VERSION 5.7 ;
  NOWIREEXTENSIONATPIN ON ;
  DIVIDERCHAR "/" ;
  BUSBITCHARS "[]" ;
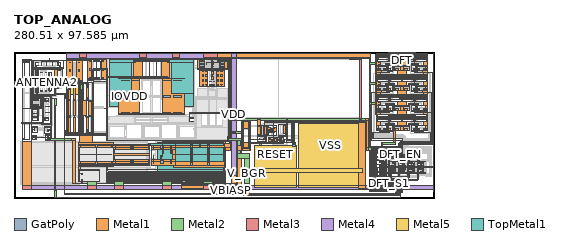
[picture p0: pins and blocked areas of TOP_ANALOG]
MACRO TOP_ANALOG
  CLASS BLOCK ;
  FOREIGN TOP_ANALOG ;
  ORIGIN 0.000 0.000 ;
  SIZE 280.510 BY 97.585 ;
  PIN RESET
    ANTENNAGATEAREA 0.767000 ;
    ANTENNADIFFAREA 5.126000 ;
    PORT
      LAYER GatPoly ;
        RECT 167.065 39.430 167.365 39.685 ;
        RECT 163.665 39.300 163.845 39.430 ;
        RECT 166.795 39.300 167.365 39.430 ;
        RECT 167.065 39.045 167.365 39.300 ;
        RECT 185.400 38.120 186.040 38.200 ;
        RECT 181.985 37.990 182.165 38.120 ;
        RECT 185.115 37.990 186.040 38.120 ;
        RECT 185.400 37.900 186.040 37.990 ;
      LAYER Metal1 ;
        RECT 263.590 53.415 265.520 53.455 ;
        RECT 260.520 53.255 265.520 53.415 ;
        RECT 263.590 53.245 265.520 53.255 ;
        RECT 267.415 51.530 267.705 53.705 ;
        RECT 269.410 53.415 271.340 53.455 ;
        RECT 269.410 53.255 274.420 53.415 ;
        RECT 269.410 53.245 271.340 53.255 ;
        RECT 267.465 51.325 267.675 51.530 ;
        RECT 229.950 51.200 234.655 51.275 ;
        RECT 229.810 50.580 234.655 51.200 ;
        RECT 172.930 46.595 173.090 46.680 ;
        RECT 172.905 44.255 173.115 46.595 ;
        RECT 172.930 44.080 173.090 44.255 ;
        RECT 167.110 39.015 167.320 39.715 ;
        RECT 172.930 38.830 173.090 38.925 ;
        RECT 172.905 37.720 173.115 38.830 ;
        RECT 185.370 37.945 186.070 38.155 ;
        RECT 172.930 37.625 173.090 37.720 ;
        RECT 229.950 5.485 234.655 50.580 ;
        RECT 278.235 43.915 278.435 43.920 ;
        RECT 278.225 43.625 278.435 43.915 ;
        RECT 257.880 37.235 258.090 37.525 ;
        RECT 278.235 37.515 278.435 43.625 ;
        RECT 240.120 32.460 240.330 32.750 ;
        RECT 257.880 32.740 258.080 37.235 ;
        RECT 278.225 37.225 278.435 37.515 ;
        RECT 240.120 6.385 240.320 32.460 ;
        RECT 257.870 32.450 258.080 32.740 ;
        RECT 240.115 6.095 240.325 6.385 ;
        RECT 256.230 6.105 256.440 6.395 ;
        RECT 256.240 3.920 256.440 6.105 ;
      LAYER Metal2 ;
        RECT 267.485 53.450 267.685 53.705 ;
        RECT 263.590 53.250 271.340 53.450 ;
        RECT 267.485 53.005 267.685 53.250 ;
        RECT 229.810 50.585 234.610 51.195 ;
        RECT 267.470 49.350 267.670 52.025 ;
        RECT 267.470 49.125 269.335 49.350 ;
        RECT 172.910 44.255 173.110 46.595 ;
        RECT 269.115 43.920 269.335 49.125 ;
        RECT 269.115 43.620 278.440 43.920 ;
        RECT 167.065 39.015 167.365 39.715 ;
        RECT 172.910 37.720 173.110 38.830 ;
        RECT 185.370 37.900 186.070 38.200 ;
        RECT 257.880 37.225 278.435 37.525 ;
        RECT 240.120 32.450 258.080 32.750 ;
        RECT 230.235 6.395 234.215 6.575 ;
        RECT 229.950 6.095 256.440 6.395 ;
        RECT 230.235 5.965 234.215 6.095 ;
      LAYER Metal3 ;
        RECT 167.110 39.220 167.320 51.275 ;
        RECT 173.210 46.595 173.410 51.275 ;
        RECT 172.910 44.255 173.410 46.595 ;
        RECT 167.115 39.015 167.315 39.220 ;
        RECT 173.210 38.830 173.410 44.255 ;
        RECT 172.910 37.720 173.410 38.830 ;
        RECT 185.655 38.150 185.965 51.275 ;
        RECT 185.370 37.950 186.070 38.150 ;
        RECT 185.655 37.900 185.965 37.950 ;
        RECT 186.790 36.510 187.100 51.265 ;
        RECT 229.810 50.585 234.610 51.195 ;
        RECT 186.595 35.900 187.295 36.510 ;
      LAYER Metal4 ;
        RECT 167.110 50.450 234.655 51.275 ;
        RECT 186.595 35.900 187.295 36.510 ;
      LAYER Metal5 ;
        RECT 186.595 35.895 187.295 36.515 ;
      LAYER TopMetal1 ;
        RECT 186.125 34.325 187.765 37.025 ;
        RECT 161.305 7.865 187.765 34.325 ;
    END
  END RESET
  PIN CLK
    ANTENNADIFFAREA 4.432400 ;
    PORT
      LAYER Metal1 ;
        RECT 27.070 61.650 28.100 66.450 ;
        RECT 13.665 40.595 13.825 40.860 ;
        RECT 22.355 40.595 22.515 40.910 ;
        RECT 13.665 40.385 14.355 40.595 ;
        RECT 21.665 40.385 22.515 40.595 ;
        RECT 13.665 40.120 13.825 40.385 ;
        RECT 22.355 39.790 22.515 40.385 ;
        RECT 27.130 5.065 28.045 61.650 ;
        RECT 246.760 53.415 248.690 53.455 ;
        RECT 243.680 53.255 248.690 53.415 ;
        RECT 246.760 53.245 248.690 53.255 ;
        RECT 250.395 51.530 250.685 53.705 ;
        RECT 252.580 53.415 254.510 53.455 ;
        RECT 252.580 53.255 257.580 53.415 ;
        RECT 252.580 53.245 254.510 53.255 ;
        RECT 250.425 51.325 250.635 51.530 ;
        RECT 239.660 43.915 239.860 43.920 ;
        RECT 239.660 43.625 239.870 43.915 ;
        RECT 239.660 39.915 239.860 43.625 ;
        RECT 239.660 39.625 239.870 39.915 ;
        RECT 259.510 39.635 259.720 39.925 ;
        RECT 241.760 30.060 241.970 30.350 ;
        RECT 259.520 30.340 259.720 39.635 ;
        RECT 241.760 8.785 241.960 30.060 ;
        RECT 259.510 30.050 259.720 30.340 ;
        RECT 241.755 8.495 241.965 8.785 ;
        RECT 257.870 8.505 258.080 8.795 ;
        RECT 27.080 0.265 28.110 5.065 ;
        RECT 257.880 0.515 258.080 8.505 ;
        RECT 256.120 0.305 258.080 0.515 ;
        RECT 27.130 0.255 28.045 0.265 ;
        RECT 257.880 0.255 258.080 0.305 ;
      LAYER Metal2 ;
        RECT 27.075 66.445 28.095 66.450 ;
        RECT 24.755 66.245 28.095 66.445 ;
        RECT 24.755 40.590 24.955 66.245 ;
        RECT 27.075 61.650 28.095 66.245 ;
        RECT 250.415 53.450 250.615 53.705 ;
        RECT 246.760 53.250 254.510 53.450 ;
        RECT 250.415 53.005 250.615 53.250 ;
        RECT 250.430 49.350 250.630 52.025 ;
        RECT 248.765 49.125 250.630 49.350 ;
        RECT 248.765 43.920 248.985 49.125 ;
        RECT 239.660 43.620 248.985 43.920 ;
        RECT 14.065 40.390 24.955 40.590 ;
        RECT 239.660 39.625 259.720 39.925 ;
        RECT 241.760 30.050 259.720 30.350 ;
        RECT 241.755 8.495 258.080 8.795 ;
        RECT 27.085 0.555 28.105 5.065 ;
        RECT 27.085 0.265 258.080 0.555 ;
        RECT 27.130 0.255 258.080 0.265 ;
    END
  END CLK
  PIN VBIASP
    ANTENNAGATEAREA 400.000000 ;
    ANTENNADIFFAREA 56.399998 ;
    PORT
      LAYER GatPoly ;
        RECT 53.010 91.465 55.010 91.645 ;
        RECT 55.390 91.465 57.390 91.645 ;
        RECT 86.050 91.465 88.050 91.645 ;
        RECT 88.430 91.465 90.430 91.645 ;
        RECT 90.810 91.465 92.810 91.645 ;
        RECT 93.190 91.465 95.190 91.645 ;
        RECT 95.570 91.465 97.570 91.645 ;
        RECT 53.010 86.285 55.010 86.465 ;
        RECT 55.390 86.355 57.390 86.465 ;
        RECT 55.390 86.285 57.395 86.355 ;
        RECT 53.010 86.055 57.395 86.285 ;
        RECT 53.010 85.475 57.390 86.055 ;
        RECT 53.010 85.295 55.010 85.475 ;
        RECT 55.390 85.295 57.390 85.475 ;
        RECT 29.230 84.965 31.230 85.145 ;
        RECT 86.050 81.285 88.050 81.465 ;
        RECT 88.430 81.285 90.430 81.465 ;
        RECT 90.810 81.285 92.810 81.465 ;
        RECT 93.190 81.285 95.190 81.465 ;
        RECT 95.570 81.285 97.570 81.465 ;
        RECT 86.050 80.670 97.570 81.285 ;
        RECT 53.010 80.115 55.010 80.295 ;
        RECT 55.390 80.115 57.390 80.295 ;
        RECT 29.230 74.565 31.230 74.965 ;
        RECT 107.670 31.560 107.850 33.560 ;
        RECT 117.850 31.560 119.090 33.560 ;
        RECT 129.090 31.560 130.330 33.560 ;
        RECT 140.330 31.560 140.510 33.560 ;
        RECT 118.030 31.180 118.910 31.560 ;
        RECT 129.270 31.180 130.150 31.560 ;
        RECT 107.670 29.180 107.850 31.180 ;
        RECT 117.850 29.180 119.090 31.180 ;
        RECT 129.090 29.180 130.330 31.180 ;
        RECT 140.330 29.180 140.510 31.180 ;
        RECT 118.030 28.800 118.910 29.180 ;
        RECT 129.270 28.800 130.150 29.180 ;
        RECT 107.670 26.800 107.850 28.800 ;
        RECT 117.850 26.800 119.090 28.800 ;
        RECT 129.090 26.800 130.330 28.800 ;
        RECT 140.330 26.800 140.510 28.800 ;
        RECT 118.030 26.420 118.910 26.800 ;
        RECT 129.270 26.420 130.150 26.800 ;
        RECT 107.670 24.420 107.850 26.420 ;
        RECT 117.850 24.420 119.090 26.420 ;
        RECT 129.090 24.420 130.330 26.420 ;
        RECT 140.330 24.420 140.510 26.420 ;
      LAYER Metal1 ;
        RECT 57.500 86.285 57.660 91.465 ;
        RECT 53.760 86.075 54.860 86.285 ;
        RECT 55.735 86.075 57.660 86.285 ;
        RECT 53.760 85.635 53.980 86.075 ;
        RECT 52.740 85.475 54.795 85.635 ;
        RECT 52.740 81.675 52.900 85.475 ;
        RECT 52.710 80.565 52.920 81.675 ;
        RECT 86.355 80.920 90.335 80.925 ;
        RECT 93.420 80.920 97.400 80.925 ;
        RECT 86.355 80.720 97.400 80.920 ;
        RECT 86.355 80.715 90.335 80.720 ;
        RECT 93.420 80.715 97.400 80.720 ;
        RECT 52.740 80.295 52.900 80.565 ;
        RECT 49.150 78.665 49.440 78.670 ;
        RECT 50.765 78.665 51.055 78.670 ;
        RECT 49.150 78.465 51.055 78.665 ;
        RECT 49.150 78.460 49.440 78.465 ;
        RECT 50.765 78.460 51.055 78.465 ;
        RECT 37.825 76.050 43.015 76.210 ;
        RECT 29.445 74.610 30.965 74.820 ;
        RECT 27.460 69.985 27.670 73.580 ;
        RECT 27.460 68.510 27.680 69.985 ;
        RECT 24.970 68.465 27.680 68.510 ;
        RECT 24.970 68.260 27.670 68.465 ;
        RECT 14.205 50.285 18.405 50.320 ;
        RECT 13.610 50.075 18.405 50.285 ;
        RECT 14.205 50.005 18.405 50.075 ;
        RECT 18.040 49.365 18.405 50.005 ;
        RECT 24.970 49.365 25.235 68.260 ;
        RECT 18.040 49.050 25.235 49.365 ;
        RECT 33.640 66.725 34.260 69.475 ;
        RECT 33.640 44.800 34.045 66.725 ;
        RECT 33.635 42.050 34.255 44.800 ;
        RECT 37.825 43.890 37.985 76.050 ;
        RECT 40.055 65.870 40.785 76.050 ;
        RECT 40.055 43.890 40.785 54.070 ;
        RECT 42.855 43.890 43.015 76.050 ;
        RECT 48.535 75.580 48.695 75.870 ;
        RECT 49.915 75.580 50.075 75.870 ;
        RECT 48.535 66.255 50.075 75.580 ;
        RECT 263.590 66.725 265.520 66.765 ;
        RECT 260.520 66.565 265.520 66.725 ;
        RECT 263.590 66.555 265.520 66.565 ;
        RECT 48.535 65.870 48.695 66.255 ;
        RECT 48.950 66.250 49.650 66.255 ;
        RECT 49.915 65.870 50.075 66.255 ;
        RECT 49.155 65.160 52.030 65.320 ;
        RECT 49.155 65.110 49.445 65.160 ;
        RECT 51.740 65.090 52.030 65.160 ;
        RECT 267.415 64.840 267.705 67.015 ;
        RECT 269.410 66.725 271.340 66.765 ;
        RECT 269.410 66.565 274.420 66.725 ;
        RECT 269.410 66.555 271.340 66.565 ;
        RECT 267.465 64.635 267.675 64.840 ;
        RECT 278.645 57.225 278.845 57.230 ;
        RECT 278.635 56.935 278.845 57.225 ;
        RECT 48.535 53.695 48.695 54.070 ;
        RECT 49.915 53.695 50.075 54.070 ;
        RECT 48.535 44.485 50.075 53.695 ;
        RECT 48.535 44.070 48.695 44.485 ;
        RECT 49.915 44.070 50.075 44.485 ;
        RECT 37.825 43.730 43.015 43.890 ;
        RECT 33.640 2.655 34.045 42.050 ;
        RECT 61.965 38.445 124.275 38.660 ;
        RECT 257.470 36.635 257.680 36.925 ;
        RECT 278.645 36.915 278.845 56.935 ;
        RECT 118.545 32.525 118.755 33.285 ;
        RECT 118.400 31.765 118.755 32.525 ;
        RECT 118.400 26.125 118.560 31.765 ;
        RECT 129.390 29.425 129.600 33.475 ;
        RECT 239.710 33.060 239.920 33.350 ;
        RECT 257.470 33.340 257.670 36.635 ;
        RECT 278.635 36.625 278.845 36.915 ;
        RECT 129.390 27.130 129.600 28.650 ;
        RECT 118.400 25.700 118.765 26.125 ;
        RECT 118.555 24.605 118.765 25.700 ;
        RECT 239.710 5.785 239.910 33.060 ;
        RECT 257.460 33.050 257.670 33.340 ;
        RECT 239.705 5.495 239.915 5.785 ;
        RECT 255.820 5.505 256.030 5.795 ;
        RECT 255.830 2.915 256.030 5.505 ;
        RECT 254.070 2.705 256.030 2.915 ;
        RECT 255.830 2.655 256.030 2.705 ;
      LAYER Metal2 ;
        RECT 54.570 86.080 62.345 86.280 ;
        RECT 52.715 78.665 52.915 81.675 ;
        RECT 49.150 78.465 49.440 78.665 ;
        RECT 50.765 78.465 52.915 78.665 ;
        RECT 61.965 80.920 62.345 86.080 ;
        RECT 61.965 80.720 90.335 80.920 ;
        RECT 93.420 80.720 97.400 80.920 ;
        RECT 40.300 76.860 40.520 77.220 ;
        RECT 49.190 76.860 49.410 78.465 ;
        RECT 40.295 76.625 49.410 76.860 ;
        RECT 40.300 75.845 40.520 76.625 ;
        RECT 29.445 74.615 30.965 74.815 ;
        RECT 40.105 74.735 40.715 75.845 ;
        RECT 49.190 75.575 49.410 76.625 ;
        RECT 29.695 73.600 29.945 74.615 ;
        RECT 48.995 74.055 49.605 75.575 ;
        RECT 27.445 73.330 29.945 73.600 ;
        RECT 27.465 71.240 27.665 73.330 ;
        RECT 27.475 69.475 27.675 69.985 ;
        RECT 27.460 68.975 34.255 69.475 ;
        RECT 27.475 68.465 27.675 68.975 ;
        RECT 33.645 66.725 34.255 68.975 ;
        RECT 48.950 66.255 49.650 66.865 ;
        RECT 49.155 65.115 49.445 66.255 ;
        RECT 51.740 65.095 52.030 65.295 ;
        RECT 5.110 50.080 15.130 50.280 ;
        RECT 48.975 44.960 49.675 45.570 ;
        RECT 33.640 42.370 34.250 44.800 ;
        RECT 49.150 43.475 49.375 44.960 ;
        RECT 51.780 43.475 52.010 65.095 ;
        RECT 49.150 43.270 52.010 43.475 ;
        RECT 61.965 42.370 62.345 80.720 ;
        RECT 267.485 66.760 267.685 67.015 ;
        RECT 263.590 66.560 271.340 66.760 ;
        RECT 267.485 66.315 267.685 66.560 ;
        RECT 267.470 62.660 267.670 65.335 ;
        RECT 267.470 62.435 269.335 62.660 ;
        RECT 269.115 57.230 269.335 62.435 ;
        RECT 269.115 56.930 278.850 57.230 ;
        RECT 33.640 42.060 62.345 42.370 ;
        RECT 33.640 42.050 34.250 42.060 ;
        RECT 61.965 38.655 62.345 42.060 ;
        RECT 124.025 38.655 124.275 38.660 ;
        RECT 61.965 38.455 62.665 38.655 ;
        RECT 123.575 38.455 124.275 38.655 ;
        RECT 124.025 34.015 124.275 38.455 ;
        RECT 257.470 36.625 278.845 36.925 ;
        RECT 118.550 33.785 129.595 34.015 ;
        RECT 118.550 31.765 118.750 33.785 ;
        RECT 129.395 31.955 129.595 33.785 ;
        RECT 239.710 33.050 257.670 33.350 ;
        RECT 129.395 27.130 129.595 30.945 ;
        RECT 118.560 24.605 118.760 26.125 ;
        RECT 33.755 2.955 33.955 7.105 ;
        RECT 239.705 5.495 256.030 5.795 ;
        RECT 33.640 2.655 256.030 2.955 ;
    END
  END VBIASP
  PIN DFT_S2
    ANTENNAGATEAREA 1.011400 ;
    PORT
      LAYER GatPoly ;
        RECT 244.515 26.800 244.645 26.980 ;
        RECT 244.515 25.455 244.645 25.680 ;
        RECT 244.175 25.125 244.645 25.455 ;
        RECT 244.515 24.935 244.645 25.125 ;
        RECT 244.515 24.015 244.645 24.195 ;
        RECT 253.830 19.680 253.960 19.860 ;
        RECT 260.105 19.680 260.235 19.860 ;
        RECT 266.380 19.680 266.510 19.860 ;
        RECT 272.655 19.680 272.785 19.860 ;
        RECT 253.830 18.690 253.960 19.040 ;
        RECT 260.105 18.690 260.235 19.040 ;
        RECT 266.380 18.690 266.510 19.040 ;
        RECT 272.655 18.690 272.785 19.040 ;
        RECT 253.830 18.390 254.130 18.690 ;
        RECT 260.105 18.390 260.405 18.690 ;
        RECT 266.380 18.390 266.680 18.690 ;
        RECT 272.655 18.390 272.955 18.690 ;
        RECT 253.830 17.930 253.960 18.390 ;
        RECT 260.105 17.930 260.235 18.390 ;
        RECT 266.380 17.930 266.510 18.390 ;
        RECT 272.655 17.930 272.785 18.390 ;
        RECT 253.830 16.910 253.960 17.090 ;
        RECT 260.105 16.910 260.235 17.090 ;
        RECT 266.380 16.910 266.510 17.090 ;
        RECT 272.655 16.910 272.785 17.090 ;
      LAYER Metal1 ;
        RECT 242.155 25.430 242.355 25.455 ;
        RECT 242.155 25.140 242.365 25.430 ;
        RECT 242.155 9.385 242.355 25.140 ;
        RECT 244.175 25.125 244.490 25.455 ;
        RECT 245.160 24.605 245.450 24.610 ;
        RECT 247.135 24.605 247.345 24.650 ;
        RECT 245.160 24.405 247.345 24.605 ;
        RECT 245.160 24.400 245.450 24.405 ;
        RECT 247.135 24.360 247.345 24.405 ;
        RECT 253.865 18.285 254.110 18.815 ;
        RECT 260.140 18.285 260.385 18.815 ;
        RECT 266.415 18.285 266.660 18.815 ;
        RECT 272.690 18.285 272.935 18.815 ;
        RECT 247.135 12.440 247.345 12.570 ;
        RECT 250.805 12.440 251.015 12.500 ;
        RECT 257.080 12.440 257.290 12.500 ;
        RECT 263.355 12.440 263.565 12.505 ;
        RECT 269.630 12.440 269.840 12.505 ;
        RECT 247.135 12.280 269.840 12.440 ;
        RECT 250.805 12.210 251.015 12.280 ;
        RECT 257.080 12.210 257.290 12.280 ;
        RECT 263.355 12.215 263.565 12.280 ;
        RECT 269.630 12.215 269.840 12.280 ;
        RECT 242.150 9.095 242.360 9.385 ;
        RECT 258.280 9.105 258.490 9.395 ;
        RECT 258.290 3.920 258.490 9.105 ;
      LAYER Metal2 ;
        RECT 242.155 25.115 244.490 25.455 ;
        RECT 244.195 24.605 244.490 25.115 ;
        RECT 244.195 24.405 245.450 24.605 ;
        RECT 247.140 12.280 247.340 24.650 ;
        RECT 250.810 18.940 254.090 19.140 ;
        RECT 250.810 12.210 251.010 18.940 ;
        RECT 253.890 18.385 254.090 18.940 ;
        RECT 257.085 18.940 260.365 19.140 ;
        RECT 257.085 12.210 257.285 18.940 ;
        RECT 260.165 18.385 260.365 18.940 ;
        RECT 263.360 18.940 266.640 19.140 ;
        RECT 263.360 12.215 263.560 18.940 ;
        RECT 266.440 18.385 266.640 18.940 ;
        RECT 269.635 18.940 272.915 19.140 ;
        RECT 269.635 12.215 269.835 18.940 ;
        RECT 272.715 18.385 272.915 18.940 ;
        RECT 242.150 9.095 258.490 9.395 ;
    END
  END DFT_S2
  PIN DFT_S1
    ANTENNAGATEAREA 1.011400 ;
    PORT
      LAYER GatPoly ;
        RECT 265.360 23.810 265.490 23.990 ;
        RECT 271.635 23.810 271.765 23.990 ;
        RECT 265.360 22.510 265.490 22.970 ;
        RECT 271.635 22.510 271.765 22.970 ;
        RECT 265.320 22.210 265.620 22.510 ;
        RECT 271.595 22.210 271.895 22.510 ;
        RECT 244.515 21.715 244.645 21.895 ;
        RECT 265.360 21.860 265.490 22.210 ;
        RECT 271.635 21.860 271.765 22.210 ;
        RECT 265.360 21.040 265.490 21.220 ;
        RECT 271.635 21.040 271.765 21.220 ;
        RECT 244.515 20.370 244.645 20.595 ;
        RECT 244.175 20.040 244.645 20.370 ;
        RECT 244.515 19.850 244.645 20.040 ;
        RECT 252.810 19.680 252.940 19.860 ;
        RECT 259.085 19.680 259.215 19.860 ;
        RECT 244.515 18.930 244.645 19.110 ;
        RECT 252.810 18.690 252.940 19.040 ;
        RECT 259.085 18.690 259.215 19.040 ;
        RECT 252.770 18.390 253.070 18.690 ;
        RECT 259.045 18.390 259.345 18.690 ;
        RECT 252.810 17.930 252.940 18.390 ;
        RECT 259.085 17.930 259.215 18.390 ;
        RECT 252.810 16.910 252.940 17.090 ;
        RECT 259.085 16.910 259.215 17.090 ;
      LAYER Metal1 ;
        RECT 263.765 27.520 263.975 27.580 ;
        RECT 270.040 27.520 270.250 27.580 ;
        RECT 247.955 27.360 270.250 27.520 ;
        RECT 247.955 27.230 248.165 27.360 ;
        RECT 263.765 27.290 263.975 27.360 ;
        RECT 270.040 27.290 270.250 27.360 ;
        RECT 265.340 22.085 265.695 22.615 ;
        RECT 271.615 22.085 271.970 22.615 ;
        RECT 242.565 20.350 242.765 20.370 ;
        RECT 242.565 20.060 242.775 20.350 ;
        RECT 242.565 9.985 242.765 20.060 ;
        RECT 244.175 20.040 244.490 20.370 ;
        RECT 245.165 19.520 245.455 19.525 ;
        RECT 247.955 19.520 248.165 19.565 ;
        RECT 245.165 19.320 248.165 19.520 ;
        RECT 245.165 19.315 245.455 19.320 ;
        RECT 247.955 19.275 248.165 19.320 ;
        RECT 252.790 18.285 253.145 18.815 ;
        RECT 259.065 18.285 259.420 18.815 ;
        RECT 247.955 13.320 248.165 13.450 ;
        RECT 251.215 13.320 251.425 13.385 ;
        RECT 257.490 13.320 257.700 13.370 ;
        RECT 247.955 13.160 257.700 13.320 ;
        RECT 251.215 13.095 251.425 13.160 ;
        RECT 257.490 13.080 257.700 13.160 ;
        RECT 242.560 9.695 242.770 9.985 ;
        RECT 258.690 9.705 258.900 9.995 ;
        RECT 258.700 3.920 258.900 9.705 ;
      LAYER Metal2 ;
        RECT 242.565 20.040 244.490 20.370 ;
        RECT 244.195 19.520 244.490 20.040 ;
        RECT 244.195 19.320 245.455 19.520 ;
        RECT 247.960 13.160 248.160 27.520 ;
        RECT 263.770 23.010 263.970 27.580 ;
        RECT 270.045 23.010 270.245 27.580 ;
        RECT 263.770 22.810 265.570 23.010 ;
        RECT 270.045 22.810 271.845 23.010 ;
        RECT 265.370 22.215 265.570 22.810 ;
        RECT 271.645 22.215 271.845 22.810 ;
        RECT 252.820 18.090 253.020 18.685 ;
        RECT 259.095 18.090 259.295 18.685 ;
        RECT 251.220 17.890 253.020 18.090 ;
        RECT 257.495 17.890 259.295 18.090 ;
        RECT 251.220 13.095 251.420 17.890 ;
        RECT 257.495 13.080 257.695 17.890 ;
        RECT 242.560 9.695 258.900 9.995 ;
    END
  END DFT_S1
  PIN DFT_S0
    ANTENNAGATEAREA 1.011400 ;
    PORT
      LAYER GatPoly ;
        RECT 259.595 23.810 259.725 23.990 ;
        RECT 272.145 23.810 272.275 23.990 ;
        RECT 259.595 22.510 259.725 22.970 ;
        RECT 272.145 22.510 272.275 22.970 ;
        RECT 259.595 22.210 259.925 22.510 ;
        RECT 272.145 22.210 272.475 22.510 ;
        RECT 259.595 21.860 259.725 22.210 ;
        RECT 272.145 21.860 272.275 22.210 ;
        RECT 259.595 21.040 259.725 21.220 ;
        RECT 272.145 21.040 272.275 21.220 ;
        RECT 253.320 19.680 253.450 19.860 ;
        RECT 265.870 19.680 266.000 19.860 ;
        RECT 253.320 18.690 253.450 19.040 ;
        RECT 265.870 18.690 266.000 19.040 ;
        RECT 253.320 18.390 253.650 18.690 ;
        RECT 265.870 18.390 266.200 18.690 ;
        RECT 253.320 17.930 253.450 18.390 ;
        RECT 265.870 17.930 266.000 18.390 ;
        RECT 253.320 16.910 253.450 17.090 ;
        RECT 265.870 16.910 266.000 17.090 ;
        RECT 244.515 16.585 244.645 16.765 ;
        RECT 244.515 15.240 244.645 15.465 ;
        RECT 244.175 14.910 244.645 15.240 ;
        RECT 244.515 14.720 244.645 14.910 ;
        RECT 244.515 13.800 244.645 13.980 ;
      LAYER Metal1 ;
        RECT 257.900 26.640 258.110 26.705 ;
        RECT 270.450 26.640 270.660 26.705 ;
        RECT 248.775 26.480 270.660 26.640 ;
        RECT 248.775 26.350 248.985 26.480 ;
        RECT 257.900 26.415 258.110 26.480 ;
        RECT 270.450 26.415 270.660 26.480 ;
        RECT 259.625 22.085 259.900 22.615 ;
        RECT 272.175 22.085 272.450 22.615 ;
        RECT 253.350 18.285 253.625 18.815 ;
        RECT 265.900 18.285 266.175 18.815 ;
        RECT 242.975 15.225 243.175 15.240 ;
        RECT 242.975 14.935 243.185 15.225 ;
        RECT 242.975 10.585 243.175 14.935 ;
        RECT 244.175 14.910 244.490 15.240 ;
        RECT 245.160 14.375 245.450 14.380 ;
        RECT 248.775 14.375 248.985 14.740 ;
        RECT 245.160 14.200 248.985 14.375 ;
        RECT 251.625 14.200 251.835 14.265 ;
        RECT 264.175 14.200 264.385 14.265 ;
        RECT 245.160 14.175 264.385 14.200 ;
        RECT 245.160 14.170 245.450 14.175 ;
        RECT 248.775 14.040 264.385 14.175 ;
        RECT 251.625 13.975 251.835 14.040 ;
        RECT 264.175 13.975 264.385 14.040 ;
        RECT 242.970 10.295 243.180 10.585 ;
        RECT 259.100 10.305 259.310 10.595 ;
        RECT 259.110 3.920 259.310 10.305 ;
      LAYER Metal2 ;
        RECT 242.975 14.905 244.490 15.240 ;
        RECT 244.195 14.375 244.490 14.905 ;
        RECT 244.195 14.175 245.450 14.375 ;
        RECT 248.780 14.040 248.980 26.640 ;
        RECT 257.905 23.435 258.105 26.705 ;
        RECT 270.455 23.435 270.655 26.705 ;
        RECT 257.905 23.235 259.855 23.435 ;
        RECT 270.455 23.235 272.405 23.435 ;
        RECT 259.650 22.465 259.855 23.235 ;
        RECT 272.200 22.465 272.405 23.235 ;
        RECT 259.650 22.215 259.850 22.465 ;
        RECT 272.200 22.215 272.400 22.465 ;
        RECT 253.375 18.435 253.575 18.685 ;
        RECT 265.925 18.435 266.125 18.685 ;
        RECT 253.375 17.665 253.580 18.435 ;
        RECT 265.925 17.665 266.130 18.435 ;
        RECT 251.630 17.465 253.580 17.665 ;
        RECT 264.180 17.465 266.130 17.665 ;
        RECT 251.630 13.975 251.830 17.465 ;
        RECT 264.180 13.975 264.380 17.465 ;
        RECT 242.970 10.295 259.310 10.595 ;
    END
  END DFT_S0
  PIN DFT_EN
    ANTENNAGATEAREA 1.539200 ;
    PORT
      LAYER GatPoly ;
        RECT 254.400 23.810 254.530 23.990 ;
        RECT 260.675 23.810 260.805 23.990 ;
        RECT 266.950 23.810 267.080 23.990 ;
        RECT 273.225 23.810 273.355 23.990 ;
        RECT 254.400 22.510 254.530 22.970 ;
        RECT 260.675 22.510 260.805 22.970 ;
        RECT 266.950 22.510 267.080 22.970 ;
        RECT 273.225 22.510 273.355 22.970 ;
        RECT 254.400 22.210 254.710 22.510 ;
        RECT 260.675 22.210 260.985 22.510 ;
        RECT 266.950 22.210 267.260 22.510 ;
        RECT 273.225 22.210 273.535 22.510 ;
        RECT 254.400 21.860 254.530 22.210 ;
        RECT 260.675 21.860 260.805 22.210 ;
        RECT 266.950 21.860 267.080 22.210 ;
        RECT 273.225 21.860 273.355 22.210 ;
        RECT 254.400 21.040 254.530 21.220 ;
        RECT 260.675 21.040 260.805 21.220 ;
        RECT 266.950 21.040 267.080 21.220 ;
        RECT 273.225 21.040 273.355 21.220 ;
        RECT 254.400 19.680 254.530 19.860 ;
        RECT 260.675 19.680 260.805 19.860 ;
        RECT 266.950 19.680 267.080 19.860 ;
        RECT 273.225 19.680 273.355 19.860 ;
        RECT 254.400 18.690 254.530 19.040 ;
        RECT 260.675 18.690 260.805 19.040 ;
        RECT 266.950 18.690 267.080 19.040 ;
        RECT 273.225 18.690 273.355 19.040 ;
        RECT 254.400 18.390 254.710 18.690 ;
        RECT 260.675 18.390 260.985 18.690 ;
        RECT 266.950 18.390 267.260 18.690 ;
        RECT 273.225 18.390 273.535 18.690 ;
        RECT 254.400 17.930 254.530 18.390 ;
        RECT 260.675 17.930 260.805 18.390 ;
        RECT 266.950 17.930 267.080 18.390 ;
        RECT 273.225 17.930 273.355 18.390 ;
        RECT 254.400 16.910 254.530 17.090 ;
        RECT 260.675 16.910 260.805 17.090 ;
        RECT 266.950 16.910 267.080 17.090 ;
        RECT 273.225 16.910 273.355 17.090 ;
      LAYER Metal1 ;
        RECT 246.690 28.840 246.980 28.865 ;
        RECT 250.355 28.840 250.645 28.865 ;
        RECT 256.630 28.840 256.920 28.865 ;
        RECT 262.905 28.840 263.195 28.865 ;
        RECT 269.180 28.840 269.470 28.865 ;
        RECT 246.690 28.680 269.470 28.840 ;
        RECT 246.690 28.655 246.980 28.680 ;
        RECT 250.355 28.655 250.645 28.680 ;
        RECT 256.630 28.655 256.920 28.680 ;
        RECT 262.905 28.655 263.195 28.680 ;
        RECT 269.180 28.655 269.470 28.680 ;
        RECT 254.380 22.080 254.730 22.630 ;
        RECT 260.655 22.080 261.005 22.630 ;
        RECT 266.930 22.080 267.280 22.630 ;
        RECT 273.205 22.080 273.555 22.630 ;
        RECT 254.380 18.270 254.730 18.820 ;
        RECT 260.655 18.270 261.005 18.820 ;
        RECT 266.930 18.270 267.280 18.820 ;
        RECT 273.205 18.270 273.555 18.820 ;
        RECT 246.690 12.000 246.980 12.025 ;
        RECT 250.355 12.000 250.645 12.025 ;
        RECT 256.630 12.000 256.920 12.025 ;
        RECT 262.905 12.000 263.195 12.025 ;
        RECT 269.180 12.000 269.470 12.025 ;
        RECT 246.690 11.840 269.470 12.000 ;
        RECT 246.690 11.815 246.980 11.840 ;
        RECT 250.355 11.815 250.645 11.840 ;
        RECT 256.630 11.815 256.920 11.840 ;
        RECT 259.520 3.920 259.720 11.840 ;
        RECT 262.905 11.815 263.195 11.840 ;
        RECT 269.180 11.815 269.470 11.840 ;
      LAYER Metal2 ;
        RECT 246.690 28.660 246.980 28.860 ;
        RECT 250.355 28.660 250.645 28.860 ;
        RECT 256.630 28.660 256.920 28.860 ;
        RECT 262.905 28.660 263.195 28.860 ;
        RECT 269.180 28.660 269.470 28.860 ;
        RECT 246.730 12.020 246.930 28.660 ;
        RECT 250.400 21.550 250.600 28.660 ;
        RECT 254.450 21.550 254.650 22.515 ;
        RECT 250.400 21.350 254.650 21.550 ;
        RECT 256.675 21.550 256.875 28.660 ;
        RECT 260.725 21.550 260.925 22.515 ;
        RECT 256.675 21.350 260.925 21.550 ;
        RECT 262.950 21.550 263.150 28.660 ;
        RECT 267.000 21.550 267.200 22.515 ;
        RECT 262.950 21.350 267.200 21.550 ;
        RECT 269.225 21.550 269.425 28.660 ;
        RECT 273.275 21.550 273.475 22.515 ;
        RECT 269.225 21.350 273.475 21.550 ;
        RECT 250.400 19.350 254.650 19.550 ;
        RECT 250.400 12.020 250.600 19.350 ;
        RECT 254.450 18.385 254.650 19.350 ;
        RECT 256.675 19.350 260.925 19.550 ;
        RECT 256.675 12.020 256.875 19.350 ;
        RECT 260.725 18.385 260.925 19.350 ;
        RECT 262.950 19.350 267.200 19.550 ;
        RECT 262.950 12.020 263.150 19.350 ;
        RECT 267.000 18.385 267.200 19.350 ;
        RECT 269.225 19.350 273.475 19.550 ;
        RECT 269.225 12.020 269.425 19.350 ;
        RECT 273.275 18.385 273.475 19.350 ;
        RECT 246.690 11.820 246.980 12.020 ;
        RECT 250.355 11.820 250.645 12.020 ;
        RECT 256.630 11.820 256.920 12.020 ;
        RECT 262.905 11.820 263.195 12.020 ;
        RECT 269.180 11.820 269.470 12.020 ;
    END
  END DFT_EN
  PIN ANTENNA2
    ANTENNAGATEAREA 9.000000 ;
    PORT
      LAYER GatPoly ;
        RECT 20.720 83.570 21.720 83.750 ;
        RECT 20.720 78.890 21.720 79.070 ;
        RECT 21.045 77.390 21.365 78.890 ;
        RECT 18.020 77.090 21.365 77.390 ;
        RECT 18.190 76.185 18.490 77.090 ;
        RECT 17.800 76.005 18.800 76.185 ;
        RECT 17.800 71.325 18.800 71.505 ;
      LAYER Metal1 ;
        RECT 17.990 77.135 18.690 77.345 ;
      LAYER Metal2 ;
        RECT 0.000 77.140 18.690 77.340 ;
    END
  END ANTENNA2
  PIN ANTENNA1
    ANTENNAGATEAREA 9.000000 ;
    PORT
      LAYER GatPoly ;
        RECT 17.800 83.570 18.800 83.750 ;
        RECT 17.800 78.890 18.800 79.070 ;
        RECT 18.240 78.010 18.445 78.890 ;
        RECT 18.025 77.710 18.665 78.010 ;
        RECT 20.890 76.605 21.530 76.905 ;
        RECT 21.145 76.185 21.290 76.605 ;
        RECT 20.720 76.005 21.720 76.185 ;
        RECT 20.720 71.325 21.720 71.505 ;
      LAYER Metal1 ;
        RECT 17.995 77.755 18.695 77.965 ;
        RECT 20.860 76.650 21.560 76.860 ;
      LAYER Metal2 ;
        RECT 0.020 77.760 19.960 77.960 ;
        RECT 19.725 76.855 19.960 77.760 ;
        RECT 19.725 76.655 21.560 76.855 ;
    END
  END ANTENNA1
  PIN DFT
    ANTENNADIFFAREA 54.399998 ;
    PORT
      LAYER Metal1 ;
        RECT 241.710 95.680 241.920 95.970 ;
        RECT 276.175 95.680 276.385 95.970 ;
        RECT 241.710 82.655 241.910 95.680 ;
        RECT 246.760 94.185 248.690 94.210 ;
        RECT 243.155 94.025 248.690 94.185 ;
        RECT 243.155 92.525 243.500 94.025 ;
        RECT 246.760 94.000 248.690 94.025 ;
        RECT 252.580 94.185 254.510 94.210 ;
        RECT 263.590 94.185 265.520 94.210 ;
        RECT 252.580 94.025 258.105 94.185 ;
        RECT 252.580 94.000 254.510 94.025 ;
        RECT 246.760 92.525 248.690 92.605 ;
        RECT 243.155 92.395 248.690 92.525 ;
        RECT 252.580 92.525 254.510 92.605 ;
        RECT 257.760 92.525 258.105 94.025 ;
        RECT 243.155 92.365 248.680 92.395 ;
        RECT 252.580 92.365 258.105 92.525 ;
        RECT 259.995 94.025 265.520 94.185 ;
        RECT 259.995 92.525 260.340 94.025 ;
        RECT 263.590 94.000 265.520 94.025 ;
        RECT 269.410 94.185 271.340 94.210 ;
        RECT 269.410 94.025 274.945 94.185 ;
        RECT 269.410 94.000 271.340 94.025 ;
        RECT 263.590 92.525 265.520 92.605 ;
        RECT 259.995 92.365 265.520 92.525 ;
        RECT 269.410 92.525 271.340 92.605 ;
        RECT 274.600 92.525 274.945 94.025 ;
        RECT 269.410 92.395 274.945 92.525 ;
        RECT 269.420 92.365 274.945 92.395 ;
        RECT 276.185 82.655 276.385 95.680 ;
        RECT 241.710 82.365 241.920 82.655 ;
        RECT 276.175 82.365 276.385 82.655 ;
        RECT 241.710 69.340 241.910 82.365 ;
        RECT 246.760 80.870 248.690 80.895 ;
        RECT 243.155 80.710 248.690 80.870 ;
        RECT 243.155 79.210 243.500 80.710 ;
        RECT 246.760 80.685 248.690 80.710 ;
        RECT 252.580 80.870 254.510 80.895 ;
        RECT 263.590 80.870 265.520 80.895 ;
        RECT 252.580 80.710 258.105 80.870 ;
        RECT 252.580 80.685 254.510 80.710 ;
        RECT 246.760 79.210 248.690 79.290 ;
        RECT 243.155 79.080 248.690 79.210 ;
        RECT 252.580 79.210 254.510 79.290 ;
        RECT 257.760 79.210 258.105 80.710 ;
        RECT 243.155 79.050 248.680 79.080 ;
        RECT 252.580 79.050 258.105 79.210 ;
        RECT 259.995 80.710 265.520 80.870 ;
        RECT 259.995 79.210 260.340 80.710 ;
        RECT 263.590 80.685 265.520 80.710 ;
        RECT 269.410 80.870 271.340 80.895 ;
        RECT 269.410 80.710 274.945 80.870 ;
        RECT 269.410 80.685 271.340 80.710 ;
        RECT 263.590 79.210 265.520 79.290 ;
        RECT 259.995 79.050 265.520 79.210 ;
        RECT 269.410 79.210 271.340 79.290 ;
        RECT 274.600 79.210 274.945 80.710 ;
        RECT 269.410 79.080 274.945 79.210 ;
        RECT 269.420 79.050 274.945 79.080 ;
        RECT 276.185 69.340 276.385 82.365 ;
        RECT 241.710 69.050 241.920 69.340 ;
        RECT 276.175 69.050 276.385 69.340 ;
        RECT 241.710 56.025 241.910 69.050 ;
        RECT 246.760 67.555 248.690 67.580 ;
        RECT 243.155 67.395 248.690 67.555 ;
        RECT 243.155 65.895 243.500 67.395 ;
        RECT 246.760 67.370 248.690 67.395 ;
        RECT 252.580 67.555 254.510 67.580 ;
        RECT 263.590 67.555 265.520 67.580 ;
        RECT 252.580 67.395 258.105 67.555 ;
        RECT 252.580 67.370 254.510 67.395 ;
        RECT 246.760 65.895 248.690 65.975 ;
        RECT 243.155 65.765 248.690 65.895 ;
        RECT 252.580 65.895 254.510 65.975 ;
        RECT 257.760 65.895 258.105 67.395 ;
        RECT 243.155 65.735 248.680 65.765 ;
        RECT 252.580 65.735 258.105 65.895 ;
        RECT 259.995 67.395 265.520 67.555 ;
        RECT 259.995 65.895 260.340 67.395 ;
        RECT 263.590 67.370 265.520 67.395 ;
        RECT 269.410 67.555 271.340 67.580 ;
        RECT 269.410 67.395 274.945 67.555 ;
        RECT 269.410 67.370 271.340 67.395 ;
        RECT 263.590 65.895 265.520 65.975 ;
        RECT 259.995 65.735 265.520 65.895 ;
        RECT 269.410 65.895 271.340 65.975 ;
        RECT 274.600 65.895 274.945 67.395 ;
        RECT 269.410 65.765 274.945 65.895 ;
        RECT 269.420 65.735 274.945 65.765 ;
        RECT 276.185 56.025 276.385 69.050 ;
        RECT 241.710 55.735 241.920 56.025 ;
        RECT 276.175 55.735 276.385 56.025 ;
        RECT 241.710 55.730 241.910 55.735 ;
        RECT 276.185 55.730 276.385 55.735 ;
        RECT 246.760 54.245 248.690 54.270 ;
        RECT 243.155 54.085 248.690 54.245 ;
        RECT 243.155 52.585 243.500 54.085 ;
        RECT 246.760 54.060 248.690 54.085 ;
        RECT 252.580 54.245 254.510 54.270 ;
        RECT 263.590 54.245 265.520 54.270 ;
        RECT 252.580 54.085 258.105 54.245 ;
        RECT 252.580 54.060 254.510 54.085 ;
        RECT 246.760 52.585 248.690 52.665 ;
        RECT 243.155 52.455 248.690 52.585 ;
        RECT 252.580 52.585 254.510 52.665 ;
        RECT 257.760 52.585 258.105 54.085 ;
        RECT 243.155 52.425 248.680 52.455 ;
        RECT 252.580 52.425 258.105 52.585 ;
        RECT 259.995 54.085 265.520 54.245 ;
        RECT 259.995 52.585 260.340 54.085 ;
        RECT 263.590 54.060 265.520 54.085 ;
        RECT 269.410 54.245 271.340 54.270 ;
        RECT 269.410 54.085 274.945 54.245 ;
        RECT 269.410 54.060 271.340 54.085 ;
        RECT 263.590 52.585 265.520 52.665 ;
        RECT 259.995 52.425 265.520 52.585 ;
        RECT 269.410 52.585 271.340 52.665 ;
        RECT 274.600 52.585 274.945 54.085 ;
        RECT 269.410 52.455 274.945 52.585 ;
        RECT 269.420 52.425 274.945 52.455 ;
      LAYER Metal2 ;
        RECT 250.310 95.975 268.400 97.400 ;
        RECT 241.710 95.675 276.390 95.975 ;
        RECT 250.310 95.655 268.400 95.675 ;
        RECT 250.310 94.205 250.825 95.655 ;
        RECT 267.275 94.205 267.790 95.655 ;
        RECT 246.760 94.005 254.510 94.205 ;
        RECT 263.590 94.005 271.340 94.205 ;
        RECT 246.760 92.400 254.510 92.600 ;
        RECT 263.590 92.400 271.340 92.600 ;
        RECT 241.710 82.360 250.825 82.660 ;
        RECT 250.310 80.890 250.825 82.360 ;
        RECT 267.275 82.360 276.390 82.660 ;
        RECT 267.275 80.890 267.790 82.360 ;
        RECT 246.760 80.690 254.510 80.890 ;
        RECT 263.590 80.690 271.340 80.890 ;
        RECT 246.760 79.085 254.510 79.285 ;
        RECT 263.590 79.085 271.340 79.285 ;
        RECT 241.710 69.045 250.825 69.345 ;
        RECT 250.310 67.575 250.825 69.045 ;
        RECT 267.275 69.045 276.390 69.345 ;
        RECT 267.275 67.575 267.790 69.045 ;
        RECT 246.760 67.375 254.510 67.575 ;
        RECT 263.590 67.375 271.340 67.575 ;
        RECT 246.760 65.770 254.510 65.970 ;
        RECT 263.590 65.770 271.340 65.970 ;
        RECT 241.710 55.730 250.825 56.030 ;
        RECT 250.310 54.265 250.825 55.730 ;
        RECT 267.275 55.730 276.390 56.030 ;
        RECT 267.275 54.265 267.790 55.730 ;
        RECT 246.760 54.065 254.510 54.265 ;
        RECT 263.590 54.065 271.340 54.265 ;
        RECT 246.760 52.460 254.510 52.660 ;
        RECT 263.590 52.460 271.340 52.660 ;
    END
  END DFT
  PIN V_BGR
    ANTENNAGATEAREA 38.967999 ;
    ANTENNADIFFAREA 4.820000 ;
    PORT
      LAYER GatPoly ;
        RECT 117.365 53.395 120.115 53.575 ;
        RECT 117.365 50.985 120.115 51.395 ;
        RECT 152.885 39.680 153.065 41.160 ;
        RECT 152.605 38.700 153.065 39.680 ;
        RECT 152.885 37.460 153.065 38.700 ;
        RECT 156.705 37.460 156.885 41.160 ;
        RECT 99.425 29.575 99.855 31.575 ;
        RECT 104.855 29.575 105.035 31.575 ;
        RECT 92.990 26.405 93.170 28.405 ;
        RECT 98.170 26.405 98.590 28.405 ;
      LAYER Metal1 ;
        RECT 136.185 90.870 136.395 91.570 ;
        RECT 142.890 90.460 143.510 91.570 ;
        RECT 128.310 89.115 128.520 89.815 ;
        RECT 142.935 57.380 143.470 90.460 ;
        RECT 246.760 80.040 248.690 80.080 ;
        RECT 243.680 79.880 248.690 80.040 ;
        RECT 246.760 79.870 248.690 79.880 ;
        RECT 250.395 78.155 250.685 80.330 ;
        RECT 252.580 80.040 254.510 80.080 ;
        RECT 252.580 79.880 257.580 80.040 ;
        RECT 252.580 79.870 254.510 79.880 ;
        RECT 250.425 77.950 250.635 78.155 ;
        RECT 238.840 70.540 239.040 70.545 ;
        RECT 238.840 70.250 239.050 70.540 ;
        RECT 117.075 56.725 118.195 56.935 ;
        RECT 117.075 55.070 117.380 56.725 ;
        RECT 142.885 56.270 143.505 57.380 ;
        RECT 117.090 55.065 117.380 55.070 ;
        RECT 117.095 53.260 117.255 53.395 ;
        RECT 117.070 52.560 117.280 53.260 ;
        RECT 117.095 51.215 117.255 52.560 ;
        RECT 117.095 51.055 119.890 51.215 ;
        RECT 142.935 40.880 143.470 56.270 ;
        RECT 142.905 38.210 143.525 40.880 ;
        RECT 152.650 38.635 152.860 39.745 ;
        RECT 238.840 38.715 239.040 70.250 ;
        RECT 238.840 38.425 239.050 38.715 ;
        RECT 258.690 38.435 258.900 38.725 ;
        RECT 99.110 38.130 143.525 38.210 ;
        RECT 99.110 37.965 143.470 38.130 ;
        RECT 99.105 30.825 99.655 31.375 ;
        RECT 99.105 30.675 99.315 30.825 ;
        RECT 99.495 29.755 99.655 30.825 ;
        RECT 240.940 31.260 241.150 31.550 ;
        RECT 258.700 31.540 258.900 38.435 ;
        RECT 99.105 28.205 99.315 28.290 ;
        RECT 98.360 27.655 99.315 28.205 ;
        RECT 98.360 26.585 98.520 27.655 ;
        RECT 99.105 27.590 99.315 27.655 ;
        RECT 154.020 1.730 157.585 9.435 ;
        RECT 240.940 7.585 241.140 31.260 ;
        RECT 258.690 31.250 258.900 31.540 ;
        RECT 240.935 7.295 241.145 7.585 ;
        RECT 257.050 7.305 257.260 7.595 ;
        RECT 153.565 1.520 157.955 1.730 ;
        RECT 257.060 1.705 257.260 7.305 ;
        RECT 154.020 1.455 157.585 1.520 ;
        RECT 255.310 1.495 257.260 1.705 ;
        RECT 257.060 1.455 257.260 1.495 ;
      LAYER Metal2 ;
        RECT 136.190 91.370 143.505 91.570 ;
        RECT 136.190 90.955 136.390 91.370 ;
        RECT 136.185 90.785 136.390 90.955 ;
        RECT 128.315 90.585 136.390 90.785 ;
        RECT 128.315 89.115 128.515 90.585 ;
        RECT 142.895 90.460 143.505 91.370 ;
        RECT 250.415 80.075 250.615 80.330 ;
        RECT 246.760 79.875 254.510 80.075 ;
        RECT 250.415 79.630 250.615 79.875 ;
        RECT 250.430 75.975 250.630 78.650 ;
        RECT 248.765 75.750 250.630 75.975 ;
        RECT 248.765 70.545 248.985 75.750 ;
        RECT 238.840 70.245 248.985 70.545 ;
        RECT 117.085 56.730 118.195 56.930 ;
        RECT 142.890 56.270 143.500 57.380 ;
        RECT 117.090 55.170 117.380 55.270 ;
        RECT 117.075 55.070 117.380 55.170 ;
        RECT 117.075 52.560 117.275 55.070 ;
        RECT 142.910 39.745 143.520 40.880 ;
        RECT 142.910 38.630 152.880 39.745 ;
        RECT 99.110 38.205 99.310 38.210 ;
        RECT 99.110 38.005 99.810 38.205 ;
        RECT 142.910 38.130 143.520 38.630 ;
        RECT 99.110 27.590 99.310 38.005 ;
        RECT 149.070 29.445 151.580 38.630 ;
        RECT 238.840 38.425 258.900 38.725 ;
        RECT 240.940 31.250 258.900 31.550 ;
        RECT 149.070 26.600 157.585 29.445 ;
        RECT 154.020 5.485 157.585 26.600 ;
        RECT 240.935 7.295 257.260 7.595 ;
        RECT 154.020 1.725 257.260 1.755 ;
        RECT 153.565 1.525 257.260 1.725 ;
        RECT 154.020 1.455 257.260 1.525 ;
      LAYER Metal3 ;
        RECT 142.890 56.935 143.500 57.380 ;
        RECT 117.075 56.705 143.500 56.935 ;
        RECT 142.890 56.270 143.500 56.705 ;
    END
  END V_BGR
  PIN VSS
    USE GROUND ;
    PORT
      LAYER GatPoly ;
        RECT 6.320 90.420 7.195 90.720 ;
        RECT 7.015 80.720 7.195 90.420 ;
        RECT 10.195 80.720 10.375 90.720 ;
        RECT 36.695 75.870 37.145 76.050 ;
        RECT 43.695 75.870 44.145 76.050 ;
        RECT 48.805 75.870 49.805 76.635 ;
        RECT 13.030 66.450 13.210 66.900 ;
        RECT 14.410 66.830 14.590 66.900 ;
        RECT 15.270 66.830 15.450 66.900 ;
        RECT 14.410 66.530 15.450 66.830 ;
        RECT 14.410 66.450 14.590 66.530 ;
        RECT 15.270 66.450 15.450 66.530 ;
        RECT 16.650 66.450 16.830 66.900 ;
        RECT 36.695 64.970 37.145 65.870 ;
        RECT 43.695 64.970 44.145 65.870 ;
        RECT 48.805 65.690 49.805 65.870 ;
        RECT 47.425 64.970 48.425 65.150 ;
        RECT 50.185 64.970 51.185 65.150 ;
        RECT 13.030 60.740 13.210 61.190 ;
        RECT 14.410 61.115 14.590 61.190 ;
        RECT 15.270 61.115 15.450 61.190 ;
        RECT 14.410 60.815 15.450 61.115 ;
        RECT 14.410 60.740 14.590 60.815 ;
        RECT 15.270 60.740 15.450 60.815 ;
        RECT 16.650 60.740 16.830 61.190 ;
        RECT 60.530 59.530 61.030 59.960 ;
        RECT 36.695 54.070 37.145 54.970 ;
        RECT 43.695 54.070 44.145 54.970 ;
        RECT 47.425 54.790 48.425 54.970 ;
        RECT 50.185 54.790 51.185 54.970 ;
        RECT 47.435 54.560 48.415 54.790 ;
        RECT 50.195 54.560 51.175 54.790 ;
        RECT 48.805 54.070 49.805 54.250 ;
        RECT 7.015 39.500 7.195 49.200 ;
        RECT 6.320 39.200 7.195 39.500 ;
        RECT 10.195 39.200 10.375 49.200 ;
        RECT 152.885 46.640 153.065 50.340 ;
        RECT 156.705 50.220 156.885 50.340 ;
        RECT 156.705 49.240 157.185 50.220 ;
        RECT 156.705 46.640 156.885 49.240 ;
        RECT 36.695 43.890 37.145 44.070 ;
        RECT 43.695 43.890 44.145 44.070 ;
        RECT 48.805 43.275 49.805 44.070 ;
        RECT 170.865 39.195 171.165 39.495 ;
        RECT 173.925 39.195 174.225 39.495 ;
        RECT 170.950 38.925 171.080 39.195 ;
        RECT 174.010 38.925 174.140 39.195 ;
        RECT 170.950 37.445 171.080 37.625 ;
        RECT 174.010 37.445 174.140 37.625 ;
        RECT 44.300 34.030 44.480 36.030 ;
        RECT 54.480 34.030 55.450 36.030 ;
        RECT 65.450 34.030 65.630 36.030 ;
        RECT 67.635 32.790 67.815 34.790 ;
        RECT 77.815 32.790 79.500 34.790 ;
        RECT 89.500 32.790 89.680 34.790 ;
        RECT 152.885 32.870 153.065 36.570 ;
        RECT 156.705 33.985 156.885 36.570 ;
        RECT 156.705 33.005 157.185 33.985 ;
        RECT 156.705 32.870 156.885 33.005 ;
        RECT 44.300 22.130 44.480 24.130 ;
        RECT 54.480 22.130 55.450 24.130 ;
        RECT 65.450 22.130 65.630 24.130 ;
        RECT 67.635 23.180 67.815 25.180 ;
        RECT 77.815 23.180 79.500 25.180 ;
        RECT 89.500 23.180 89.680 25.180 ;
        RECT 45.385 16.010 45.815 16.510 ;
      LAYER Metal1 ;
        RECT 250.960 95.325 267.140 95.625 ;
        RECT 5.675 92.030 11.715 92.330 ;
        RECT 5.675 90.650 5.975 92.030 ;
        RECT 6.390 90.830 10.195 90.990 ;
        RECT 6.390 90.650 6.550 90.830 ;
        RECT 5.675 90.490 6.550 90.650 ;
        RECT 5.675 80.610 5.975 90.490 ;
        RECT 6.390 90.440 6.550 90.490 ;
        RECT 5.675 80.450 11.170 80.610 ;
        RECT 5.675 59.850 5.975 80.450 ;
        RECT 10.965 59.850 11.170 80.450 ;
        RECT 5.675 59.690 11.170 59.850 ;
        RECT 11.415 68.190 11.715 92.030 ;
        RECT 250.960 91.225 251.260 95.325 ;
        RECT 258.900 91.225 259.200 95.325 ;
        RECT 266.840 91.225 267.140 95.325 ;
        RECT 250.960 90.925 267.140 91.225 ;
        RECT 247.855 89.290 254.325 89.505 ;
        RECT 247.855 88.390 248.465 89.290 ;
        RECT 246.065 88.090 248.765 88.390 ;
        RECT 248.465 86.360 248.765 88.090 ;
        RECT 247.110 85.930 248.765 86.360 ;
        RECT 248.465 85.150 248.765 85.930 ;
        RECT 246.065 84.850 248.765 85.150 ;
        RECT 253.755 88.255 254.325 89.290 ;
        RECT 255.840 88.255 262.260 90.925 ;
        RECT 263.775 89.290 270.245 89.505 ;
        RECT 263.775 88.255 264.345 89.290 ;
        RECT 269.635 88.390 270.245 89.290 ;
        RECT 253.755 87.955 264.345 88.255 ;
        RECT 253.755 85.285 254.055 87.955 ;
        RECT 255.075 85.285 257.075 86.285 ;
        RECT 258.095 85.285 260.005 87.955 ;
        RECT 261.025 85.285 263.025 86.285 ;
        RECT 264.045 85.285 264.345 87.955 ;
        RECT 253.755 84.985 264.345 85.285 ;
        RECT 269.335 88.090 272.035 88.390 ;
        RECT 269.335 86.360 269.635 88.090 ;
        RECT 269.335 85.930 270.990 86.360 ;
        RECT 269.335 85.150 269.635 85.930 ;
        RECT 255.840 82.310 262.260 84.985 ;
        RECT 269.335 84.850 272.035 85.150 ;
        RECT 250.960 82.010 267.140 82.310 ;
        RECT 53.030 77.650 61.930 77.950 ;
        RECT 35.285 76.890 45.555 77.190 ;
        RECT 11.415 67.890 18.285 68.190 ;
        RECT 11.415 59.790 11.715 67.890 ;
        RECT 12.085 65.500 12.385 67.890 ;
        RECT 14.860 67.170 15.020 67.890 ;
        RECT 13.210 67.010 16.650 67.170 ;
        RECT 14.860 66.340 15.020 67.010 ;
        RECT 13.210 66.180 16.650 66.340 ;
        RECT 12.085 65.340 16.650 65.500 ;
        RECT 12.085 62.300 12.385 65.340 ;
        RECT 12.085 62.140 16.650 62.300 ;
        RECT 12.085 59.790 12.385 62.140 ;
        RECT 13.210 61.300 16.650 61.460 ;
        RECT 14.760 60.630 14.920 61.300 ;
        RECT 13.210 60.470 16.650 60.630 ;
        RECT 14.760 59.790 14.920 60.470 ;
        RECT 17.985 59.790 18.285 67.890 ;
        RECT 5.675 39.430 5.975 59.690 ;
        RECT 11.415 59.490 18.285 59.790 ;
        RECT 11.415 59.120 11.715 59.490 ;
        RECT 11.415 58.820 16.325 59.120 ;
        RECT 11.415 54.240 11.715 58.820 ;
        RECT 12.085 56.600 12.385 58.820 ;
        RECT 12.085 56.440 14.805 56.600 ;
        RECT 12.085 54.240 12.385 56.440 ;
        RECT 11.415 54.080 14.805 54.240 ;
        RECT 11.415 47.610 11.715 54.080 ;
        RECT 12.085 51.860 12.385 54.080 ;
        RECT 16.025 51.860 16.325 58.820 ;
        RECT 12.085 51.560 16.325 51.860 ;
        RECT 11.415 47.310 15.755 47.610 ;
        RECT 11.415 45.705 11.715 47.310 ;
        RECT 12.085 45.705 12.385 47.310 ;
        RECT 13.425 45.705 13.585 46.090 ;
        RECT 11.415 45.435 13.585 45.705 ;
        RECT 11.415 43.820 11.715 45.435 ;
        RECT 12.085 43.820 12.385 45.435 ;
        RECT 13.425 45.040 13.585 45.435 ;
        RECT 15.455 43.820 15.755 47.310 ;
        RECT 11.415 43.520 15.755 43.820 ;
        RECT 11.415 42.040 11.715 43.520 ;
        RECT 35.285 43.050 35.585 76.890 ;
        RECT 36.425 44.070 37.415 75.870 ;
        RECT 40.055 54.970 40.785 64.970 ;
        RECT 43.425 44.070 44.415 75.870 ;
        RECT 45.255 43.050 45.555 76.890 ;
        RECT 46.015 76.890 52.595 77.190 ;
        RECT 46.015 64.970 46.315 76.890 ;
        RECT 48.835 76.405 49.775 76.890 ;
        RECT 46.015 54.970 48.210 64.970 ;
        RECT 49.915 64.700 50.075 64.970 ;
        RECT 51.295 64.700 51.455 64.970 ;
        RECT 52.295 64.700 52.595 76.890 ;
        RECT 49.915 54.970 52.595 64.700 ;
        RECT 46.015 43.050 46.315 54.970 ;
        RECT 47.455 54.790 48.210 54.970 ;
        RECT 47.455 54.630 48.395 54.790 ;
        RECT 50.185 54.630 51.175 54.970 ;
        RECT 48.835 43.050 49.775 43.505 ;
        RECT 52.295 43.050 52.595 54.970 ;
        RECT 53.030 43.050 53.330 77.650 ;
        RECT 61.630 59.940 61.930 77.650 ;
        RECT 250.960 77.910 251.260 82.010 ;
        RECT 258.900 77.910 259.200 82.010 ;
        RECT 266.840 77.910 267.140 82.010 ;
        RECT 250.960 77.610 267.140 77.910 ;
        RECT 247.855 75.975 254.325 76.190 ;
        RECT 247.855 75.075 248.465 75.975 ;
        RECT 246.065 74.775 248.765 75.075 ;
        RECT 248.465 73.045 248.765 74.775 ;
        RECT 247.110 72.615 248.765 73.045 ;
        RECT 248.465 71.835 248.765 72.615 ;
        RECT 246.065 71.535 248.765 71.835 ;
        RECT 253.755 74.940 254.325 75.975 ;
        RECT 255.840 74.940 262.260 77.610 ;
        RECT 263.775 75.975 270.245 76.190 ;
        RECT 263.775 74.940 264.345 75.975 ;
        RECT 269.635 75.075 270.245 75.975 ;
        RECT 253.755 74.640 264.345 74.940 ;
        RECT 253.755 71.970 254.055 74.640 ;
        RECT 255.075 71.970 257.075 72.970 ;
        RECT 258.095 71.970 260.005 74.640 ;
        RECT 261.025 71.970 263.025 72.970 ;
        RECT 264.045 71.970 264.345 74.640 ;
        RECT 253.755 71.670 264.345 71.970 ;
        RECT 269.335 74.775 272.035 75.075 ;
        RECT 269.335 73.045 269.635 74.775 ;
        RECT 269.335 72.615 270.990 73.045 ;
        RECT 269.335 71.835 269.635 72.615 ;
        RECT 255.840 68.995 262.260 71.670 ;
        RECT 269.335 71.535 272.035 71.835 ;
        RECT 250.960 68.695 267.140 68.995 ;
        RECT 250.960 64.595 251.260 68.695 ;
        RECT 258.900 64.595 259.200 68.695 ;
        RECT 266.840 64.595 267.140 68.695 ;
        RECT 250.960 64.295 267.140 64.595 ;
        RECT 247.855 62.660 254.325 62.875 ;
        RECT 247.855 61.760 248.465 62.660 ;
        RECT 246.065 61.460 248.765 61.760 ;
        RECT 60.550 59.680 61.930 59.940 ;
        RECT 248.465 59.730 248.765 61.460 ;
        RECT 61.630 43.050 61.930 59.680 ;
        RECT 247.110 59.300 248.765 59.730 ;
        RECT 248.465 58.520 248.765 59.300 ;
        RECT 246.065 58.220 248.765 58.520 ;
        RECT 253.755 61.625 254.325 62.660 ;
        RECT 255.840 61.625 262.260 64.295 ;
        RECT 263.775 62.660 270.245 62.875 ;
        RECT 263.775 61.625 264.345 62.660 ;
        RECT 269.635 61.760 270.245 62.660 ;
        RECT 253.755 61.325 264.345 61.625 ;
        RECT 253.755 58.655 254.055 61.325 ;
        RECT 255.075 58.655 257.075 59.655 ;
        RECT 258.095 58.655 260.005 61.325 ;
        RECT 261.025 58.655 263.025 59.655 ;
        RECT 264.045 58.655 264.345 61.325 ;
        RECT 253.755 58.355 264.345 58.655 ;
        RECT 269.335 61.460 272.035 61.760 ;
        RECT 269.335 59.730 269.635 61.460 ;
        RECT 269.335 59.300 270.990 59.730 ;
        RECT 269.335 58.520 269.635 59.300 ;
        RECT 255.840 55.685 262.260 58.355 ;
        RECT 269.335 58.220 272.035 58.520 ;
        RECT 250.960 55.385 267.140 55.685 ;
        RECT 35.285 42.750 61.930 43.050 ;
        RECT 151.885 51.305 157.885 51.605 ;
        RECT 11.415 41.740 14.895 42.040 ;
        RECT 11.415 40.630 11.715 41.740 ;
        RECT 12.085 40.630 12.385 41.740 ;
        RECT 13.155 40.630 13.315 40.860 ;
        RECT 11.415 40.350 13.315 40.630 ;
        RECT 6.390 39.430 6.550 39.480 ;
        RECT 5.675 39.270 6.550 39.430 ;
        RECT 5.675 37.930 5.975 39.270 ;
        RECT 6.390 39.090 6.550 39.270 ;
        RECT 11.415 39.240 11.715 40.350 ;
        RECT 12.085 39.240 12.385 40.350 ;
        RECT 13.155 40.120 13.315 40.350 ;
        RECT 14.595 39.240 14.895 41.740 ;
        RECT 6.390 38.930 10.195 39.090 ;
        RECT 11.415 38.940 14.895 39.240 ;
        RECT 11.415 37.930 11.715 38.940 ;
        RECT 5.645 8.320 11.745 37.930 ;
        RECT 43.470 37.340 52.515 42.750 ;
        RECT 43.315 35.990 66.615 37.340 ;
        RECT 90.585 35.990 91.205 36.480 ;
        RECT 43.315 35.690 91.205 35.990 ;
        RECT 43.315 35.140 66.955 35.690 ;
        RECT 90.355 35.140 91.205 35.690 ;
        RECT 43.315 34.960 91.205 35.140 ;
        RECT 43.315 33.760 90.655 34.960 ;
        RECT 151.885 34.905 152.185 51.305 ;
        RECT 152.885 46.370 157.140 51.305 ;
        RECT 43.315 24.400 43.615 33.760 ;
        RECT 55.110 29.160 55.270 33.760 ;
        RECT 66.315 32.420 90.655 33.760 ;
        RECT 66.315 29.460 66.955 32.420 ;
        RECT 90.355 29.460 90.655 32.420 ;
        RECT 44.480 29.000 65.450 29.160 ;
        RECT 55.110 24.400 55.270 29.000 ;
        RECT 66.315 28.510 90.655 29.460 ;
        RECT 66.315 25.465 66.955 28.510 ;
        RECT 90.355 25.465 90.655 28.510 ;
        RECT 66.315 24.400 90.655 25.465 ;
        RECT 43.315 22.745 90.655 24.400 ;
        RECT 43.315 22.290 66.955 22.745 ;
        RECT 90.355 22.290 90.655 22.745 ;
        RECT 43.315 21.990 90.655 22.290 ;
        RECT 149.065 31.905 152.185 34.905 ;
        RECT 152.885 34.050 157.135 36.840 ;
        RECT 157.585 36.805 157.885 51.305 ;
        RECT 250.960 51.285 251.260 55.385 ;
        RECT 258.900 51.285 259.200 55.385 ;
        RECT 266.840 51.285 267.140 55.385 ;
        RECT 250.960 50.985 267.140 51.285 ;
        RECT 247.855 49.350 254.325 49.565 ;
        RECT 176.475 49.035 181.475 49.335 ;
        RECT 176.475 41.635 176.775 49.035 ;
        RECT 181.175 48.185 181.475 49.035 ;
        RECT 247.855 48.450 248.465 49.350 ;
        RECT 180.110 42.885 181.475 48.185 ;
        RECT 246.065 48.150 248.765 48.450 ;
        RECT 248.465 46.420 248.765 48.150 ;
        RECT 247.110 45.990 248.765 46.420 ;
        RECT 248.465 45.210 248.765 45.990 ;
        RECT 246.065 44.910 248.765 45.210 ;
        RECT 253.755 48.315 254.325 49.350 ;
        RECT 255.840 48.315 262.260 50.985 ;
        RECT 263.775 49.350 270.245 49.565 ;
        RECT 263.775 48.315 264.345 49.350 ;
        RECT 269.635 48.450 270.245 49.350 ;
        RECT 253.755 48.015 264.345 48.315 ;
        RECT 253.755 45.345 254.055 48.015 ;
        RECT 255.075 45.345 257.075 46.345 ;
        RECT 258.095 45.345 260.005 48.015 ;
        RECT 261.025 45.345 263.025 46.345 ;
        RECT 264.045 45.345 264.345 48.015 ;
        RECT 253.755 45.045 264.345 45.345 ;
        RECT 269.335 48.150 272.035 48.450 ;
        RECT 269.335 46.420 269.635 48.150 ;
        RECT 269.335 45.990 270.990 46.420 ;
        RECT 269.335 45.210 269.635 45.990 ;
        RECT 181.175 41.635 181.475 42.885 ;
        RECT 176.475 41.335 181.475 41.635 ;
        RECT 179.895 40.505 180.200 41.335 ;
        RECT 170.075 40.205 180.200 40.505 ;
        RECT 170.075 39.425 170.375 40.205 ;
        RECT 174.775 39.425 175.075 40.205 ;
        RECT 163.965 39.190 166.715 39.215 ;
        RECT 163.845 39.030 166.795 39.190 ;
        RECT 163.965 39.005 166.715 39.030 ;
        RECT 170.075 38.925 171.350 39.425 ;
        RECT 170.075 37.625 172.070 38.925 ;
        RECT 170.075 37.445 171.350 37.625 ;
        RECT 173.740 37.445 175.075 39.425 ;
        RECT 170.075 36.805 170.375 37.445 ;
        RECT 174.775 36.805 175.075 37.445 ;
        RECT 157.585 36.505 175.075 36.805 ;
        RECT 175.680 38.890 175.980 40.205 ;
        RECT 175.680 38.180 176.455 38.890 ;
        RECT 175.680 36.805 175.980 38.180 ;
        RECT 177.380 36.805 177.680 40.205 ;
        RECT 175.680 36.505 177.680 36.805 ;
        RECT 178.200 38.560 178.500 40.205 ;
        RECT 178.200 38.040 179.040 38.560 ;
        RECT 179.900 38.095 180.200 40.205 ;
        RECT 180.665 38.790 186.665 39.090 ;
        RECT 180.665 38.095 180.965 38.790 ;
        RECT 178.200 36.805 178.500 38.040 ;
        RECT 179.900 37.935 180.965 38.095 ;
        RECT 179.900 36.805 180.200 37.935 ;
        RECT 180.665 37.390 180.965 37.935 ;
        RECT 186.365 37.390 186.665 38.790 ;
        RECT 180.665 37.090 186.665 37.390 ;
        RECT 178.200 36.505 180.200 36.805 ;
        RECT 152.885 32.940 157.140 34.050 ;
        RECT 152.885 31.905 157.135 32.940 ;
        RECT 157.585 31.905 157.885 36.505 ;
        RECT 163.930 34.765 165.450 36.505 ;
        RECT 149.065 31.605 157.885 31.905 ;
        RECT 43.315 20.820 66.615 21.990 ;
        RECT 43.315 18.840 44.450 20.820 ;
        RECT 61.710 18.865 141.590 19.165 ;
        RECT 43.315 18.540 57.315 18.840 ;
        RECT 43.315 16.490 43.615 18.540 ;
        RECT 43.315 16.030 45.665 16.490 ;
        RECT 43.315 11.340 43.615 16.030 ;
        RECT 57.015 11.340 57.315 18.540 ;
        RECT 43.315 11.040 57.315 11.340 ;
        RECT 61.710 18.445 62.335 18.865 ;
        RECT 61.710 10.915 62.010 18.445 ;
        RECT 141.290 10.915 141.590 18.865 ;
        RECT 61.710 10.615 141.590 10.915 ;
        RECT 5.370 5.650 11.900 8.320 ;
        RECT 149.065 8.315 152.185 31.605 ;
        RECT 245.365 28.665 245.985 36.760 ;
        RECT 253.755 35.750 254.740 45.045 ;
        RECT 269.335 44.910 272.035 45.210 ;
        RECT 244.195 23.825 244.455 24.815 ;
        RECT 245.710 23.825 245.920 23.830 ;
        RECT 243.865 23.385 245.920 23.825 ;
        RECT 245.710 23.130 245.920 23.385 ;
        RECT 245.710 20.850 245.920 21.250 ;
        RECT 254.615 20.850 254.880 21.840 ;
        RECT 260.890 20.850 261.155 21.840 ;
        RECT 267.165 20.850 267.430 21.840 ;
        RECT 273.440 20.850 273.705 21.840 ;
        RECT 245.710 20.550 274.730 20.850 ;
        RECT 279.925 20.790 280.385 96.515 ;
        RECT 252.065 20.050 274.730 20.550 ;
        RECT 279.765 20.090 280.385 20.790 ;
        RECT 244.195 18.740 244.455 19.730 ;
        RECT 254.615 19.060 254.880 20.050 ;
        RECT 260.890 19.060 261.155 20.050 ;
        RECT 267.165 19.060 267.430 20.050 ;
        RECT 273.440 19.060 273.705 20.050 ;
        RECT 245.710 18.740 245.920 18.855 ;
        RECT 243.865 18.300 245.920 18.740 ;
        RECT 245.710 18.155 245.920 18.300 ;
        RECT 244.195 13.610 244.455 14.600 ;
        RECT 245.710 13.610 245.920 13.860 ;
        RECT 243.865 13.170 245.920 13.610 ;
        RECT 245.710 13.160 245.920 13.170 ;
        RECT 279.925 8.970 280.385 20.090 ;
        RECT 5.645 5.485 11.745 5.650 ;
        RECT 149.025 5.645 152.195 8.315 ;
        RECT 149.065 5.485 152.185 5.645 ;
        RECT 279.880 4.990 280.500 8.970 ;
        RECT 279.925 4.575 280.385 4.990 ;
      LAYER Metal2 ;
        RECT 35.285 72.630 37.210 75.790 ;
        RECT 43.655 72.630 45.580 75.790 ;
        RECT 40.125 43.005 40.735 56.215 ;
        RECT 156.935 49.175 157.135 50.285 ;
        RECT 40.075 42.805 40.775 43.005 ;
        RECT 40.125 42.750 40.735 42.805 ;
        RECT 157.585 39.005 166.715 39.215 ;
        RECT 90.590 34.960 91.200 36.480 ;
        RECT 245.370 36.060 254.740 36.760 ;
        RECT 163.930 34.770 165.450 34.970 ;
        RECT 78.345 33.065 78.955 34.585 ;
        RECT 156.935 32.940 157.135 34.050 ;
        RECT 245.370 28.665 245.980 29.365 ;
        RECT 78.345 23.390 78.955 24.910 ;
        RECT 61.720 18.445 62.330 21.555 ;
        RECT 245.715 13.160 245.915 28.665 ;
        RECT 274.075 20.090 280.385 20.790 ;
        RECT 48.865 8.405 54.895 11.280 ;
        RECT 66.975 8.405 73.005 10.845 ;
        RECT 99.315 8.405 105.345 10.845 ;
        RECT 126.475 8.405 132.505 10.845 ;
        RECT 5.370 5.655 11.900 8.315 ;
        RECT 48.820 5.745 54.895 8.405 ;
        RECT 66.930 5.745 73.005 8.405 ;
        RECT 99.270 5.745 105.345 8.405 ;
        RECT 126.430 5.745 132.505 8.405 ;
        RECT 48.865 5.485 54.895 5.745 ;
        RECT 66.975 5.485 73.005 5.745 ;
        RECT 99.315 5.485 105.345 5.745 ;
        RECT 126.475 5.485 132.505 5.745 ;
        RECT 137.065 8.310 152.185 8.485 ;
        RECT 137.065 5.650 152.195 8.310 ;
        RECT 137.065 5.485 152.185 5.650 ;
        RECT 279.885 4.990 280.495 8.970 ;
      LAYER Metal3 ;
        RECT 36.600 72.630 37.210 75.790 ;
        RECT 43.655 72.630 44.265 75.790 ;
        RECT 90.590 34.960 91.200 36.480 ;
        RECT 163.930 34.770 165.450 34.970 ;
        RECT 5.370 5.655 11.900 8.315 ;
        RECT 48.820 5.745 54.870 8.405 ;
        RECT 66.930 5.745 72.980 8.405 ;
        RECT 99.270 5.745 105.320 8.405 ;
        RECT 126.430 5.745 132.480 8.405 ;
        RECT 137.155 5.650 140.325 8.310 ;
        RECT 279.885 4.990 280.495 8.970 ;
      LAYER Metal4 ;
        RECT 36.600 72.630 37.210 75.790 ;
        RECT 43.655 72.630 44.265 75.790 ;
        RECT 90.590 34.960 91.200 36.480 ;
        RECT 163.930 34.770 165.450 34.970 ;
        RECT 279.885 8.485 280.495 8.970 ;
        RECT 5.645 8.315 280.495 8.485 ;
        RECT 5.370 5.655 280.495 8.315 ;
        RECT 5.645 5.485 280.495 5.655 ;
        RECT 279.885 4.990 280.495 5.485 ;
      LAYER Metal5 ;
        RECT 34.860 69.380 46.060 77.210 ;
        RECT 90.585 34.960 91.205 36.480 ;
        RECT 160.445 19.875 188.625 35.185 ;
        RECT 189.925 19.875 232.645 49.725 ;
        RECT 160.445 17.080 232.645 19.875 ;
        RECT 160.445 7.005 188.625 17.080 ;
        RECT 189.925 7.005 232.645 17.080 ;
      LAYER TopMetal1 ;
        RECT 90.075 36.535 91.715 36.540 ;
        RECT 95.635 36.535 139.735 37.020 ;
        RECT 90.075 34.900 139.735 36.535 ;
        RECT 90.285 34.895 139.735 34.900 ;
        RECT 95.635 10.560 139.735 34.895 ;
    END
  END VSS
  PIN IOVDD
    ANTENNAGATEAREA 747.000000 ;
    ANTENNADIFFAREA 681.832764 ;
    PORT
      LAYER GatPoly ;
        RECT 50.545 91.465 51.545 91.645 ;
        RECT 58.855 91.465 59.855 91.645 ;
        RECT 81.290 91.465 83.290 91.645 ;
        RECT 83.670 91.465 85.670 91.645 ;
        RECT 97.950 91.465 99.950 91.645 ;
        RECT 100.330 91.465 102.330 91.645 ;
        RECT 124.100 91.475 127.100 91.655 ;
        RECT 137.600 91.475 140.600 91.655 ;
        RECT 36.920 90.590 37.920 90.770 ;
        RECT 42.920 90.590 43.920 90.770 ;
        RECT 14.555 90.390 16.055 90.570 ;
        RECT 29.595 90.390 31.095 90.570 ;
        RECT 124.100 89.735 127.100 90.975 ;
        RECT 137.600 89.735 140.600 90.975 ;
        RECT 14.555 88.210 16.055 88.390 ;
        RECT 29.595 88.210 31.095 88.390 ;
        RECT 14.890 87.770 15.190 88.210 ;
        RECT 30.460 87.770 30.760 88.210 ;
        RECT 124.100 87.995 127.100 89.235 ;
        RECT 137.600 87.995 140.600 89.235 ;
        RECT 124.100 87.315 127.100 87.495 ;
        RECT 137.600 87.315 140.600 87.495 ;
        RECT 15.230 84.610 15.530 84.910 ;
        RECT 15.300 83.750 15.455 84.610 ;
        RECT 36.920 84.490 37.920 85.590 ;
        RECT 42.920 84.490 43.920 85.590 ;
        RECT 50.545 85.295 51.545 86.465 ;
        RECT 58.855 85.295 59.855 86.465 ;
        RECT 125.600 84.200 126.600 84.380 ;
        RECT 128.100 84.200 129.100 84.380 ;
        RECT 135.600 84.200 136.600 84.380 ;
        RECT 138.100 84.200 139.100 84.380 ;
        RECT 14.880 83.570 15.880 83.750 ;
        RECT 23.640 83.570 24.640 83.750 ;
        RECT 81.290 81.285 83.290 81.465 ;
        RECT 83.670 81.285 85.670 81.465 ;
        RECT 81.290 80.660 85.670 81.285 ;
        RECT 97.950 81.285 99.950 81.465 ;
        RECT 100.330 81.285 102.330 81.465 ;
        RECT 97.950 80.660 102.330 81.285 ;
        RECT 125.600 80.960 126.600 82.200 ;
        RECT 128.100 80.960 129.100 82.200 ;
        RECT 135.600 80.960 136.600 82.200 ;
        RECT 138.100 80.960 139.100 82.200 ;
        RECT 50.545 80.115 51.545 80.295 ;
        RECT 58.855 80.115 59.855 80.295 ;
        RECT 36.920 79.310 37.920 79.490 ;
        RECT 42.920 79.310 43.920 79.490 ;
        RECT 14.880 78.890 15.880 79.070 ;
        RECT 23.640 78.890 24.640 79.070 ;
        RECT 23.980 76.185 24.280 78.890 ;
        RECT 125.600 78.780 126.600 78.960 ;
        RECT 128.100 78.780 129.100 78.960 ;
        RECT 135.600 78.780 136.600 78.960 ;
        RECT 138.100 78.780 139.100 78.960 ;
        RECT 71.885 78.580 76.885 78.760 ;
        RECT 78.855 78.580 83.855 78.760 ;
        RECT 99.765 78.580 104.765 78.760 ;
        RECT 106.735 78.580 111.735 78.760 ;
        RECT 125.600 77.720 126.600 77.900 ;
        RECT 128.100 77.720 129.100 77.900 ;
        RECT 130.600 77.720 131.600 77.900 ;
        RECT 133.100 77.720 134.100 77.900 ;
        RECT 135.600 77.720 136.600 77.900 ;
        RECT 138.100 77.720 139.100 77.900 ;
        RECT 14.880 76.005 15.880 76.185 ;
        RECT 23.640 76.005 24.640 76.185 ;
        RECT 125.600 75.540 126.600 75.720 ;
        RECT 128.100 75.540 129.100 75.720 ;
        RECT 130.600 75.540 131.600 75.720 ;
        RECT 133.100 75.540 134.100 75.720 ;
        RECT 135.600 75.540 136.600 75.720 ;
        RECT 138.100 75.540 139.100 75.720 ;
        RECT 125.760 74.940 126.400 75.540 ;
        RECT 128.260 74.940 128.900 75.540 ;
        RECT 130.600 75.180 134.100 75.540 ;
        RECT 131.540 74.900 133.200 75.180 ;
        RECT 135.830 74.940 136.470 75.540 ;
        RECT 138.260 74.940 138.900 75.540 ;
        RECT 14.880 71.325 15.880 71.505 ;
        RECT 23.640 71.325 24.640 71.505 ;
        RECT 15.230 70.165 15.530 71.325 ;
        RECT 71.885 67.340 76.885 68.580 ;
        RECT 78.855 67.340 83.855 68.580 ;
        RECT 99.765 67.340 104.765 68.580 ;
        RECT 106.735 67.340 111.735 68.580 ;
        RECT 20.605 66.075 20.785 66.410 ;
        RECT 20.165 65.775 20.785 66.075 ;
        RECT 20.605 64.910 20.785 65.775 ;
        RECT 22.785 64.910 22.965 66.410 ;
        RECT 71.885 57.160 76.885 57.340 ;
        RECT 78.855 57.160 83.855 57.340 ;
        RECT 99.765 57.160 104.765 57.340 ;
        RECT 106.735 57.160 111.735 57.340 ;
        RECT 20.605 52.385 20.785 53.250 ;
        RECT 20.165 52.085 20.785 52.385 ;
        RECT 20.605 51.750 20.785 52.085 ;
        RECT 22.785 51.750 22.965 53.250 ;
        RECT 92.990 32.795 93.170 34.795 ;
        RECT 98.170 32.795 99.855 34.795 ;
        RECT 104.855 32.795 105.035 34.795 ;
        RECT 107.670 33.940 107.850 35.940 ;
        RECT 117.850 33.940 119.090 35.940 ;
        RECT 129.090 33.940 130.330 35.940 ;
        RECT 140.330 33.940 140.510 35.940 ;
        RECT 92.990 23.185 93.170 25.185 ;
        RECT 98.170 23.185 99.855 25.185 ;
        RECT 104.855 23.185 105.035 25.185 ;
        RECT 107.670 22.040 107.850 24.040 ;
        RECT 117.850 22.040 119.090 24.040 ;
        RECT 129.090 22.040 130.330 24.040 ;
        RECT 140.330 22.040 140.510 24.040 ;
      LAYER Metal1 ;
        RECT 237.535 96.465 237.995 96.515 ;
        RECT 44.025 93.715 48.635 96.385 ;
        RECT 84.095 93.715 88.705 96.385 ;
        RECT 105.760 93.715 110.370 96.385 ;
        RECT 127.370 96.255 237.995 96.465 ;
        RECT 23.725 92.010 24.025 93.275 ;
        RECT 44.235 92.885 48.440 93.715 ;
        RECT 84.305 92.885 88.510 93.715 ;
        RECT 105.970 92.885 110.175 93.715 ;
        RECT 126.810 93.585 237.995 96.255 ;
        RECT 127.370 93.465 237.995 93.585 ;
        RECT 127.370 92.885 136.235 93.465 ;
        RECT 35.160 92.585 61.615 92.885 ;
        RECT 35.160 92.010 51.815 92.585 ;
        RECT 12.595 91.710 51.815 92.010 ;
        RECT 12.595 87.070 12.895 91.710 ;
        RECT 23.725 91.425 24.025 91.710 ;
        RECT 18.045 91.255 29.485 91.425 ;
        RECT 14.285 88.000 14.445 90.390 ;
        RECT 18.045 88.390 18.205 91.255 ;
        RECT 21.805 88.390 21.965 91.255 ;
        RECT 25.565 88.390 25.725 91.255 ;
        RECT 29.325 88.390 29.485 91.255 ;
        RECT 31.205 88.000 31.365 90.390 ;
        RECT 14.285 87.840 15.170 88.000 ;
        RECT 30.480 87.840 31.365 88.000 ;
        RECT 14.285 87.070 14.445 87.840 ;
        RECT 31.205 87.070 31.365 87.840 ;
        RECT 32.755 87.070 33.055 91.710 ;
        RECT 12.595 86.770 33.055 87.070 ;
        RECT 12.595 86.070 12.895 86.770 ;
        RECT 19.725 86.070 20.025 86.770 ;
        RECT 26.795 86.075 27.095 86.770 ;
        RECT 26.795 86.070 32.680 86.075 ;
        RECT 12.595 85.775 32.680 86.070 ;
        RECT 12.595 85.770 29.120 85.775 ;
        RECT 12.595 69.370 12.895 85.770 ;
        RECT 15.250 84.840 15.510 85.770 ;
        RECT 14.610 84.680 16.150 84.840 ;
        RECT 14.610 79.070 14.770 84.680 ;
        RECT 15.990 79.070 16.150 84.680 ;
        RECT 23.370 77.650 23.530 83.570 ;
        RECT 24.750 77.650 24.910 83.570 ;
        RECT 26.795 77.650 29.120 85.770 ;
        RECT 23.370 77.490 29.120 77.650 ;
        RECT 14.610 70.395 14.770 76.005 ;
        RECT 15.990 70.395 16.150 76.005 ;
        RECT 23.370 71.505 23.530 77.490 ;
        RECT 24.750 71.505 24.910 77.490 ;
        RECT 26.795 74.155 29.120 77.490 ;
        RECT 32.380 74.155 32.680 85.775 ;
        RECT 35.160 78.370 38.810 91.710 ;
        RECT 42.030 78.370 45.680 91.710 ;
        RECT 48.785 79.525 51.815 91.710 ;
        RECT 48.785 79.175 49.085 79.525 ;
        RECT 55.120 79.175 55.280 92.585 ;
        RECT 58.585 79.175 61.615 92.585 ;
        RECT 79.530 92.585 144.755 92.885 ;
        RECT 79.530 91.645 95.460 92.585 ;
        RECT 79.530 80.345 85.940 91.645 ;
        RECT 90.540 81.465 90.700 91.645 ;
        RECT 95.300 81.465 95.460 91.645 ;
        RECT 98.235 80.345 104.090 92.585 ;
        RECT 122.340 86.365 127.370 92.585 ;
        RECT 131.870 91.475 132.830 92.585 ;
        RECT 137.330 92.235 144.755 92.585 ;
        RECT 131.710 90.975 132.990 91.475 ;
        RECT 131.870 89.735 132.830 90.975 ;
        RECT 131.710 89.235 132.990 89.735 ;
        RECT 131.870 87.995 132.830 89.235 ;
        RECT 131.710 87.495 132.990 87.995 ;
        RECT 131.870 86.365 132.830 87.495 ;
        RECT 137.330 86.365 142.360 92.235 ;
        RECT 122.340 86.065 142.360 86.365 ;
        RECT 123.990 85.625 124.370 86.065 ;
        RECT 126.115 85.625 126.420 86.065 ;
        RECT 128.395 85.625 128.780 86.065 ;
        RECT 79.530 80.000 104.090 80.345 ;
        RECT 123.830 85.620 129.370 85.625 ;
        RECT 133.865 85.620 134.375 86.065 ;
        RECT 137.175 85.625 137.830 86.065 ;
        RECT 140.210 85.625 140.870 86.065 ;
        RECT 135.330 85.620 140.870 85.625 ;
        RECT 123.830 85.320 140.870 85.620 ;
        RECT 48.785 78.875 61.615 79.175 ;
        RECT 69.775 79.700 113.845 80.000 ;
        RECT 35.160 78.070 45.680 78.370 ;
        RECT 26.795 73.855 32.680 74.155 ;
        RECT 14.610 70.235 16.150 70.395 ;
        RECT 15.250 69.370 15.510 70.235 ;
        RECT 26.795 69.370 27.095 73.855 ;
        RECT 12.595 69.070 27.095 69.370 ;
        RECT 19.165 68.370 19.465 69.070 ;
        RECT 24.105 68.370 24.405 69.070 ;
        RECT 19.165 68.070 24.405 68.370 ;
        RECT 19.165 66.680 19.465 68.070 ;
        RECT 19.165 66.520 22.785 66.680 ;
        RECT 19.165 51.640 19.465 66.520 ;
        RECT 20.235 64.800 20.395 66.520 ;
        RECT 20.235 64.640 22.785 64.800 ;
        RECT 24.105 61.040 24.405 68.070 ;
        RECT 20.785 60.880 24.405 61.040 ;
        RECT 24.105 57.280 24.405 60.880 ;
        RECT 20.785 57.120 24.405 57.280 ;
        RECT 20.235 53.360 22.785 53.520 ;
        RECT 20.235 51.640 20.395 53.360 ;
        RECT 19.165 51.480 22.785 51.640 ;
        RECT 19.165 50.090 19.465 51.480 ;
        RECT 24.105 50.090 24.405 57.120 ;
        RECT 69.775 56.220 84.125 79.700 ;
        RECT 99.495 56.220 113.845 79.700 ;
        RECT 123.830 74.600 129.370 85.320 ;
        RECT 131.870 84.200 132.830 85.320 ;
        RECT 131.710 82.200 132.990 84.200 ;
        RECT 131.870 80.960 132.830 82.200 ;
        RECT 131.710 78.960 132.990 80.960 ;
        RECT 131.560 74.600 133.180 75.470 ;
        RECT 135.330 74.600 140.870 85.320 ;
        RECT 123.830 74.300 140.870 74.600 ;
        RECT 69.775 55.920 113.845 56.220 ;
        RECT 19.165 49.790 24.405 50.090 ;
        RECT 106.590 36.490 141.590 37.700 ;
        RECT 91.740 36.190 141.590 36.490 ;
        RECT 143.790 36.190 144.755 92.235 ;
        RECT 91.740 33.670 144.755 36.190 ;
        RECT 91.740 32.525 107.670 33.670 ;
        RECT 91.740 25.455 92.040 32.525 ;
        RECT 105.940 29.070 107.670 32.525 ;
        RECT 116.115 29.070 117.635 29.095 ;
        RECT 119.300 29.070 120.820 29.095 ;
        RECT 129.990 29.070 130.150 33.670 ;
        RECT 141.290 32.035 144.755 33.670 ;
        RECT 105.940 28.910 117.850 29.070 ;
        RECT 119.090 28.910 140.330 29.070 ;
        RECT 105.940 25.455 107.670 28.910 ;
        RECT 116.115 28.885 117.635 28.910 ;
        RECT 119.300 28.885 120.820 28.910 ;
        RECT 91.740 24.310 107.670 25.455 ;
        RECT 129.990 24.310 130.150 28.910 ;
        RECT 141.290 24.310 141.590 32.035 ;
        RECT 91.740 21.490 141.590 24.310 ;
        RECT 106.590 20.280 141.590 21.490 ;
        RECT 140.255 17.875 140.875 18.430 ;
        RECT 62.930 17.730 140.875 17.875 ;
        RECT 62.930 17.715 140.710 17.730 ;
        RECT 140.550 16.215 140.710 17.715 ;
        RECT 62.930 16.055 140.710 16.215 ;
        RECT 140.550 14.555 140.710 16.055 ;
        RECT 62.930 14.395 140.710 14.555 ;
        RECT 140.550 12.895 140.710 14.395 ;
        RECT 62.930 12.735 140.710 12.895 ;
        RECT 237.535 4.915 237.995 93.465 ;
        RECT 242.260 96.025 275.840 96.730 ;
        RECT 242.260 95.675 245.090 96.025 ;
        RECT 273.060 95.675 275.840 96.025 ;
        RECT 242.260 95.375 250.100 95.675 ;
        RECT 242.260 91.175 242.560 95.375 ;
        RECT 249.800 91.175 250.100 95.375 ;
        RECT 268.000 95.375 275.840 95.675 ;
        RECT 263.590 93.355 265.520 93.395 ;
        RECT 260.520 93.195 265.520 93.355 ;
        RECT 263.590 93.185 265.520 93.195 ;
        RECT 267.415 91.470 267.705 93.645 ;
        RECT 267.465 91.265 267.675 91.470 ;
        RECT 242.260 90.875 250.100 91.175 ;
        RECT 268.000 91.175 268.300 95.375 ;
        RECT 269.410 93.355 271.340 93.395 ;
        RECT 269.410 93.195 274.420 93.355 ;
        RECT 269.410 93.185 271.340 93.195 ;
        RECT 275.540 91.175 275.840 95.375 ;
        RECT 268.000 90.875 275.840 91.175 ;
        RECT 242.260 88.390 244.550 90.875 ;
        RECT 242.260 88.090 245.240 88.390 ;
        RECT 249.705 88.280 252.845 88.580 ;
        RECT 242.260 86.290 243.110 88.090 ;
        RECT 242.260 85.775 244.555 86.290 ;
        RECT 242.260 85.150 243.110 85.775 ;
        RECT 242.260 84.075 245.240 85.150 ;
        RECT 249.705 84.960 250.005 88.280 ;
        RECT 250.445 84.960 251.425 86.310 ;
        RECT 252.545 84.960 252.845 88.280 ;
        RECT 249.705 84.660 252.845 84.960 ;
        RECT 265.255 88.280 268.395 88.580 ;
        RECT 273.550 88.390 275.840 90.875 ;
        RECT 265.255 84.960 265.555 88.280 ;
        RECT 266.675 84.960 267.655 86.310 ;
        RECT 268.095 84.960 268.395 88.280 ;
        RECT 272.860 88.090 275.840 88.390 ;
        RECT 274.990 86.290 275.840 88.090 ;
        RECT 273.545 85.775 275.840 86.290 ;
        RECT 274.990 85.150 275.840 85.775 ;
        RECT 265.255 84.660 268.395 84.960 ;
        RECT 249.705 84.075 250.745 84.660 ;
        RECT 242.260 83.860 250.745 84.075 ;
        RECT 267.355 84.075 268.395 84.660 ;
        RECT 272.860 84.075 275.840 85.150 ;
        RECT 267.355 83.860 275.840 84.075 ;
        RECT 242.260 82.360 244.550 83.860 ;
        RECT 273.550 82.360 275.840 83.860 ;
        RECT 279.465 83.855 279.665 83.860 ;
        RECT 279.455 83.565 279.665 83.855 ;
        RECT 242.260 82.060 250.100 82.360 ;
        RECT 242.260 77.860 242.560 82.060 ;
        RECT 249.800 77.860 250.100 82.060 ;
        RECT 242.260 77.560 250.100 77.860 ;
        RECT 268.000 82.060 275.840 82.360 ;
        RECT 268.000 77.860 268.300 82.060 ;
        RECT 275.540 77.860 275.840 82.060 ;
        RECT 268.000 77.560 275.840 77.860 ;
        RECT 242.260 75.075 244.550 77.560 ;
        RECT 242.260 74.775 245.240 75.075 ;
        RECT 249.705 74.965 252.845 75.265 ;
        RECT 242.260 72.975 243.110 74.775 ;
        RECT 242.260 72.460 244.555 72.975 ;
        RECT 242.260 71.835 243.110 72.460 ;
        RECT 242.260 70.760 245.240 71.835 ;
        RECT 249.705 71.645 250.005 74.965 ;
        RECT 250.445 71.645 251.425 72.995 ;
        RECT 252.545 71.645 252.845 74.965 ;
        RECT 249.705 71.345 252.845 71.645 ;
        RECT 265.255 74.965 268.395 75.265 ;
        RECT 273.550 75.075 275.840 77.560 ;
        RECT 265.255 71.645 265.555 74.965 ;
        RECT 266.675 71.645 267.655 72.995 ;
        RECT 268.095 71.645 268.395 74.965 ;
        RECT 272.860 74.775 275.840 75.075 ;
        RECT 274.990 72.975 275.840 74.775 ;
        RECT 273.545 72.460 275.840 72.975 ;
        RECT 274.990 71.835 275.840 72.460 ;
        RECT 265.255 71.345 268.395 71.645 ;
        RECT 249.705 70.760 250.745 71.345 ;
        RECT 242.260 70.545 250.745 70.760 ;
        RECT 267.355 70.760 268.395 71.345 ;
        RECT 272.860 70.760 275.840 71.835 ;
        RECT 267.355 70.545 275.840 70.760 ;
        RECT 242.260 69.045 244.550 70.545 ;
        RECT 273.550 69.045 275.840 70.545 ;
        RECT 242.260 68.745 250.100 69.045 ;
        RECT 242.260 64.545 242.560 68.745 ;
        RECT 249.800 64.545 250.100 68.745 ;
        RECT 242.260 64.245 250.100 64.545 ;
        RECT 268.000 68.745 275.840 69.045 ;
        RECT 268.000 64.545 268.300 68.745 ;
        RECT 275.540 64.545 275.840 68.745 ;
        RECT 268.000 64.245 275.840 64.545 ;
        RECT 242.260 61.760 244.550 64.245 ;
        RECT 242.260 61.460 245.240 61.760 ;
        RECT 249.705 61.650 252.845 61.950 ;
        RECT 242.260 59.660 243.110 61.460 ;
        RECT 242.260 59.145 244.555 59.660 ;
        RECT 242.260 58.520 243.110 59.145 ;
        RECT 242.260 57.445 245.240 58.520 ;
        RECT 249.705 58.330 250.005 61.650 ;
        RECT 250.445 58.330 251.425 59.680 ;
        RECT 252.545 58.330 252.845 61.650 ;
        RECT 249.705 58.030 252.845 58.330 ;
        RECT 265.255 61.650 268.395 61.950 ;
        RECT 273.550 61.760 275.840 64.245 ;
        RECT 265.255 58.330 265.555 61.650 ;
        RECT 266.675 58.330 267.655 59.680 ;
        RECT 268.095 58.330 268.395 61.650 ;
        RECT 272.860 61.460 275.840 61.760 ;
        RECT 274.990 59.660 275.840 61.460 ;
        RECT 273.545 59.145 275.840 59.660 ;
        RECT 274.990 58.520 275.840 59.145 ;
        RECT 265.255 58.030 268.395 58.330 ;
        RECT 249.705 57.445 250.745 58.030 ;
        RECT 242.260 57.230 250.745 57.445 ;
        RECT 267.355 57.445 268.395 58.030 ;
        RECT 272.860 57.445 275.840 58.520 ;
        RECT 267.355 57.230 275.840 57.445 ;
        RECT 242.260 55.735 244.550 57.230 ;
        RECT 273.550 55.735 275.840 57.230 ;
        RECT 242.260 55.435 250.100 55.735 ;
        RECT 242.260 51.235 242.560 55.435 ;
        RECT 249.800 51.235 250.100 55.435 ;
        RECT 242.260 50.935 250.100 51.235 ;
        RECT 268.000 55.435 275.840 55.735 ;
        RECT 268.000 51.235 268.300 55.435 ;
        RECT 275.540 51.235 275.840 55.435 ;
        RECT 268.000 50.935 275.840 51.235 ;
        RECT 242.260 48.450 244.550 50.935 ;
        RECT 242.260 48.150 245.240 48.450 ;
        RECT 249.705 48.340 252.845 48.640 ;
        RECT 242.260 46.350 243.110 48.150 ;
        RECT 242.260 45.835 244.555 46.350 ;
        RECT 242.260 45.210 243.110 45.835 ;
        RECT 242.260 44.910 245.240 45.210 ;
        RECT 244.275 44.135 245.240 44.910 ;
        RECT 249.705 45.020 250.005 48.340 ;
        RECT 250.445 45.020 251.425 46.370 ;
        RECT 252.545 45.020 252.845 48.340 ;
        RECT 249.705 44.720 252.845 45.020 ;
        RECT 265.255 48.340 268.395 48.640 ;
        RECT 273.550 48.450 275.840 50.935 ;
        RECT 265.255 45.020 265.555 48.340 ;
        RECT 266.675 45.020 267.655 46.370 ;
        RECT 268.095 45.020 268.395 48.340 ;
        RECT 272.860 48.150 275.840 48.450 ;
        RECT 274.990 46.350 275.840 48.150 ;
        RECT 273.545 45.835 275.840 46.350 ;
        RECT 274.990 45.210 275.840 45.835 ;
        RECT 265.255 44.720 268.395 45.020 ;
        RECT 249.705 44.135 250.745 44.720 ;
        RECT 244.275 43.920 250.745 44.135 ;
        RECT 267.355 44.135 268.395 44.720 ;
        RECT 272.860 44.910 275.840 45.210 ;
        RECT 272.860 44.135 273.825 44.910 ;
        RECT 267.355 43.920 273.825 44.135 ;
        RECT 256.650 35.435 256.860 35.725 ;
        RECT 279.465 35.715 279.665 83.565 ;
        RECT 238.890 34.260 239.100 34.550 ;
        RECT 256.650 34.540 256.850 35.435 ;
        RECT 279.455 35.425 279.665 35.715 ;
        RECT 237.345 4.295 238.045 4.915 ;
        RECT 238.890 4.585 239.090 34.260 ;
        RECT 256.640 34.250 256.850 34.540 ;
        RECT 238.885 4.295 239.095 4.585 ;
        RECT 255.000 4.305 255.210 4.595 ;
        RECT 255.010 3.920 255.210 4.305 ;
      LAYER Metal2 ;
        RECT 44.025 93.720 48.635 96.380 ;
        RECT 84.095 93.720 88.705 96.380 ;
        RECT 105.760 93.720 110.370 96.380 ;
        RECT 126.810 93.590 136.220 96.250 ;
        RECT 267.485 93.390 267.685 93.645 ;
        RECT 263.590 93.190 271.340 93.390 ;
        RECT 267.485 92.945 267.685 93.190 ;
        RECT 79.675 91.145 80.375 91.755 ;
        RECT 103.275 91.145 103.975 91.755 ;
        RECT 237.540 90.185 237.740 90.420 ;
        RECT 243.300 90.185 244.320 90.425 ;
        RECT 237.540 89.145 244.320 90.185 ;
        RECT 237.540 88.900 237.740 89.145 ;
        RECT 243.300 88.905 244.320 89.145 ;
        RECT 267.470 89.290 267.670 91.965 ;
        RECT 267.470 89.065 269.335 89.290 ;
        RECT 269.115 83.860 269.335 89.065 ;
        RECT 269.115 83.560 279.670 83.860 ;
        RECT 237.540 76.890 237.740 77.125 ;
        RECT 243.300 76.890 244.320 77.130 ;
        RECT 237.540 75.850 244.320 76.890 ;
        RECT 237.540 75.605 237.740 75.850 ;
        RECT 243.300 75.610 244.320 75.850 ;
        RECT 237.540 63.535 237.740 63.770 ;
        RECT 243.300 63.535 244.320 63.775 ;
        RECT 237.540 62.495 244.320 63.535 ;
        RECT 237.540 62.250 237.740 62.495 ;
        RECT 243.300 62.255 244.320 62.495 ;
        RECT 256.650 35.425 279.665 35.725 ;
        RECT 238.890 34.250 256.850 34.550 ;
        RECT 116.115 28.890 120.820 29.090 ;
        RECT 140.260 17.730 140.870 21.015 ;
        RECT 237.345 4.595 238.045 4.910 ;
        RECT 237.345 4.300 255.210 4.595 ;
        RECT 237.535 4.295 255.210 4.300 ;
      LAYER Metal3 ;
        RECT 44.025 93.720 48.635 96.380 ;
        RECT 84.095 93.720 88.705 96.380 ;
        RECT 105.760 93.720 110.370 96.380 ;
        RECT 126.810 93.590 136.220 96.250 ;
        RECT 79.675 91.145 80.375 91.755 ;
        RECT 103.275 91.145 103.975 91.755 ;
      LAYER Metal4 ;
        RECT 34.895 93.465 136.235 96.465 ;
        RECT 79.675 91.145 80.375 91.755 ;
        RECT 103.275 91.145 103.975 91.755 ;
      LAYER Metal5 ;
        RECT 79.675 91.140 80.375 91.760 ;
        RECT 103.275 91.140 103.975 91.760 ;
      LAYER TopMetal1 ;
        RECT 63.730 92.270 80.330 92.285 ;
        RECT 63.730 90.630 80.845 92.270 ;
        RECT 102.805 90.630 119.890 92.285 ;
        RECT 63.730 69.585 78.230 90.630 ;
        RECT 105.390 69.585 119.890 90.630 ;
        RECT 63.730 61.385 70.030 69.585 ;
        RECT 113.590 61.385 119.890 69.585 ;
    END
  END IOVDD
  PIN VDD
    USE POWER ;
    PORT
      LAYER GatPoly ;
        RECT 223.805 92.380 225.805 92.810 ;
        RECT 226.005 92.380 228.005 92.810 ;
        RECT 228.205 92.380 230.205 92.810 ;
        RECT 230.405 92.380 232.405 92.810 ;
        RECT 163.315 47.915 163.615 48.215 ;
        RECT 163.485 47.805 163.615 47.915 ;
        RECT 167.565 47.915 167.865 48.215 ;
        RECT 167.565 47.805 167.695 47.915 ;
        RECT 170.935 46.950 171.235 47.250 ;
        RECT 173.765 46.950 174.065 47.250 ;
        RECT 171.020 46.680 171.150 46.950 ;
        RECT 173.850 46.680 173.980 46.950 ;
        RECT 152.885 44.420 153.065 45.750 ;
        RECT 152.605 43.440 153.065 44.420 ;
        RECT 152.885 42.050 153.065 43.440 ;
        RECT 156.705 42.050 156.885 45.750 ;
        RECT 171.020 43.900 171.150 44.080 ;
        RECT 173.850 43.900 173.980 44.080 ;
        RECT 163.485 42.425 163.615 42.605 ;
        RECT 167.565 42.425 167.695 42.605 ;
        RECT 45.385 12.050 45.815 12.550 ;
      LAYER Metal1 ;
        RECT 223.825 92.510 232.385 92.810 ;
        RECT 263.590 80.040 265.520 80.080 ;
        RECT 260.520 79.880 265.520 80.040 ;
        RECT 263.590 79.870 265.520 79.880 ;
        RECT 267.415 78.155 267.705 80.330 ;
        RECT 269.410 80.040 271.340 80.080 ;
        RECT 269.410 79.880 274.420 80.040 ;
        RECT 269.410 79.870 271.340 79.880 ;
        RECT 267.465 77.950 267.675 78.155 ;
        RECT 279.055 70.540 279.255 70.545 ;
        RECT 279.045 70.250 279.255 70.540 ;
        RECT 162.630 48.755 164.560 52.725 ;
        RECT 230.435 52.075 232.365 52.695 ;
        RECT 234.910 51.850 236.840 52.880 ;
        RECT 162.385 48.455 168.785 48.755 ;
        RECT 162.385 48.145 162.685 48.455 ;
        RECT 168.485 48.145 168.785 48.455 ;
        RECT 162.385 47.805 163.615 48.145 ;
        RECT 167.565 47.805 168.785 48.145 ;
        RECT 20.085 47.290 24.405 47.590 ;
        RECT 20.085 43.220 20.385 47.290 ;
        RECT 22.555 45.545 22.715 45.970 ;
        RECT 24.105 45.545 24.405 47.290 ;
        RECT 22.555 45.245 24.405 45.545 ;
        RECT 22.555 44.540 22.715 45.245 ;
        RECT 24.105 43.220 24.405 45.245 ;
        RECT 152.650 43.375 152.860 44.485 ;
        RECT 20.085 42.920 24.405 43.220 ;
        RECT 20.975 42.220 21.275 42.920 ;
        RECT 24.105 42.220 24.405 42.920 ;
        RECT 20.975 41.920 24.405 42.220 ;
        RECT 20.975 38.780 21.275 41.920 ;
        RECT 22.865 40.595 23.025 40.910 ;
        RECT 24.105 40.595 24.405 41.920 ;
        RECT 22.865 39.900 24.405 40.595 ;
        RECT 22.865 39.790 23.025 39.900 ;
        RECT 24.105 38.780 24.405 39.900 ;
        RECT 162.385 42.605 164.395 47.805 ;
        RECT 165.140 42.605 165.415 47.805 ;
        RECT 166.785 42.605 168.785 47.805 ;
        RECT 162.385 41.955 162.685 42.605 ;
        RECT 165.140 41.955 165.300 42.605 ;
        RECT 168.485 42.005 168.785 42.605 ;
        RECT 169.435 48.405 175.435 48.705 ;
        RECT 169.435 47.190 169.735 48.405 ;
        RECT 175.135 47.190 175.435 48.405 ;
        RECT 169.435 45.940 171.420 47.190 ;
        RECT 171.910 45.940 172.070 46.680 ;
        RECT 169.435 45.035 172.070 45.940 ;
        RECT 169.435 44.090 171.420 45.035 ;
        RECT 169.435 42.005 169.735 44.090 ;
        RECT 170.750 44.080 170.910 44.090 ;
        RECT 171.260 44.080 171.420 44.090 ;
        RECT 171.910 44.080 172.070 45.035 ;
        RECT 173.580 44.090 175.435 47.190 ;
        RECT 173.580 44.080 173.740 44.090 ;
        RECT 174.090 44.080 174.250 44.090 ;
        RECT 175.135 42.005 175.435 44.090 ;
        RECT 168.485 41.955 175.435 42.005 ;
        RECT 162.385 41.705 175.435 41.955 ;
        RECT 162.385 41.655 168.785 41.705 ;
        RECT 162.385 41.050 162.685 41.655 ;
        RECT 162.385 40.750 168.385 41.050 ;
        RECT 20.975 38.480 24.405 38.780 ;
        RECT 38.535 38.400 41.225 39.840 ;
        RECT 38.750 10.005 41.000 38.400 ;
        RECT 162.385 37.850 162.685 40.750 ;
        RECT 168.085 37.850 168.385 40.750 ;
        RECT 182.265 38.390 185.015 38.415 ;
        RECT 182.165 38.230 185.115 38.390 ;
        RECT 182.265 38.205 185.015 38.230 ;
        RECT 162.385 37.550 168.385 37.850 ;
        RECT 235.360 33.600 236.780 51.850 ;
        RECT 257.060 36.035 257.270 36.325 ;
        RECT 279.055 36.315 279.255 70.250 ;
        RECT 235.250 31.670 236.900 33.600 ;
        RECT 235.360 31.645 236.780 31.670 ;
        RECT 62.590 16.885 140.370 17.045 ;
        RECT 62.590 15.385 62.750 16.885 ;
        RECT 62.590 15.225 140.370 15.385 ;
        RECT 62.590 13.725 62.750 15.225 ;
        RECT 62.590 13.565 140.370 13.725 ;
        RECT 45.135 11.995 45.835 12.615 ;
        RECT 62.590 12.065 62.750 13.565 ;
        RECT 112.335 12.065 114.265 12.090 ;
        RECT 62.590 11.905 140.370 12.065 ;
        RECT 112.335 11.880 114.265 11.905 ;
        RECT 45.135 10.005 45.835 10.585 ;
        RECT 111.740 10.005 114.900 10.265 ;
        RECT 145.295 10.005 148.385 15.060 ;
        RECT 38.750 9.365 148.385 10.005 ;
        RECT 111.740 9.030 148.385 9.365 ;
        RECT 111.740 6.565 148.330 9.030 ;
        RECT 238.365 4.575 238.665 34.570 ;
        RECT 239.300 33.660 239.510 33.950 ;
        RECT 257.060 33.940 257.260 36.035 ;
        RECT 279.045 36.025 279.255 36.315 ;
        RECT 239.300 5.185 239.500 33.660 ;
        RECT 257.050 33.650 257.260 33.940 ;
        RECT 243.865 27.165 246.330 27.605 ;
        RECT 244.195 25.840 244.455 27.165 ;
        RECT 246.120 26.905 246.330 27.165 ;
        RECT 249.840 24.190 274.730 24.630 ;
        RECT 249.860 23.930 250.070 24.190 ;
        RECT 252.490 23.190 252.750 24.190 ;
        RECT 253.510 23.190 253.770 24.190 ;
        RECT 254.605 23.190 254.865 24.190 ;
        RECT 258.765 23.190 259.025 24.190 ;
        RECT 259.785 23.190 260.045 24.190 ;
        RECT 260.880 23.190 261.140 24.190 ;
        RECT 265.040 23.190 265.300 24.190 ;
        RECT 266.060 23.190 266.320 24.190 ;
        RECT 267.155 23.190 267.415 24.190 ;
        RECT 271.315 23.190 271.575 24.190 ;
        RECT 272.335 23.190 272.595 24.190 ;
        RECT 273.430 23.190 273.690 24.190 ;
        RECT 246.120 22.520 246.330 22.615 ;
        RECT 249.860 22.520 250.070 22.800 ;
        RECT 243.865 22.085 250.095 22.520 ;
        RECT 243.865 22.080 245.305 22.085 ;
        RECT 244.195 20.755 244.455 22.080 ;
        RECT 246.120 21.915 246.330 22.085 ;
        RECT 246.120 17.390 246.330 17.790 ;
        RECT 243.865 16.950 246.330 17.390 ;
        RECT 244.195 15.625 244.455 16.950 ;
        RECT 246.120 16.710 246.330 16.950 ;
        RECT 252.490 16.710 252.750 17.710 ;
        RECT 253.510 16.710 253.770 17.710 ;
        RECT 254.605 16.710 254.865 17.710 ;
        RECT 258.765 16.710 259.025 17.710 ;
        RECT 259.785 16.710 260.045 17.710 ;
        RECT 260.880 16.710 261.140 17.710 ;
        RECT 265.040 16.710 265.300 17.710 ;
        RECT 266.060 16.710 266.320 17.710 ;
        RECT 267.155 16.710 267.415 17.710 ;
        RECT 271.315 16.710 271.575 17.710 ;
        RECT 272.335 16.710 272.595 17.710 ;
        RECT 273.430 16.710 273.690 17.710 ;
        RECT 246.120 16.270 274.730 16.710 ;
        RECT 239.295 4.895 239.505 5.185 ;
        RECT 255.410 4.905 255.620 5.195 ;
        RECT 255.420 3.920 255.620 4.905 ;
      LAYER Metal2 ;
        RECT 230.440 92.555 232.370 92.755 ;
        RECT 267.485 80.075 267.685 80.330 ;
        RECT 263.590 79.875 271.340 80.075 ;
        RECT 267.485 79.630 267.685 79.875 ;
        RECT 267.470 75.975 267.670 78.650 ;
        RECT 267.470 75.750 269.335 75.975 ;
        RECT 269.115 70.545 269.335 75.750 ;
        RECT 269.115 70.245 279.260 70.545 ;
        RECT 234.910 52.795 236.840 52.875 ;
        RECT 145.330 51.970 236.840 52.795 ;
        RECT 234.910 51.855 236.840 51.970 ;
        RECT 145.330 43.380 152.880 44.495 ;
        RECT 152.655 43.375 152.855 43.380 ;
        RECT 38.535 39.740 41.225 39.835 ;
        RECT 24.105 38.480 41.225 39.740 ;
        RECT 38.535 38.405 41.225 38.480 ;
        RECT 182.265 38.210 185.015 38.410 ;
        RECT 257.060 36.025 279.255 36.325 ;
        RECT 239.300 33.650 257.260 33.950 ;
        RECT 235.360 33.600 238.665 33.640 ;
        RECT 235.255 31.670 238.665 33.600 ;
        RECT 235.360 31.645 238.665 31.670 ;
        RECT 238.370 27.605 238.570 27.935 ;
        RECT 238.365 27.490 244.355 27.605 ;
        RECT 238.365 27.290 244.575 27.490 ;
        RECT 238.365 27.165 244.355 27.290 ;
        RECT 238.370 26.825 238.570 27.165 ;
        RECT 238.370 22.520 238.570 22.850 ;
        RECT 238.365 22.405 244.355 22.520 ;
        RECT 238.365 22.205 244.575 22.405 ;
        RECT 238.365 22.080 244.355 22.205 ;
        RECT 238.370 21.740 238.570 22.080 ;
        RECT 238.370 17.390 238.570 17.720 ;
        RECT 238.365 17.275 244.355 17.390 ;
        RECT 238.365 17.075 244.575 17.275 ;
        RECT 238.365 16.950 244.355 17.075 ;
        RECT 238.370 16.610 238.570 16.950 ;
        RECT 246.125 16.270 246.325 27.605 ;
        RECT 249.840 22.085 250.095 24.630 ;
        RECT 45.135 9.945 45.835 12.610 ;
        RECT 112.295 10.260 114.265 12.085 ;
        RECT 111.740 9.650 114.900 10.260 ;
        RECT 145.300 9.030 148.380 15.060 ;
        RECT 238.410 5.195 238.610 5.510 ;
        RECT 238.365 4.895 255.620 5.195 ;
        RECT 238.410 4.810 238.610 4.895 ;
      LAYER Metal3 ;
        RECT 145.435 52.085 148.185 52.695 ;
        RECT 145.405 43.630 148.155 44.240 ;
        RECT 182.265 38.410 182.485 52.795 ;
        RECT 230.420 51.970 232.385 92.755 ;
        RECT 182.265 38.210 185.015 38.410 ;
        RECT 182.265 38.205 182.485 38.210 ;
        RECT 145.300 9.030 148.380 15.060 ;
      LAYER Metal4 ;
        RECT 145.330 15.060 148.330 96.465 ;
        RECT 145.300 9.030 148.380 15.060 ;
    END
  END VDD
  OBS
      LAYER GatPoly ;
        RECT 243.060 93.465 243.680 93.915 ;
        RECT 248.680 93.620 249.300 93.915 ;
        RECT 251.960 93.620 252.580 93.915 ;
        RECT 248.680 93.465 249.560 93.620 ;
        RECT 243.060 93.085 243.500 93.465 ;
        RECT 248.860 93.085 249.560 93.465 ;
        RECT 151.205 92.380 153.205 92.810 ;
        RECT 153.405 92.380 155.405 92.810 ;
        RECT 155.605 92.380 157.605 92.810 ;
        RECT 157.805 92.380 159.805 92.810 ;
        RECT 160.005 92.380 162.005 92.810 ;
        RECT 162.205 92.380 164.205 92.810 ;
        RECT 164.405 92.380 166.405 92.810 ;
        RECT 166.605 92.380 168.605 92.810 ;
        RECT 168.805 92.380 170.805 92.810 ;
        RECT 171.005 92.380 173.005 92.810 ;
        RECT 173.205 92.380 175.205 92.810 ;
        RECT 175.405 92.380 177.405 92.810 ;
        RECT 177.605 92.380 179.605 92.810 ;
        RECT 179.805 92.380 181.805 92.810 ;
        RECT 182.005 92.380 184.005 92.810 ;
        RECT 184.205 92.380 186.205 92.810 ;
        RECT 186.405 92.380 188.405 92.810 ;
        RECT 188.605 92.380 190.605 92.810 ;
        RECT 190.805 92.380 192.805 92.810 ;
        RECT 193.005 92.380 195.005 92.810 ;
        RECT 195.205 92.380 197.205 92.810 ;
        RECT 197.405 92.380 199.405 92.810 ;
        RECT 199.605 92.380 201.605 92.810 ;
        RECT 201.805 92.380 203.805 92.810 ;
        RECT 204.005 92.380 206.005 92.810 ;
        RECT 206.205 92.380 208.205 92.810 ;
        RECT 208.405 92.380 210.405 92.810 ;
        RECT 210.605 92.380 212.605 92.810 ;
        RECT 212.805 92.380 214.805 92.810 ;
        RECT 215.005 92.380 217.005 92.810 ;
        RECT 217.205 92.380 219.205 92.810 ;
        RECT 219.405 92.380 221.405 92.810 ;
        RECT 221.605 92.380 223.605 92.810 ;
        RECT 243.060 92.635 243.680 93.085 ;
        RECT 248.680 92.980 249.560 93.085 ;
        RECT 251.735 93.465 252.580 93.620 ;
        RECT 257.580 93.465 258.200 93.915 ;
        RECT 251.735 93.085 252.400 93.465 ;
        RECT 257.760 93.085 258.200 93.465 ;
        RECT 251.735 92.980 252.580 93.085 ;
        RECT 248.680 92.635 249.300 92.980 ;
        RECT 251.960 92.635 252.580 92.980 ;
        RECT 257.580 92.635 258.200 93.085 ;
        RECT 259.900 93.465 260.520 93.915 ;
        RECT 265.520 93.620 266.140 93.915 ;
        RECT 268.800 93.620 269.420 93.915 ;
        RECT 265.520 93.465 266.365 93.620 ;
        RECT 259.900 93.085 260.340 93.465 ;
        RECT 265.700 93.085 266.365 93.465 ;
        RECT 259.900 92.635 260.520 93.085 ;
        RECT 265.520 92.980 266.365 93.085 ;
        RECT 268.540 93.465 269.420 93.620 ;
        RECT 274.420 93.465 275.040 93.915 ;
        RECT 268.540 93.085 269.240 93.465 ;
        RECT 274.600 93.085 275.040 93.465 ;
        RECT 268.540 92.980 269.420 93.085 ;
        RECT 265.520 92.635 266.140 92.980 ;
        RECT 268.800 92.635 269.420 92.980 ;
        RECT 274.420 92.635 275.040 93.085 ;
        RECT 128.600 91.475 131.600 91.655 ;
        RECT 133.100 91.475 136.100 91.655 ;
        RECT 16.095 90.790 29.215 91.090 ;
        RECT 16.435 90.570 29.215 90.790 ;
        RECT 128.600 90.795 131.600 90.975 ;
        RECT 133.100 90.795 136.100 90.975 ;
        RECT 38.920 90.590 39.920 90.770 ;
        RECT 40.920 90.590 41.920 90.770 ;
        RECT 16.435 90.390 17.935 90.570 ;
        RECT 18.315 90.390 19.815 90.570 ;
        RECT 20.195 90.390 21.695 90.570 ;
        RECT 22.075 90.390 23.575 90.570 ;
        RECT 23.955 90.390 25.455 90.570 ;
        RECT 25.835 90.390 27.335 90.570 ;
        RECT 27.715 90.390 29.215 90.570 ;
        RECT 128.600 89.905 136.100 90.795 ;
        RECT 128.600 89.735 131.600 89.905 ;
        RECT 133.100 89.735 136.100 89.905 ;
        RECT 128.600 89.055 131.600 89.235 ;
        RECT 133.100 89.055 136.100 89.235 ;
        RECT 16.435 88.210 17.935 88.390 ;
        RECT 18.315 88.210 19.815 88.390 ;
        RECT 20.195 88.210 21.695 88.390 ;
        RECT 22.075 88.210 23.575 88.390 ;
        RECT 23.955 88.210 25.455 88.390 ;
        RECT 25.835 88.210 27.335 88.390 ;
        RECT 27.715 88.210 29.215 88.390 ;
        RECT 128.600 88.165 136.100 89.055 ;
        RECT 128.600 87.995 131.600 88.165 ;
        RECT 133.100 87.995 136.100 88.165 ;
        RECT 128.600 87.315 131.600 87.495 ;
        RECT 133.100 87.315 136.100 87.495 ;
        RECT 243.895 86.400 244.075 86.850 ;
        RECT 244.555 86.400 247.110 86.850 ;
        RECT 247.410 86.400 247.590 86.850 ;
        RECT 254.895 86.820 255.075 86.845 ;
        RECT 250.945 86.420 251.125 86.820 ;
        RECT 251.425 86.680 252.195 86.820 ;
        RECT 254.325 86.680 255.075 86.820 ;
        RECT 251.425 86.420 252.235 86.680 ;
        RECT 251.595 86.380 252.235 86.420 ;
        RECT 254.285 86.395 255.075 86.680 ;
        RECT 257.075 86.395 257.255 86.845 ;
        RECT 260.845 86.395 261.025 86.845 ;
        RECT 263.025 86.820 263.205 86.845 ;
        RECT 263.025 86.680 263.775 86.820 ;
        RECT 265.905 86.680 266.675 86.820 ;
        RECT 263.025 86.395 263.815 86.680 ;
        RECT 254.285 86.380 254.925 86.395 ;
        RECT 263.175 86.380 263.815 86.395 ;
        RECT 265.865 86.420 266.675 86.680 ;
        RECT 266.975 86.420 267.155 86.820 ;
        RECT 265.865 86.380 266.505 86.420 ;
        RECT 270.510 86.400 270.690 86.850 ;
        RECT 270.990 86.400 273.545 86.850 ;
        RECT 274.025 86.400 274.205 86.850 ;
        RECT 38.920 85.410 39.920 85.590 ;
        RECT 40.920 85.410 41.920 85.590 ;
        RECT 38.920 84.670 41.920 85.410 ;
        RECT 38.920 84.490 39.920 84.670 ;
        RECT 40.920 84.490 41.920 84.670 ;
        RECT 130.600 84.200 131.600 84.380 ;
        RECT 133.100 84.200 134.100 84.380 ;
        RECT 130.600 82.085 131.600 82.200 ;
        RECT 130.590 82.020 131.600 82.085 ;
        RECT 133.100 82.020 134.100 82.200 ;
        RECT 130.590 81.785 134.100 82.020 ;
        RECT 130.600 81.140 134.100 81.785 ;
        RECT 130.600 80.960 131.600 81.140 ;
        RECT 133.100 80.960 134.100 81.140 ;
        RECT 6.440 70.340 7.195 80.340 ;
        RECT 10.195 70.340 10.375 80.340 ;
        RECT 243.060 80.150 243.680 80.600 ;
        RECT 248.680 80.305 249.300 80.600 ;
        RECT 251.960 80.305 252.580 80.600 ;
        RECT 248.680 80.150 249.560 80.305 ;
        RECT 243.060 79.770 243.500 80.150 ;
        RECT 248.860 79.770 249.560 80.150 ;
        RECT 38.920 79.310 39.920 79.490 ;
        RECT 40.920 79.310 41.920 79.490 ;
        RECT 243.060 79.320 243.680 79.770 ;
        RECT 248.680 79.665 249.560 79.770 ;
        RECT 251.735 80.150 252.580 80.305 ;
        RECT 257.580 80.150 258.200 80.600 ;
        RECT 251.735 79.770 252.400 80.150 ;
        RECT 257.760 79.770 258.200 80.150 ;
        RECT 251.735 79.665 252.580 79.770 ;
        RECT 248.680 79.320 249.300 79.665 ;
        RECT 251.960 79.320 252.580 79.665 ;
        RECT 257.580 79.320 258.200 79.770 ;
        RECT 259.900 80.150 260.520 80.600 ;
        RECT 265.520 80.305 266.140 80.600 ;
        RECT 268.800 80.305 269.420 80.600 ;
        RECT 265.520 80.150 266.365 80.305 ;
        RECT 259.900 79.770 260.340 80.150 ;
        RECT 265.700 79.770 266.365 80.150 ;
        RECT 259.900 79.320 260.520 79.770 ;
        RECT 265.520 79.665 266.365 79.770 ;
        RECT 268.540 80.150 269.420 80.305 ;
        RECT 274.420 80.150 275.040 80.600 ;
        RECT 268.540 79.770 269.240 80.150 ;
        RECT 274.600 79.770 275.040 80.150 ;
        RECT 268.540 79.665 269.420 79.770 ;
        RECT 265.520 79.320 266.140 79.665 ;
        RECT 268.800 79.320 269.420 79.665 ;
        RECT 274.420 79.320 275.040 79.770 ;
        RECT 130.600 78.780 131.600 78.960 ;
        RECT 133.100 78.780 134.100 78.960 ;
        RECT 85.825 78.580 90.825 78.760 ;
        RECT 92.795 78.580 97.795 78.760 ;
        RECT 38.095 76.050 42.745 76.625 ;
        RECT 53.930 76.580 54.430 77.010 ;
        RECT 55.250 76.580 55.750 77.010 ;
        RECT 56.570 76.580 57.070 77.010 ;
        RECT 57.890 76.580 58.390 77.010 ;
        RECT 59.210 76.580 59.710 77.010 ;
        RECT 60.530 76.580 61.030 77.010 ;
        RECT 38.095 75.870 38.545 76.050 ;
        RECT 39.495 75.870 39.945 76.050 ;
        RECT 40.895 75.870 41.345 76.050 ;
        RECT 42.295 75.870 42.745 76.050 ;
        RECT 47.425 75.870 48.425 76.050 ;
        RECT 50.185 75.870 51.185 76.050 ;
        RECT 243.895 73.085 244.075 73.535 ;
        RECT 244.555 73.085 247.110 73.535 ;
        RECT 247.410 73.085 247.590 73.535 ;
        RECT 254.895 73.505 255.075 73.530 ;
        RECT 250.945 73.105 251.125 73.505 ;
        RECT 251.425 73.365 252.195 73.505 ;
        RECT 254.325 73.365 255.075 73.505 ;
        RECT 251.425 73.105 252.235 73.365 ;
        RECT 251.595 73.065 252.235 73.105 ;
        RECT 254.285 73.080 255.075 73.365 ;
        RECT 257.075 73.080 257.255 73.530 ;
        RECT 260.845 73.080 261.025 73.530 ;
        RECT 263.025 73.505 263.205 73.530 ;
        RECT 263.025 73.365 263.775 73.505 ;
        RECT 265.905 73.365 266.675 73.505 ;
        RECT 263.025 73.080 263.815 73.365 ;
        RECT 254.285 73.065 254.925 73.080 ;
        RECT 263.175 73.065 263.815 73.080 ;
        RECT 265.865 73.105 266.675 73.365 ;
        RECT 266.975 73.105 267.155 73.505 ;
        RECT 265.865 73.065 266.505 73.105 ;
        RECT 270.510 73.085 270.690 73.535 ;
        RECT 270.990 73.085 273.545 73.535 ;
        RECT 274.025 73.085 274.205 73.535 ;
        RECT 123.850 72.100 125.850 72.280 ;
        RECT 126.850 72.100 128.850 72.280 ;
        RECT 129.850 72.100 131.850 72.280 ;
        RECT 132.850 72.100 134.850 72.520 ;
        RECT 135.850 72.100 137.850 72.280 ;
        RECT 138.850 72.100 140.850 72.280 ;
        RECT 6.440 69.960 7.015 70.340 ;
        RECT 6.440 59.960 7.195 69.960 ;
        RECT 10.195 59.960 10.375 69.960 ;
        RECT 85.825 68.155 90.825 68.580 ;
        RECT 92.795 68.155 97.795 68.580 ;
        RECT 85.825 67.340 90.825 67.765 ;
        RECT 92.795 67.340 97.795 67.765 ;
        RECT 123.850 67.690 125.850 68.100 ;
        RECT 126.850 67.690 128.850 68.100 ;
        RECT 129.850 67.690 131.850 68.100 ;
        RECT 132.850 67.920 134.850 68.100 ;
        RECT 135.850 67.690 137.850 68.100 ;
        RECT 138.850 67.690 140.850 68.100 ;
        RECT 243.060 66.835 243.680 67.285 ;
        RECT 248.680 66.990 249.300 67.285 ;
        RECT 251.960 66.990 252.580 67.285 ;
        RECT 248.680 66.835 249.560 66.990 ;
        RECT 243.060 66.455 243.500 66.835 ;
        RECT 248.860 66.455 249.560 66.835 ;
        RECT 243.060 66.005 243.680 66.455 ;
        RECT 248.680 66.350 249.560 66.455 ;
        RECT 251.735 66.835 252.580 66.990 ;
        RECT 257.580 66.835 258.200 67.285 ;
        RECT 251.735 66.455 252.400 66.835 ;
        RECT 257.760 66.455 258.200 66.835 ;
        RECT 251.735 66.350 252.580 66.455 ;
        RECT 248.680 66.005 249.300 66.350 ;
        RECT 251.960 66.005 252.580 66.350 ;
        RECT 257.580 66.005 258.200 66.455 ;
        RECT 259.900 66.835 260.520 67.285 ;
        RECT 265.520 66.990 266.140 67.285 ;
        RECT 268.800 66.990 269.420 67.285 ;
        RECT 265.520 66.835 266.365 66.990 ;
        RECT 259.900 66.455 260.340 66.835 ;
        RECT 265.700 66.455 266.365 66.835 ;
        RECT 259.900 66.005 260.520 66.455 ;
        RECT 265.520 66.350 266.365 66.455 ;
        RECT 268.540 66.835 269.420 66.990 ;
        RECT 274.420 66.835 275.040 67.285 ;
        RECT 268.540 66.455 269.240 66.835 ;
        RECT 274.600 66.455 275.040 66.835 ;
        RECT 268.540 66.350 269.420 66.455 ;
        RECT 265.520 66.005 266.140 66.350 ;
        RECT 268.800 66.005 269.420 66.350 ;
        RECT 274.420 66.005 275.040 66.455 ;
        RECT 38.095 65.690 38.545 65.870 ;
        RECT 39.495 65.690 39.945 65.870 ;
        RECT 40.895 65.690 41.345 65.870 ;
        RECT 42.295 65.690 42.745 65.870 ;
        RECT 47.425 65.690 48.425 65.870 ;
        RECT 50.185 65.690 51.185 65.870 ;
        RECT 47.435 65.460 48.415 65.690 ;
        RECT 50.365 65.460 51.005 65.690 ;
        RECT 13.030 64.915 13.210 65.230 ;
        RECT 12.595 64.660 13.210 64.915 ;
        RECT 12.595 62.935 12.810 64.660 ;
        RECT 13.030 64.430 13.210 64.660 ;
        RECT 14.410 64.965 14.590 65.230 ;
        RECT 15.270 64.965 15.450 65.230 ;
        RECT 14.410 64.665 15.450 64.965 ;
        RECT 14.410 64.430 14.590 64.665 ;
        RECT 15.270 64.430 15.450 64.665 ;
        RECT 16.650 64.965 16.830 65.230 ;
        RECT 38.095 64.970 38.545 65.150 ;
        RECT 42.295 64.970 42.745 65.150 ;
        RECT 16.650 64.665 17.725 64.965 ;
        RECT 123.630 64.905 141.070 65.240 ;
        RECT 123.630 64.780 124.630 64.905 ;
        RECT 125.350 64.780 129.350 64.905 ;
        RECT 130.350 64.780 134.350 64.905 ;
        RECT 135.350 64.780 139.350 64.905 ;
        RECT 140.070 64.780 141.070 64.905 ;
        RECT 16.650 64.430 16.830 64.665 ;
        RECT 17.055 64.090 17.355 64.665 ;
        RECT 13.030 62.935 13.210 63.210 ;
        RECT 12.595 62.695 13.210 62.935 ;
        RECT 13.030 62.410 13.210 62.695 ;
        RECT 14.410 62.980 14.590 63.210 ;
        RECT 15.270 62.980 15.450 63.210 ;
        RECT 14.410 62.680 15.450 62.980 ;
        RECT 14.410 62.410 14.590 62.680 ;
        RECT 15.270 62.410 15.450 62.680 ;
        RECT 16.650 62.410 16.830 63.210 ;
        RECT 20.605 63.030 20.785 64.530 ;
        RECT 22.785 64.425 23.185 64.530 ;
        RECT 22.785 63.785 23.690 64.425 ;
        RECT 22.785 63.030 23.185 63.785 ;
        RECT 22.965 62.650 23.185 63.030 ;
        RECT 20.605 61.150 20.785 62.650 ;
        RECT 22.785 61.150 23.185 62.650 ;
        RECT 22.965 60.770 23.185 61.150 ;
        RECT 6.440 59.580 7.015 59.960 ;
        RECT 6.440 49.580 7.195 59.580 ;
        RECT 10.195 49.580 10.375 59.580 ;
        RECT 20.605 59.270 20.785 60.770 ;
        RECT 22.785 59.270 23.185 60.770 ;
        RECT 53.930 60.740 54.430 61.170 ;
        RECT 55.250 60.740 55.750 61.170 ;
        RECT 56.570 60.740 57.070 61.170 ;
        RECT 57.890 60.740 58.390 61.170 ;
        RECT 59.210 60.740 59.710 61.170 ;
        RECT 53.930 59.530 54.430 59.960 ;
        RECT 55.250 59.530 55.750 59.960 ;
        RECT 56.570 59.530 57.070 59.960 ;
        RECT 57.890 59.530 58.390 59.960 ;
        RECT 59.210 59.530 59.710 59.960 ;
        RECT 243.895 59.770 244.075 60.220 ;
        RECT 244.555 59.770 247.110 60.220 ;
        RECT 247.410 59.770 247.590 60.220 ;
        RECT 254.895 60.190 255.075 60.215 ;
        RECT 250.945 59.790 251.125 60.190 ;
        RECT 251.425 60.050 252.195 60.190 ;
        RECT 254.325 60.050 255.075 60.190 ;
        RECT 251.425 59.790 252.235 60.050 ;
        RECT 251.595 59.750 252.235 59.790 ;
        RECT 254.285 59.765 255.075 60.050 ;
        RECT 257.075 59.765 257.255 60.215 ;
        RECT 260.845 59.765 261.025 60.215 ;
        RECT 263.025 60.190 263.205 60.215 ;
        RECT 263.025 60.050 263.775 60.190 ;
        RECT 265.905 60.050 266.675 60.190 ;
        RECT 263.025 59.765 263.815 60.050 ;
        RECT 254.285 59.750 254.925 59.765 ;
        RECT 263.175 59.750 263.815 59.765 ;
        RECT 265.865 59.790 266.675 60.050 ;
        RECT 266.975 59.790 267.155 60.190 ;
        RECT 265.865 59.750 266.505 59.790 ;
        RECT 270.510 59.770 270.690 60.220 ;
        RECT 270.990 59.770 273.545 60.220 ;
        RECT 274.025 59.770 274.205 60.220 ;
        RECT 22.965 58.890 23.185 59.270 ;
        RECT 13.255 56.710 13.605 57.510 ;
        RECT 14.805 56.710 14.985 57.510 ;
        RECT 20.605 57.390 20.785 58.890 ;
        RECT 22.785 57.390 23.185 58.890 ;
        RECT 22.965 57.010 23.185 57.390 ;
        RECT 85.825 57.160 90.825 57.340 ;
        RECT 92.795 57.160 97.795 57.340 ;
        RECT 13.255 56.330 13.495 56.710 ;
        RECT 13.255 55.530 13.605 56.330 ;
        RECT 14.805 56.245 14.985 56.330 ;
        RECT 14.805 55.605 15.730 56.245 ;
        RECT 14.805 55.530 14.985 55.605 ;
        RECT 13.255 55.150 13.495 55.530 ;
        RECT 20.605 55.510 20.785 57.010 ;
        RECT 22.785 55.510 23.185 57.010 ;
        RECT 123.630 56.240 124.630 57.280 ;
        RECT 125.350 57.100 129.350 57.280 ;
        RECT 130.350 57.100 134.350 57.280 ;
        RECT 135.350 57.100 139.350 57.280 ;
        RECT 125.350 56.240 129.350 56.420 ;
        RECT 130.350 56.240 134.350 56.420 ;
        RECT 135.350 56.240 139.350 56.420 ;
        RECT 140.070 56.240 141.070 57.280 ;
        RECT 13.255 54.350 13.605 55.150 ;
        RECT 14.805 54.350 14.985 55.150 ;
        RECT 22.965 55.130 23.185 55.510 ;
        RECT 13.255 53.970 13.495 54.350 ;
        RECT 13.255 53.170 13.605 53.970 ;
        RECT 14.805 53.170 14.985 53.970 ;
        RECT 20.605 53.630 20.785 55.130 ;
        RECT 22.785 53.630 23.185 55.130 ;
        RECT 38.095 54.070 38.545 54.970 ;
        RECT 39.495 54.070 39.945 54.250 ;
        RECT 40.895 54.070 41.345 54.250 ;
        RECT 42.295 54.070 42.745 54.970 ;
        RECT 47.425 54.070 48.425 54.250 ;
        RECT 50.185 54.070 51.185 54.250 ;
        RECT 69.980 53.720 79.980 53.900 ;
        RECT 81.200 53.720 91.200 53.900 ;
        RECT 92.420 53.720 102.420 53.900 ;
        RECT 103.640 53.720 113.640 53.900 ;
        RECT 151.205 53.640 153.205 54.070 ;
        RECT 153.405 53.640 155.405 54.070 ;
        RECT 155.605 53.640 157.605 54.070 ;
        RECT 157.805 53.640 159.805 54.070 ;
        RECT 160.005 53.640 162.005 54.070 ;
        RECT 162.205 53.640 164.205 54.070 ;
        RECT 164.405 53.640 166.405 54.070 ;
        RECT 166.605 53.640 168.605 54.070 ;
        RECT 168.805 53.640 170.805 54.070 ;
        RECT 171.005 53.640 173.005 54.070 ;
        RECT 173.205 53.640 175.205 54.070 ;
        RECT 175.405 53.640 177.405 54.070 ;
        RECT 177.605 53.640 179.605 54.070 ;
        RECT 179.805 53.640 181.805 54.070 ;
        RECT 182.005 53.640 184.005 54.070 ;
        RECT 184.205 53.640 186.205 54.070 ;
        RECT 186.405 53.640 188.405 54.070 ;
        RECT 188.605 53.640 190.605 54.070 ;
        RECT 190.805 53.640 192.805 54.070 ;
        RECT 193.005 53.640 195.005 54.070 ;
        RECT 195.205 53.640 197.205 54.070 ;
        RECT 197.405 53.640 199.405 54.070 ;
        RECT 199.605 53.640 201.605 54.070 ;
        RECT 201.805 53.640 203.805 54.070 ;
        RECT 204.005 53.640 206.005 54.070 ;
        RECT 206.205 53.640 208.205 54.070 ;
        RECT 208.405 53.640 210.405 54.070 ;
        RECT 210.605 53.640 212.605 54.070 ;
        RECT 212.805 53.640 214.805 54.070 ;
        RECT 215.005 53.640 217.005 54.070 ;
        RECT 217.205 53.640 219.205 54.070 ;
        RECT 219.405 53.640 221.405 54.070 ;
        RECT 221.605 53.640 223.605 54.070 ;
        RECT 223.805 53.640 225.805 54.070 ;
        RECT 226.005 53.640 228.005 54.070 ;
        RECT 228.205 53.640 230.205 54.070 ;
        RECT 230.405 53.640 232.405 54.070 ;
        RECT 63.640 53.395 66.390 53.575 ;
        RECT 243.060 53.525 243.680 53.975 ;
        RECT 248.680 53.680 249.300 53.975 ;
        RECT 251.960 53.680 252.580 53.975 ;
        RECT 248.680 53.525 249.560 53.680 ;
        RECT 243.060 53.145 243.500 53.525 ;
        RECT 248.860 53.145 249.560 53.525 ;
        RECT 69.980 51.680 79.980 52.720 ;
        RECT 81.200 52.540 91.200 52.720 ;
        RECT 92.420 52.540 102.420 52.720 ;
        RECT 81.200 51.860 102.420 52.540 ;
        RECT 81.200 51.680 91.200 51.860 ;
        RECT 92.420 51.680 102.420 51.860 ;
        RECT 103.640 51.680 113.640 52.720 ;
        RECT 243.060 52.695 243.680 53.145 ;
        RECT 248.680 53.040 249.560 53.145 ;
        RECT 251.735 53.525 252.580 53.680 ;
        RECT 257.580 53.525 258.200 53.975 ;
        RECT 251.735 53.145 252.400 53.525 ;
        RECT 257.760 53.145 258.200 53.525 ;
        RECT 251.735 53.040 252.580 53.145 ;
        RECT 248.680 52.695 249.300 53.040 ;
        RECT 251.960 52.695 252.580 53.040 ;
        RECT 257.580 52.695 258.200 53.145 ;
        RECT 259.900 53.525 260.520 53.975 ;
        RECT 265.520 53.680 266.140 53.975 ;
        RECT 268.800 53.680 269.420 53.975 ;
        RECT 265.520 53.525 266.365 53.680 ;
        RECT 259.900 53.145 260.340 53.525 ;
        RECT 265.700 53.145 266.365 53.525 ;
        RECT 259.900 52.695 260.520 53.145 ;
        RECT 265.520 53.040 266.365 53.145 ;
        RECT 268.540 53.525 269.420 53.680 ;
        RECT 274.420 53.525 275.040 53.975 ;
        RECT 268.540 53.145 269.240 53.525 ;
        RECT 274.600 53.145 275.040 53.525 ;
        RECT 268.540 53.040 269.420 53.145 ;
        RECT 265.520 52.695 266.140 53.040 ;
        RECT 268.800 52.695 269.420 53.040 ;
        RECT 274.420 52.695 275.040 53.145 ;
        RECT 63.640 50.985 66.390 51.395 ;
        RECT 69.980 50.500 79.980 50.680 ;
        RECT 81.200 50.500 91.200 50.680 ;
        RECT 92.420 50.500 102.420 50.680 ;
        RECT 103.640 50.500 113.640 50.680 ;
        RECT 6.440 49.240 6.740 49.580 ;
        RECT 183.085 49.395 185.085 49.825 ;
        RECT 63.250 47.800 63.680 48.300 ;
        RECT 73.680 47.800 74.110 48.300 ;
        RECT 74.890 47.800 75.320 48.300 ;
        RECT 85.320 47.800 85.750 48.300 ;
        RECT 86.530 47.800 86.960 48.300 ;
        RECT 96.960 47.800 97.390 48.300 ;
        RECT 98.170 47.800 98.600 48.300 ;
        RECT 108.600 47.800 109.030 48.300 ;
        RECT 109.810 47.800 110.240 48.300 ;
        RECT 120.240 47.800 120.670 48.300 ;
        RECT 123.630 47.700 124.630 48.740 ;
        RECT 125.350 48.330 129.350 48.740 ;
        RECT 130.350 48.330 134.350 48.740 ;
        RECT 135.350 48.330 139.350 48.740 ;
        RECT 125.350 47.700 129.350 47.880 ;
        RECT 130.350 47.700 134.350 47.880 ;
        RECT 135.350 47.700 139.350 47.880 ;
        RECT 140.070 47.700 141.070 48.740 ;
        RECT 164.420 47.985 164.720 48.285 ;
        RECT 166.460 47.985 166.760 48.285 ;
        RECT 178.050 48.185 180.000 48.365 ;
        RECT 164.505 47.805 164.635 47.985 ;
        RECT 165.525 47.805 165.655 47.985 ;
        RECT 166.545 47.805 166.675 47.985 ;
        RECT 13.635 46.700 14.275 47.000 ;
        RECT 21.890 46.700 22.530 47.000 ;
        RECT 13.770 46.270 14.070 46.700 ;
        RECT 13.695 46.090 14.145 46.270 ;
        RECT 22.095 46.150 22.395 46.700 ;
        RECT 63.250 46.480 63.680 46.980 ;
        RECT 73.680 46.480 74.110 46.980 ;
        RECT 74.890 46.480 75.320 46.980 ;
        RECT 85.320 46.480 85.750 46.980 ;
        RECT 86.530 46.480 86.960 46.980 ;
        RECT 96.960 46.480 97.390 46.980 ;
        RECT 98.170 46.480 98.600 46.980 ;
        RECT 108.600 46.480 109.030 46.980 ;
        RECT 109.810 46.480 110.240 46.980 ;
        RECT 120.240 46.480 120.670 46.980 ;
        RECT 172.180 46.680 172.310 46.860 ;
        RECT 172.690 46.680 172.820 46.860 ;
        RECT 243.895 46.460 244.075 46.910 ;
        RECT 244.555 46.460 247.110 46.910 ;
        RECT 247.410 46.460 247.590 46.910 ;
        RECT 254.895 46.880 255.075 46.905 ;
        RECT 250.945 46.480 251.125 46.880 ;
        RECT 251.425 46.740 252.195 46.880 ;
        RECT 254.325 46.740 255.075 46.880 ;
        RECT 251.425 46.480 252.235 46.740 ;
        RECT 251.595 46.440 252.235 46.480 ;
        RECT 254.285 46.455 255.075 46.740 ;
        RECT 257.075 46.455 257.255 46.905 ;
        RECT 260.845 46.455 261.025 46.905 ;
        RECT 263.025 46.880 263.205 46.905 ;
        RECT 263.025 46.740 263.775 46.880 ;
        RECT 265.905 46.740 266.675 46.880 ;
        RECT 263.025 46.455 263.815 46.740 ;
        RECT 254.285 46.440 254.925 46.455 ;
        RECT 263.175 46.440 263.815 46.455 ;
        RECT 265.865 46.480 266.675 46.740 ;
        RECT 266.975 46.480 267.155 46.880 ;
        RECT 265.865 46.440 266.505 46.480 ;
        RECT 270.510 46.460 270.690 46.910 ;
        RECT 270.990 46.460 273.545 46.910 ;
        RECT 274.025 46.460 274.205 46.910 ;
        RECT 22.045 45.970 22.445 46.150 ;
        RECT 63.250 45.160 63.680 45.660 ;
        RECT 73.680 45.160 74.110 45.660 ;
        RECT 74.890 45.160 75.320 45.660 ;
        RECT 85.320 45.160 85.750 45.660 ;
        RECT 86.530 45.160 86.960 45.660 ;
        RECT 96.960 45.160 97.390 45.660 ;
        RECT 98.170 45.160 98.600 45.660 ;
        RECT 108.600 45.160 109.030 45.660 ;
        RECT 109.810 45.160 110.240 45.660 ;
        RECT 120.240 45.160 120.670 45.660 ;
        RECT 13.695 44.860 14.145 45.040 ;
        RECT 22.045 44.360 22.445 44.540 ;
        RECT 38.095 43.890 38.545 44.070 ;
        RECT 39.495 43.890 39.945 44.070 ;
        RECT 40.895 43.890 41.345 44.070 ;
        RECT 42.295 43.890 42.745 44.070 ;
        RECT 47.425 43.890 48.425 44.070 ;
        RECT 50.185 43.890 51.185 44.070 ;
        RECT 38.095 43.315 42.745 43.890 ;
        RECT 47.435 43.660 48.415 43.890 ;
        RECT 50.365 43.660 51.005 43.890 ;
        RECT 53.930 43.690 54.430 44.120 ;
        RECT 55.250 43.690 55.750 44.120 ;
        RECT 56.570 43.690 57.070 44.120 ;
        RECT 57.890 43.690 58.390 44.120 ;
        RECT 59.210 43.690 59.710 44.120 ;
        RECT 60.530 43.690 61.030 44.120 ;
        RECT 63.250 43.840 63.680 44.340 ;
        RECT 73.680 43.840 74.110 44.340 ;
        RECT 74.890 43.840 75.320 44.340 ;
        RECT 85.320 43.840 85.750 44.340 ;
        RECT 86.530 43.840 86.960 44.340 ;
        RECT 96.960 43.840 97.390 44.340 ;
        RECT 98.170 43.840 98.600 44.340 ;
        RECT 108.600 43.840 109.030 44.340 ;
        RECT 109.810 43.840 110.240 44.340 ;
        RECT 120.240 43.840 120.670 44.340 ;
        RECT 172.180 43.815 172.310 44.080 ;
        RECT 172.690 43.815 172.820 44.080 ;
        RECT 172.180 43.515 172.820 43.815 ;
        RECT 63.250 42.520 63.680 43.020 ;
        RECT 73.680 42.520 74.110 43.020 ;
        RECT 74.890 42.520 75.320 43.020 ;
        RECT 85.320 42.520 85.750 43.020 ;
        RECT 86.530 42.520 86.960 43.020 ;
        RECT 96.960 42.520 97.390 43.020 ;
        RECT 98.170 42.520 98.600 43.020 ;
        RECT 108.600 42.520 109.030 43.020 ;
        RECT 109.810 42.520 110.240 43.020 ;
        RECT 120.240 42.520 120.670 43.020 ;
        RECT 178.050 42.705 180.000 42.885 ;
        RECT 164.505 42.425 164.635 42.605 ;
        RECT 165.525 42.425 165.655 42.605 ;
        RECT 166.545 42.425 166.675 42.605 ;
        RECT 178.195 42.450 179.855 42.705 ;
        RECT 165.525 42.125 165.825 42.425 ;
        RECT 21.915 41.430 22.755 41.730 ;
        RECT 13.155 41.045 13.795 41.345 ;
        RECT 13.425 40.860 13.555 41.045 ;
        RECT 22.625 40.910 22.755 41.430 ;
        RECT 63.250 41.200 63.680 41.700 ;
        RECT 73.680 41.200 74.110 41.700 ;
        RECT 74.890 41.200 75.320 41.700 ;
        RECT 85.320 41.200 85.750 41.700 ;
        RECT 86.530 41.200 86.960 41.700 ;
        RECT 96.960 41.200 97.390 41.700 ;
        RECT 98.170 41.200 98.600 41.700 ;
        RECT 108.600 41.200 109.030 41.700 ;
        RECT 109.810 41.200 110.240 41.700 ;
        RECT 120.240 41.200 120.670 41.700 ;
        RECT 183.085 41.515 185.085 41.945 ;
        RECT 13.425 39.940 13.555 40.120 ;
        RECT 63.250 39.880 63.680 40.380 ;
        RECT 73.680 39.880 74.110 40.380 ;
        RECT 74.890 39.880 75.320 40.380 ;
        RECT 85.320 39.880 85.750 40.380 ;
        RECT 86.530 39.880 86.960 40.380 ;
        RECT 96.960 39.880 97.390 40.380 ;
        RECT 98.170 39.880 98.600 40.380 ;
        RECT 108.600 39.880 109.030 40.380 ;
        RECT 109.810 39.880 110.240 40.380 ;
        RECT 120.240 39.880 120.670 40.380 ;
        RECT 123.630 40.090 124.630 40.200 ;
        RECT 125.350 40.090 129.350 40.200 ;
        RECT 130.350 40.090 134.350 40.200 ;
        RECT 135.350 40.090 139.350 40.200 ;
        RECT 140.070 40.090 141.070 40.200 ;
        RECT 22.625 39.610 22.755 39.790 ;
        RECT 123.630 39.755 141.070 40.090 ;
        RECT 172.180 39.170 172.820 39.470 ;
        RECT 172.180 38.925 172.310 39.170 ;
        RECT 172.690 38.925 172.820 39.170 ;
        RECT 176.520 39.080 176.820 39.720 ;
        RECT 176.595 38.610 176.745 39.080 ;
        RECT 178.980 39.075 179.280 39.715 ;
        RECT 179.150 38.560 179.280 39.075 ;
        RECT 176.595 38.180 176.745 38.460 ;
        RECT 179.150 37.860 179.280 38.040 ;
        RECT 172.180 37.445 172.310 37.625 ;
        RECT 172.690 37.445 172.820 37.625 ;
        RECT 44.300 31.650 44.480 33.650 ;
        RECT 54.480 31.650 55.450 33.650 ;
        RECT 65.450 31.650 65.630 33.650 ;
        RECT 54.660 31.270 55.270 31.650 ;
        RECT 44.300 29.270 44.480 31.270 ;
        RECT 54.480 29.270 55.450 31.270 ;
        RECT 65.450 29.270 65.630 31.270 ;
        RECT 67.635 29.570 67.815 31.570 ;
        RECT 77.815 29.570 79.500 31.570 ;
        RECT 89.500 29.570 89.680 31.570 ;
        RECT 54.660 28.890 55.270 29.270 ;
        RECT 44.300 26.890 44.480 28.890 ;
        RECT 54.480 26.890 55.450 28.890 ;
        RECT 65.450 26.890 65.630 28.890 ;
        RECT 77.995 28.400 79.320 29.570 ;
        RECT 54.660 26.510 55.270 26.890 ;
        RECT 44.300 24.510 44.480 26.510 ;
        RECT 54.480 24.510 55.450 26.510 ;
        RECT 65.450 24.510 65.630 26.510 ;
        RECT 67.635 26.400 67.815 28.400 ;
        RECT 77.815 26.400 79.500 28.400 ;
        RECT 89.500 26.400 89.680 28.400 ;
        RECT 252.810 23.810 252.940 23.990 ;
        RECT 253.320 23.810 253.450 23.990 ;
        RECT 253.830 23.810 253.960 23.990 ;
        RECT 254.940 23.810 255.070 23.990 ;
        RECT 259.085 23.810 259.215 23.990 ;
        RECT 260.105 23.810 260.235 23.990 ;
        RECT 261.215 23.810 261.345 23.990 ;
        RECT 265.870 23.810 266.000 23.990 ;
        RECT 266.380 23.810 266.510 23.990 ;
        RECT 267.490 23.810 267.620 23.990 ;
        RECT 272.655 23.810 272.785 23.990 ;
        RECT 273.765 23.810 273.895 23.990 ;
        RECT 252.810 22.510 252.940 22.970 ;
        RECT 253.320 22.510 253.450 22.970 ;
        RECT 253.830 22.510 253.960 22.970 ;
        RECT 254.940 22.530 255.070 22.690 ;
        RECT 252.770 22.210 253.070 22.510 ;
        RECT 253.320 22.210 253.650 22.510 ;
        RECT 253.830 22.210 254.130 22.510 ;
        RECT 252.810 21.860 252.940 22.210 ;
        RECT 253.320 21.860 253.450 22.210 ;
        RECT 253.830 21.860 253.960 22.210 ;
        RECT 254.940 22.200 255.275 22.530 ;
        RECT 259.085 22.510 259.215 22.970 ;
        RECT 260.105 22.510 260.235 22.970 ;
        RECT 261.215 22.530 261.345 22.690 ;
        RECT 259.045 22.210 259.345 22.510 ;
        RECT 260.105 22.210 260.405 22.510 ;
        RECT 254.940 21.960 255.070 22.200 ;
        RECT 259.085 21.860 259.215 22.210 ;
        RECT 260.105 21.860 260.235 22.210 ;
        RECT 261.215 22.200 261.550 22.530 ;
        RECT 265.870 22.510 266.000 22.970 ;
        RECT 266.380 22.510 266.510 22.970 ;
        RECT 267.490 22.530 267.620 22.690 ;
        RECT 265.870 22.210 266.200 22.510 ;
        RECT 266.380 22.210 266.680 22.510 ;
        RECT 261.215 21.960 261.345 22.200 ;
        RECT 265.870 21.860 266.000 22.210 ;
        RECT 266.380 21.860 266.510 22.210 ;
        RECT 267.490 22.200 267.825 22.530 ;
        RECT 272.655 22.510 272.785 22.970 ;
        RECT 273.765 22.530 273.895 22.690 ;
        RECT 272.655 22.210 272.955 22.510 ;
        RECT 267.490 21.960 267.620 22.200 ;
        RECT 272.655 21.860 272.785 22.210 ;
        RECT 273.765 22.200 274.100 22.530 ;
        RECT 273.765 21.960 273.895 22.200 ;
        RECT 252.810 21.040 252.940 21.220 ;
        RECT 253.320 21.040 253.450 21.220 ;
        RECT 253.830 21.040 253.960 21.220 ;
        RECT 254.940 21.040 255.070 21.220 ;
        RECT 259.085 21.040 259.215 21.220 ;
        RECT 260.105 21.040 260.235 21.220 ;
        RECT 261.215 21.040 261.345 21.220 ;
        RECT 265.870 21.040 266.000 21.220 ;
        RECT 266.380 21.040 266.510 21.220 ;
        RECT 267.490 21.040 267.620 21.220 ;
        RECT 272.655 21.040 272.785 21.220 ;
        RECT 273.765 21.040 273.895 21.220 ;
        RECT 254.940 19.680 255.070 19.860 ;
        RECT 259.595 19.680 259.725 19.860 ;
        RECT 261.215 19.680 261.345 19.860 ;
        RECT 265.360 19.680 265.490 19.860 ;
        RECT 267.490 19.680 267.620 19.860 ;
        RECT 271.635 19.680 271.765 19.860 ;
        RECT 272.145 19.680 272.275 19.860 ;
        RECT 273.765 19.680 273.895 19.860 ;
        RECT 254.940 18.700 255.070 18.940 ;
        RECT 254.940 18.370 255.275 18.700 ;
        RECT 259.595 18.690 259.725 19.040 ;
        RECT 261.215 18.700 261.345 18.940 ;
        RECT 259.595 18.390 259.925 18.690 ;
        RECT 254.940 18.210 255.070 18.370 ;
        RECT 259.595 17.930 259.725 18.390 ;
        RECT 261.215 18.370 261.550 18.700 ;
        RECT 265.360 18.690 265.490 19.040 ;
        RECT 267.490 18.700 267.620 18.940 ;
        RECT 265.320 18.390 265.620 18.690 ;
        RECT 261.215 18.210 261.345 18.370 ;
        RECT 265.360 17.930 265.490 18.390 ;
        RECT 267.490 18.370 267.825 18.700 ;
        RECT 271.635 18.690 271.765 19.040 ;
        RECT 272.145 18.690 272.275 19.040 ;
        RECT 273.765 18.700 273.895 18.940 ;
        RECT 271.595 18.390 271.895 18.690 ;
        RECT 272.145 18.390 272.475 18.690 ;
        RECT 267.490 18.210 267.620 18.370 ;
        RECT 271.635 17.930 271.765 18.390 ;
        RECT 272.145 17.930 272.275 18.390 ;
        RECT 273.765 18.370 274.100 18.700 ;
        RECT 273.765 18.210 273.895 18.370 ;
        RECT 45.385 17.330 45.815 17.830 ;
        RECT 54.815 17.330 55.245 17.830 ;
        RECT 62.750 17.155 62.930 17.605 ;
        RECT 72.930 17.155 74.170 17.605 ;
        RECT 84.170 17.155 85.410 17.605 ;
        RECT 95.410 17.155 96.650 17.605 ;
        RECT 106.650 17.155 107.890 17.605 ;
        RECT 117.890 17.155 119.130 17.605 ;
        RECT 129.130 17.155 130.370 17.605 ;
        RECT 140.370 17.155 140.550 17.605 ;
        RECT 44.195 16.665 44.695 17.095 ;
        RECT 55.935 16.665 56.435 17.095 ;
        RECT 73.110 16.775 73.990 17.155 ;
        RECT 84.350 16.775 85.230 17.155 ;
        RECT 95.590 16.775 96.470 17.155 ;
        RECT 106.830 16.775 107.710 17.155 ;
        RECT 118.070 16.775 118.950 17.155 ;
        RECT 129.310 16.775 130.190 17.155 ;
        RECT 254.940 16.910 255.070 17.090 ;
        RECT 259.595 16.910 259.725 17.090 ;
        RECT 261.215 16.910 261.345 17.090 ;
        RECT 265.360 16.910 265.490 17.090 ;
        RECT 267.490 16.910 267.620 17.090 ;
        RECT 271.635 16.910 271.765 17.090 ;
        RECT 272.145 16.910 272.275 17.090 ;
        RECT 273.765 16.910 273.895 17.090 ;
        RECT 54.815 16.010 55.245 16.510 ;
        RECT 62.750 16.325 62.930 16.775 ;
        RECT 72.930 16.325 74.170 16.775 ;
        RECT 84.170 16.325 85.410 16.775 ;
        RECT 95.410 16.325 96.650 16.775 ;
        RECT 106.650 16.325 107.890 16.775 ;
        RECT 117.890 16.325 119.130 16.775 ;
        RECT 129.130 16.325 130.370 16.775 ;
        RECT 140.370 16.325 140.550 16.775 ;
        RECT 73.110 15.945 73.990 16.325 ;
        RECT 84.350 15.945 85.230 16.325 ;
        RECT 95.590 15.945 96.470 16.325 ;
        RECT 106.830 15.945 107.710 16.325 ;
        RECT 118.070 15.945 118.950 16.325 ;
        RECT 129.310 15.945 130.190 16.325 ;
        RECT 62.750 15.495 62.930 15.945 ;
        RECT 72.930 15.495 74.170 15.945 ;
        RECT 84.170 15.495 85.410 15.945 ;
        RECT 95.410 15.495 96.650 15.945 ;
        RECT 106.650 15.495 107.890 15.945 ;
        RECT 117.890 15.495 119.130 15.945 ;
        RECT 129.130 15.495 130.370 15.945 ;
        RECT 140.370 15.495 140.550 15.945 ;
        RECT 45.385 14.690 45.815 15.190 ;
        RECT 54.815 14.690 55.245 15.190 ;
        RECT 73.110 15.115 73.990 15.495 ;
        RECT 84.350 15.115 85.230 15.495 ;
        RECT 95.590 15.115 96.470 15.495 ;
        RECT 106.830 15.115 107.710 15.495 ;
        RECT 118.070 15.115 118.950 15.495 ;
        RECT 129.310 15.115 130.190 15.495 ;
        RECT 62.750 14.665 62.930 15.115 ;
        RECT 72.930 14.665 74.170 15.115 ;
        RECT 84.170 14.665 85.410 15.115 ;
        RECT 95.410 14.665 96.650 15.115 ;
        RECT 106.650 14.665 107.890 15.115 ;
        RECT 117.890 14.665 119.130 15.115 ;
        RECT 129.130 14.665 130.370 15.115 ;
        RECT 140.370 14.665 140.550 15.115 ;
        RECT 73.110 14.285 73.990 14.665 ;
        RECT 84.350 14.285 85.230 14.665 ;
        RECT 95.590 14.285 96.470 14.665 ;
        RECT 106.830 14.285 107.710 14.665 ;
        RECT 118.070 14.285 118.950 14.665 ;
        RECT 129.310 14.285 130.190 14.665 ;
        RECT 44.195 13.235 44.695 13.665 ;
        RECT 45.385 13.370 45.815 13.870 ;
        RECT 62.750 13.835 62.930 14.285 ;
        RECT 72.930 13.835 74.170 14.285 ;
        RECT 84.170 13.835 85.410 14.285 ;
        RECT 95.410 13.835 96.650 14.285 ;
        RECT 106.650 13.835 107.890 14.285 ;
        RECT 117.890 13.835 119.130 14.285 ;
        RECT 129.130 13.835 130.370 14.285 ;
        RECT 140.370 13.835 140.550 14.285 ;
        RECT 55.935 13.235 56.435 13.665 ;
        RECT 73.110 13.455 73.990 13.835 ;
        RECT 84.350 13.455 85.230 13.835 ;
        RECT 95.590 13.455 96.470 13.835 ;
        RECT 106.830 13.455 107.710 13.835 ;
        RECT 118.070 13.455 118.950 13.835 ;
        RECT 129.310 13.455 130.190 13.835 ;
        RECT 62.750 13.005 62.930 13.455 ;
        RECT 72.930 13.005 74.170 13.455 ;
        RECT 84.170 13.005 85.410 13.455 ;
        RECT 95.410 13.005 96.650 13.455 ;
        RECT 106.650 13.005 107.890 13.455 ;
        RECT 117.890 13.005 119.130 13.455 ;
        RECT 129.130 13.005 130.370 13.455 ;
        RECT 140.370 13.005 140.550 13.455 ;
        RECT 73.110 12.625 73.990 13.005 ;
        RECT 84.350 12.625 85.230 13.005 ;
        RECT 95.590 12.625 96.470 13.005 ;
        RECT 106.830 12.625 107.710 13.005 ;
        RECT 118.070 12.625 118.950 13.005 ;
        RECT 129.310 12.625 130.190 13.005 ;
        RECT 62.750 12.175 62.930 12.625 ;
        RECT 72.930 12.175 74.170 12.625 ;
        RECT 84.170 12.175 85.410 12.625 ;
        RECT 95.410 12.175 96.650 12.625 ;
        RECT 106.650 12.175 107.890 12.625 ;
        RECT 117.890 12.175 119.130 12.625 ;
        RECT 129.130 12.175 130.370 12.625 ;
        RECT 140.370 12.175 140.550 12.625 ;
      LAYER Metal1 ;
        RECT 151.225 92.510 153.185 92.810 ;
        RECT 153.425 92.510 157.585 92.810 ;
        RECT 157.825 92.510 161.985 92.810 ;
        RECT 162.225 92.510 166.385 92.810 ;
        RECT 166.625 92.510 170.785 92.810 ;
        RECT 171.025 92.510 175.185 92.810 ;
        RECT 175.425 92.510 179.585 92.810 ;
        RECT 179.825 92.510 183.985 92.810 ;
        RECT 184.225 92.510 188.385 92.810 ;
        RECT 188.625 92.510 192.785 92.810 ;
        RECT 193.025 92.510 197.185 92.810 ;
        RECT 197.425 92.510 201.585 92.810 ;
        RECT 201.825 92.510 205.985 92.810 ;
        RECT 206.225 92.510 210.385 92.810 ;
        RECT 210.625 92.510 214.785 92.810 ;
        RECT 215.025 92.510 219.185 92.810 ;
        RECT 219.425 92.510 223.585 92.810 ;
        RECT 248.990 92.150 249.490 93.600 ;
        RECT 251.805 92.150 252.305 93.600 ;
        RECT 265.795 92.150 266.295 93.600 ;
        RECT 268.610 92.150 269.110 93.600 ;
        RECT 128.330 91.465 128.490 91.475 ;
        RECT 16.165 91.020 16.325 91.070 ;
        RECT 13.245 90.860 16.325 91.020 ;
        RECT 13.245 87.755 13.405 90.860 ;
        RECT 16.165 88.390 16.325 90.860 ;
        RECT 19.925 88.060 20.085 90.390 ;
        RECT 23.685 88.060 23.845 90.390 ;
        RECT 27.445 88.060 27.605 90.390 ;
        RECT 19.925 87.900 27.605 88.060 ;
        RECT 13.185 87.545 13.475 87.755 ;
        RECT 21.410 87.715 21.570 87.900 ;
        RECT 21.345 87.505 21.635 87.715 ;
        RECT 40.030 85.310 40.190 90.590 ;
        RECT 40.650 86.750 40.810 90.590 ;
        RECT 52.740 87.665 52.900 91.465 ;
        RECT 40.625 85.640 40.835 86.750 ;
        RECT 52.715 86.555 52.925 87.665 ;
        RECT 52.740 86.465 52.900 86.555 ;
        RECT 40.650 85.590 40.810 85.640 ;
        RECT 17.530 84.660 21.990 84.870 ;
        RECT 17.530 71.505 17.690 84.660 ;
        RECT 18.910 78.345 19.070 83.570 ;
        RECT 20.450 79.300 20.610 83.570 ;
        RECT 19.750 79.070 20.610 79.300 ;
        RECT 19.750 78.540 20.040 79.070 ;
        RECT 18.910 78.165 20.610 78.345 ;
        RECT 18.910 71.130 19.070 76.005 ;
        RECT 18.845 70.920 19.135 71.130 ;
        RECT 20.450 70.695 20.610 78.165 ;
        RECT 21.830 71.505 21.990 84.660 ;
        RECT 31.340 77.465 31.500 84.965 ;
        RECT 39.085 84.810 41.725 85.310 ;
        RECT 57.500 85.010 57.660 85.295 ;
        RECT 40.030 84.785 40.810 84.810 ;
        RECT 40.030 84.435 40.190 84.490 ;
        RECT 40.010 83.325 40.220 84.435 ;
        RECT 40.030 80.615 40.190 83.325 ;
        RECT 40.650 80.615 40.810 84.785 ;
        RECT 57.480 83.900 57.690 85.010 ;
        RECT 57.500 81.675 57.660 83.900 ;
        RECT 40.005 79.505 40.215 80.615 ;
        RECT 40.620 79.505 40.830 80.615 ;
        RECT 57.480 80.565 57.690 81.675 ;
        RECT 88.160 81.285 88.320 91.465 ;
        RECT 91.040 81.285 92.560 81.315 ;
        RECT 92.920 81.285 93.080 91.465 ;
        RECT 97.680 81.285 97.840 91.465 ;
        RECT 127.880 90.975 128.490 91.465 ;
        RECT 248.930 91.450 249.550 92.150 ;
        RECT 251.750 91.450 252.370 92.150 ;
        RECT 265.730 91.450 266.350 92.150 ;
        RECT 268.550 91.450 269.170 92.150 ;
        RECT 119.480 88.410 120.180 89.030 ;
        RECT 88.160 81.125 97.840 81.285 ;
        RECT 118.885 86.865 119.175 87.075 ;
        RECT 91.040 81.105 92.560 81.125 ;
        RECT 57.500 80.295 57.660 80.565 ;
        RECT 40.030 79.490 40.190 79.505 ;
        RECT 40.650 79.490 40.810 79.505 ;
        RECT 85.540 79.465 86.240 79.475 ;
        RECT 85.540 79.265 98.805 79.465 ;
        RECT 85.180 78.765 98.065 78.965 ;
        RECT 57.395 78.420 57.685 78.430 ;
        RECT 51.800 78.220 57.685 78.420 ;
        RECT 51.800 78.015 52.000 78.220 ;
        RECT 51.755 77.805 52.045 78.015 ;
        RECT 51.800 77.790 52.000 77.805 ;
        RECT 31.320 75.125 31.530 77.465 ;
        RECT 53.950 76.730 55.730 76.990 ;
        RECT 56.590 76.730 58.370 76.990 ;
        RECT 59.230 76.730 61.010 76.990 ;
        RECT 38.675 76.555 39.375 76.610 ;
        RECT 35.995 76.395 44.845 76.555 ;
        RECT 31.340 74.965 31.500 75.125 ;
        RECT 20.385 70.485 20.675 70.695 ;
        RECT 10.525 70.230 10.735 70.290 ;
        RECT 7.195 70.070 10.735 70.230 ;
        RECT 10.525 70.000 10.735 70.070 ;
        RECT 27.955 67.980 28.165 73.120 ;
        RECT 25.535 67.730 28.165 67.980 ;
        RECT 17.055 64.710 17.755 64.920 ;
        RECT 13.210 64.160 14.410 64.320 ;
        RECT 14.120 63.700 14.410 64.160 ;
        RECT 14.850 64.160 17.335 64.320 ;
        RECT 14.850 63.480 15.015 64.160 ;
        RECT 13.210 63.320 15.015 63.480 ;
        RECT 15.450 63.480 15.740 63.910 ;
        RECT 23.435 63.755 23.645 64.455 ;
        RECT 15.450 63.320 16.650 63.480 ;
        RECT 20.325 62.760 22.785 62.920 ;
        RECT 20.325 59.160 20.485 62.760 ;
        RECT 20.325 59.000 22.785 59.160 ;
        RECT 13.605 57.620 15.280 57.780 ;
        RECT 15.120 55.420 15.280 57.620 ;
        RECT 19.830 56.515 20.040 56.565 ;
        RECT 20.325 56.515 20.485 59.000 ;
        RECT 19.830 56.325 20.485 56.515 ;
        RECT 19.830 56.275 20.040 56.325 ;
        RECT 15.475 55.575 15.685 56.275 ;
        RECT 13.605 55.325 15.280 55.420 ;
        RECT 20.325 55.400 20.485 56.325 ;
        RECT 13.605 55.260 15.715 55.325 ;
        RECT 15.120 55.035 15.715 55.260 ;
        RECT 20.325 55.240 22.785 55.400 ;
        RECT 15.120 53.060 15.280 55.035 ;
        RECT 13.605 52.900 15.280 53.060 ;
        RECT 14.205 49.500 17.630 49.545 ;
        RECT 7.695 49.470 9.215 49.500 ;
        RECT 6.460 49.310 10.195 49.470 ;
        RECT 7.695 49.290 9.215 49.310 ;
        RECT 13.610 49.290 17.630 49.500 ;
        RECT 14.205 49.230 17.630 49.290 ;
        RECT 17.300 48.730 17.630 49.230 ;
        RECT 25.535 48.730 25.800 67.730 ;
        RECT 35.995 54.655 36.155 76.395 ;
        RECT 39.225 54.810 39.385 64.970 ;
        RECT 39.170 54.790 39.460 54.810 ;
        RECT 41.455 54.790 41.615 64.970 ;
        RECT 35.945 54.365 36.155 54.655 ;
        RECT 17.300 48.415 25.800 48.730 ;
        RECT 13.605 46.745 14.305 46.955 ;
        RECT 21.860 46.745 22.560 46.955 ;
        RECT 14.255 45.535 14.415 46.090 ;
        RECT 21.775 45.535 21.935 45.970 ;
        RECT 14.255 45.245 15.225 45.535 ;
        RECT 20.810 45.245 21.935 45.535 ;
        RECT 14.255 45.040 14.415 45.245 ;
        RECT 21.775 44.540 21.935 45.245 ;
        RECT 35.995 43.545 36.155 54.365 ;
        RECT 38.175 54.295 38.465 54.730 ;
        RECT 39.170 54.630 41.615 54.790 ;
        RECT 39.170 54.600 39.460 54.630 ;
        RECT 42.375 54.295 42.665 54.730 ;
        RECT 44.685 54.655 44.845 76.395 ;
        RECT 85.180 66.575 85.340 78.765 ;
        RECT 85.555 78.130 85.715 78.580 ;
        RECT 85.535 76.610 85.745 78.130 ;
        RECT 90.935 77.770 91.095 78.580 ;
        RECT 92.525 77.770 92.685 78.580 ;
        RECT 85.555 68.580 85.715 76.610 ;
        RECT 86.665 68.200 89.005 68.410 ;
        RECT 89.530 67.710 90.480 67.920 ;
        RECT 89.530 67.700 89.765 67.710 ;
        RECT 86.655 67.490 89.765 67.700 ;
        RECT 85.555 66.575 85.715 67.340 ;
        RECT 85.180 65.720 85.715 66.575 ;
        RECT 50.335 65.690 51.035 65.715 ;
        RECT 47.455 65.530 51.035 65.690 ;
        RECT 48.535 54.970 48.695 65.530 ;
        RECT 50.335 65.505 51.035 65.530 ;
        RECT 53.950 59.680 54.410 61.020 ;
        RECT 55.270 60.760 57.050 61.020 ;
        RECT 57.910 60.760 59.690 61.020 ;
        RECT 55.270 59.680 57.050 59.940 ;
        RECT 57.910 59.680 59.690 59.940 ;
        RECT 85.555 59.705 85.715 65.720 ;
        RECT 85.530 57.775 85.740 59.705 ;
        RECT 85.555 57.340 85.715 57.775 ;
        RECT 90.935 57.340 92.685 77.770 ;
        RECT 97.905 68.580 98.065 78.765 ;
        RECT 93.980 68.200 96.950 68.410 ;
        RECT 93.980 67.920 94.180 68.200 ;
        RECT 93.090 67.710 94.180 67.920 ;
        RECT 94.600 67.490 96.940 67.700 ;
        RECT 97.905 66.785 98.065 67.340 ;
        RECT 98.645 66.785 98.805 79.265 ;
        RECT 97.905 65.710 98.805 66.785 ;
        RECT 97.905 59.705 98.065 65.710 ;
        RECT 118.885 65.525 119.160 86.865 ;
        RECT 119.480 67.415 119.755 88.410 ;
        RECT 127.880 87.085 128.080 90.975 ;
        RECT 248.935 90.615 253.495 90.620 ;
        RECT 264.605 90.615 269.165 90.620 ;
        RECT 128.735 90.110 131.375 90.610 ;
        RECT 133.245 90.460 135.885 90.610 ;
        RECT 136.795 90.460 137.005 90.495 ;
        RECT 133.245 90.230 137.005 90.460 ;
        RECT 248.935 90.405 253.545 90.615 ;
        RECT 264.555 90.405 269.165 90.615 ;
        RECT 248.935 90.395 253.495 90.405 ;
        RECT 264.605 90.395 269.165 90.405 ;
        RECT 133.245 90.110 135.885 90.230 ;
        RECT 128.880 90.095 131.220 90.110 ;
        RECT 133.440 90.095 135.780 90.110 ;
        RECT 136.185 89.120 136.395 89.820 ;
        RECT 136.795 89.795 137.005 90.230 ;
        RECT 245.650 89.910 252.365 90.175 ;
        RECT 265.735 89.910 272.450 90.175 ;
        RECT 128.735 88.370 131.375 88.870 ;
        RECT 133.235 88.740 135.875 88.870 ;
        RECT 136.795 88.740 137.005 89.230 ;
        RECT 133.235 88.525 137.005 88.740 ;
        RECT 249.030 88.835 253.555 89.060 ;
        RECT 264.545 88.835 269.070 89.060 ;
        RECT 133.235 88.370 135.875 88.525 ;
        RECT 128.310 87.390 128.520 88.090 ;
        RECT 136.210 87.085 136.370 87.995 ;
        RECT 245.655 87.120 245.865 87.715 ;
        RECT 127.880 87.080 131.045 87.085 ;
        RECT 133.625 87.080 136.370 87.085 ;
        RECT 127.880 86.870 131.350 87.080 ;
        RECT 133.335 86.870 136.370 87.080 ;
        RECT 244.075 86.960 247.410 87.120 ;
        RECT 127.880 86.865 131.045 86.870 ;
        RECT 133.625 86.865 136.370 86.870 ;
        RECT 120.190 86.385 120.480 86.595 ;
        RECT 244.980 86.510 246.500 86.720 ;
        RECT 119.480 67.205 119.770 67.415 ;
        RECT 97.885 57.775 98.095 59.705 ;
        RECT 97.905 57.340 98.065 57.775 ;
        RECT 119.480 55.315 119.755 67.205 ;
        RECT 120.190 55.315 120.465 86.385 ;
        RECT 245.485 84.580 245.820 86.510 ;
        RECT 249.030 84.580 249.355 88.835 ;
        RECT 253.200 87.945 253.410 88.835 ;
        RECT 264.690 87.945 264.900 88.835 ;
        RECT 251.170 87.090 251.870 87.120 ;
        RECT 255.100 87.115 255.800 87.120 ;
        RECT 262.300 87.115 263.000 87.120 ;
        RECT 251.125 86.930 251.870 87.090 ;
        RECT 255.075 86.955 257.075 87.115 ;
        RECT 261.025 86.955 263.025 87.115 ;
        RECT 266.230 87.090 266.930 87.120 ;
        RECT 251.170 86.910 251.870 86.930 ;
        RECT 255.100 86.910 255.800 86.955 ;
        RECT 262.300 86.910 263.000 86.955 ;
        RECT 266.230 86.930 266.975 87.090 ;
        RECT 266.230 86.910 266.930 86.930 ;
        RECT 251.565 86.425 252.265 86.635 ;
        RECT 254.255 86.425 254.955 86.635 ;
        RECT 263.145 86.425 263.845 86.635 ;
        RECT 265.835 86.425 266.535 86.635 ;
        RECT 245.485 84.340 249.355 84.580 ;
        RECT 268.745 84.580 269.070 88.835 ;
        RECT 272.235 87.120 272.445 87.715 ;
        RECT 270.690 86.960 274.025 87.120 ;
        RECT 271.600 86.510 273.120 86.720 ;
        RECT 272.280 84.580 272.615 86.510 ;
        RECT 268.745 84.340 272.615 84.580 ;
        RECT 130.330 82.040 130.490 84.200 ;
        RECT 130.330 81.830 131.260 82.040 ;
        RECT 134.210 81.665 134.370 84.200 ;
        RECT 133.055 81.485 134.370 81.665 ;
        RECT 240.070 83.255 240.270 83.260 ;
        RECT 277.825 83.255 278.025 83.260 ;
        RECT 240.070 82.965 240.280 83.255 ;
        RECT 277.815 82.965 278.025 83.255 ;
        RECT 133.055 81.340 133.265 81.485 ;
        RECT 133.480 81.140 134.370 81.300 ;
        RECT 130.330 80.850 130.490 80.960 ;
        RECT 134.210 80.850 134.370 81.140 ;
        RECT 130.305 78.510 130.515 80.850 ;
        RECT 134.185 78.510 134.395 80.850 ;
        RECT 130.330 78.010 134.370 78.230 ;
        RECT 130.330 75.720 130.490 78.010 ;
        RECT 131.710 75.720 132.990 77.720 ;
        RECT 134.210 77.345 134.370 78.010 ;
        RECT 134.180 75.825 134.390 77.345 ;
        RECT 134.210 75.720 134.370 75.825 ;
        RECT 131.990 73.420 132.690 73.720 ;
        RECT 122.440 73.120 142.260 73.420 ;
        RECT 120.880 67.730 121.170 67.940 ;
        RECT 120.880 65.735 121.140 67.730 ;
        RECT 122.440 67.080 129.120 73.120 ;
        RECT 129.580 72.035 129.740 72.100 ;
        RECT 129.555 70.515 129.765 72.035 ;
        RECT 129.580 68.100 129.740 70.515 ;
        RECT 130.070 67.735 131.590 67.945 ;
        RECT 131.960 67.080 132.740 73.120 ;
        RECT 133.070 72.255 134.590 72.465 ;
        RECT 134.960 69.660 135.120 72.100 ;
        RECT 134.935 68.140 135.145 69.660 ;
        RECT 134.960 68.100 135.120 68.140 ;
        RECT 135.580 67.080 142.260 73.120 ;
        RECT 122.440 66.780 142.260 67.080 ;
        RECT 121.505 66.440 122.240 66.650 ;
        RECT 120.860 65.525 121.150 65.735 ;
        RECT 121.505 56.015 121.780 66.440 ;
        RECT 124.825 66.100 125.205 66.780 ;
        RECT 127.685 66.100 128.100 66.780 ;
        RECT 130.985 66.100 131.400 66.780 ;
        RECT 137.545 66.100 138.060 66.780 ;
        RECT 140.465 66.100 140.850 66.780 ;
        RECT 122.220 57.280 142.480 66.100 ;
        RECT 121.505 55.315 121.985 56.015 ;
        RECT 68.570 54.740 115.050 55.040 ;
        RECT 68.570 54.715 80.250 54.740 ;
        RECT 44.685 54.365 44.895 54.655 ;
        RECT 44.685 43.545 44.845 54.365 ;
        RECT 62.230 50.075 80.250 54.715 ;
        RECT 80.930 53.475 81.090 53.720 ;
        RECT 80.905 52.775 81.115 53.475 ;
        RECT 80.930 52.540 81.090 52.775 ;
        RECT 80.930 52.380 90.760 52.540 ;
        RECT 90.540 52.035 90.760 52.380 ;
        RECT 90.300 51.825 91.000 52.035 ;
        RECT 80.930 51.590 81.090 51.680 ;
        RECT 80.910 50.890 81.120 51.590 ;
        RECT 80.930 50.680 81.090 50.890 ;
        RECT 68.570 49.660 80.250 50.075 ;
        RECT 91.310 49.660 92.310 54.740 ;
        RECT 103.370 54.415 115.050 54.740 ;
        RECT 115.955 54.415 121.525 54.715 ;
        RECT 102.530 53.475 102.690 53.720 ;
        RECT 102.505 52.775 102.715 53.475 ;
        RECT 102.530 52.720 102.690 52.775 ;
        RECT 92.675 52.030 93.375 52.035 ;
        RECT 92.675 52.020 94.495 52.030 ;
        RECT 92.675 51.860 102.690 52.020 ;
        RECT 92.675 51.830 94.495 51.860 ;
        RECT 92.675 51.825 93.375 51.830 ;
        RECT 102.530 50.680 102.690 51.860 ;
        RECT 103.370 50.410 116.255 54.415 ;
        RECT 103.370 49.660 115.050 50.410 ;
        RECT 115.955 50.375 116.255 50.410 ;
        RECT 120.225 50.375 120.385 53.395 ;
        RECT 121.225 50.375 121.525 54.415 ;
        RECT 115.955 50.075 121.525 50.375 ;
        RECT 68.570 49.300 115.050 49.660 ;
        RECT 62.270 49.000 121.650 49.300 ;
        RECT 50.335 43.890 51.035 43.915 ;
        RECT 47.455 43.730 51.035 43.890 ;
        RECT 50.335 43.705 51.035 43.730 ;
        RECT 53.950 43.710 55.730 43.970 ;
        RECT 56.590 43.710 58.370 43.970 ;
        RECT 59.230 43.710 61.010 43.970 ;
        RECT 35.995 43.385 44.845 43.545 ;
        RECT 21.885 41.475 22.585 41.685 ;
        RECT 13.125 41.090 13.825 41.300 ;
        RECT 62.270 39.180 62.570 49.000 ;
        RECT 63.270 47.820 74.090 49.000 ;
        POLYGON 74.910 48.020 74.910 47.880 74.770 47.880 ;
        RECT 74.910 47.880 75.170 48.280 ;
        POLYGON 74.770 47.880 74.770 47.820 74.710 47.820 ;
        RECT 74.770 47.820 75.170 47.880 ;
        RECT 85.470 47.820 85.730 48.280 ;
        RECT 86.550 47.820 97.370 49.000 ;
        RECT 98.190 47.820 98.450 48.280 ;
        RECT 108.750 47.820 109.010 48.280 ;
        POLYGON 109.010 48.040 109.230 47.820 109.010 47.820 ;
        RECT 109.830 47.820 120.650 49.000 ;
        POLYGON 74.710 47.820 74.710 47.420 74.310 47.420 ;
        RECT 74.710 47.420 74.770 47.820 ;
        POLYGON 74.770 47.820 75.170 47.820 74.770 47.420 ;
        POLYGON 108.770 47.820 109.170 47.820 109.170 47.420 ;
        RECT 109.170 47.420 109.230 47.820 ;
        POLYGON 74.310 47.420 74.310 46.960 73.850 46.960 ;
        POLYGON 74.310 47.420 74.770 47.420 74.310 46.960 ;
        POLYGON 109.170 47.420 109.230 47.420 109.230 47.360 ;
        POLYGON 109.230 47.820 109.690 47.360 109.230 47.360 ;
        POLYGON 109.230 47.360 109.630 47.360 109.630 46.960 ;
        RECT 109.630 46.960 109.690 47.360 ;
        POLYGON 109.690 47.360 110.090 46.960 109.690 46.960 ;
        RECT 63.270 46.500 63.530 46.960 ;
        RECT 73.830 46.830 74.180 46.960 ;
        POLYGON 74.180 46.960 74.310 46.960 74.180 46.830 ;
        RECT 73.830 46.500 74.090 46.830 ;
        POLYGON 74.090 46.830 74.180 46.830 74.090 46.740 ;
        POLYGON 74.910 46.700 74.910 46.560 74.770 46.560 ;
        RECT 74.910 46.560 75.170 46.960 ;
        POLYGON 74.770 46.560 74.770 46.500 74.710 46.500 ;
        RECT 74.770 46.500 75.170 46.560 ;
        POLYGON 74.710 46.500 74.710 46.100 74.310 46.100 ;
        RECT 74.710 46.100 74.770 46.500 ;
        POLYGON 74.770 46.500 75.170 46.500 74.770 46.100 ;
        POLYGON 74.310 46.100 74.310 45.640 73.850 45.640 ;
        POLYGON 74.310 46.100 74.770 46.100 74.310 45.640 ;
        RECT 63.270 43.860 63.530 45.640 ;
        RECT 73.830 45.180 74.090 45.640 ;
        POLYGON 74.090 45.640 74.310 45.640 74.090 45.420 ;
        RECT 62.810 42.535 63.530 43.000 ;
        RECT 73.830 42.540 74.090 44.320 ;
        RECT 74.910 43.860 75.170 45.640 ;
        RECT 85.470 45.180 85.730 46.960 ;
        RECT 86.550 45.180 86.810 46.960 ;
        RECT 97.110 46.500 98.450 46.960 ;
        RECT 62.810 39.415 63.070 42.535 ;
        RECT 63.270 41.220 63.530 41.680 ;
        RECT 73.830 41.220 74.090 41.680 ;
        POLYGON 74.090 41.440 74.310 41.220 74.090 41.220 ;
        RECT 74.910 41.220 75.170 43.000 ;
        RECT 85.470 42.540 85.730 44.320 ;
        RECT 86.550 42.540 86.810 44.320 ;
        RECT 97.110 43.860 97.370 45.640 ;
        RECT 98.190 43.860 98.450 45.640 ;
        RECT 108.750 45.180 109.010 46.960 ;
        POLYGON 109.630 46.960 109.715 46.960 109.715 46.875 ;
        RECT 109.715 46.875 110.090 46.960 ;
        POLYGON 109.715 46.875 109.760 46.875 109.760 46.830 ;
        RECT 109.760 46.830 110.090 46.875 ;
        POLYGON 109.760 46.830 109.830 46.830 109.830 46.760 ;
        RECT 109.830 46.500 110.090 46.830 ;
        RECT 120.390 46.435 120.650 46.960 ;
        RECT 120.205 45.735 120.825 46.435 ;
        RECT 85.470 41.220 86.810 41.680 ;
        RECT 97.110 41.220 97.370 43.000 ;
        RECT 98.190 41.220 98.450 43.000 ;
        RECT 108.750 42.540 109.010 44.320 ;
        RECT 109.830 43.860 110.090 45.640 ;
        RECT 120.390 45.180 120.650 45.735 ;
        POLYGON 109.830 42.740 109.830 42.540 109.630 42.540 ;
        RECT 109.830 42.540 110.090 43.000 ;
        RECT 120.390 42.540 120.650 44.320 ;
        POLYGON 109.630 42.540 109.630 42.140 109.230 42.140 ;
        RECT 109.630 42.140 109.690 42.540 ;
        POLYGON 109.690 42.540 110.090 42.540 109.690 42.140 ;
        POLYGON 109.230 42.140 109.230 41.680 108.770 41.680 ;
        POLYGON 109.230 42.140 109.690 42.140 109.230 41.680 ;
        RECT 108.750 41.220 109.010 41.680 ;
        POLYGON 109.010 41.680 109.230 41.680 109.010 41.460 ;
        POLYGON 109.830 41.420 109.830 41.280 109.690 41.280 ;
        RECT 109.830 41.280 110.090 41.680 ;
        POLYGON 109.690 41.280 109.690 41.220 109.630 41.220 ;
        RECT 109.690 41.220 110.090 41.280 ;
        POLYGON 73.850 41.220 74.310 41.220 74.310 40.760 ;
        POLYGON 74.310 41.220 74.770 40.760 74.310 40.760 ;
        POLYGON 109.630 41.220 109.630 40.820 109.230 40.820 ;
        RECT 109.630 40.820 109.690 41.220 ;
        POLYGON 109.690 41.220 110.090 41.220 109.690 40.820 ;
        POLYGON 109.230 40.820 109.230 40.760 109.170 40.760 ;
        POLYGON 74.310 40.760 74.710 40.760 74.710 40.360 ;
        RECT 74.710 40.360 74.770 40.760 ;
        POLYGON 74.770 40.760 75.170 40.360 74.770 40.360 ;
        POLYGON 109.170 40.760 109.170 40.360 108.770 40.360 ;
        RECT 109.170 40.360 109.230 40.760 ;
        POLYGON 109.230 40.820 109.690 40.820 109.230 40.360 ;
        RECT 120.390 40.360 120.650 41.680 ;
        RECT 63.270 39.180 74.090 40.360 ;
        POLYGON 74.710 40.360 74.795 40.360 74.795 40.275 ;
        RECT 74.795 40.275 75.170 40.360 ;
        POLYGON 74.795 40.275 74.910 40.275 74.910 40.160 ;
        RECT 74.910 39.900 75.170 40.275 ;
        RECT 85.470 39.900 85.730 40.360 ;
        RECT 86.550 39.180 97.370 40.360 ;
        RECT 98.190 39.900 98.450 40.360 ;
        RECT 108.750 40.275 109.145 40.360 ;
        POLYGON 109.145 40.360 109.230 40.360 109.145 40.275 ;
        RECT 108.750 39.900 109.010 40.275 ;
        POLYGON 109.010 40.275 109.145 40.275 109.010 40.140 ;
        RECT 109.830 39.180 120.650 40.360 ;
        RECT 121.350 39.180 121.650 49.000 ;
        RECT 122.220 46.990 125.240 57.280 ;
        RECT 129.460 48.560 129.620 56.240 ;
        RECT 130.080 56.025 130.240 56.240 ;
        RECT 130.055 53.685 130.265 56.025 ;
        RECT 125.690 48.400 129.620 48.560 ;
        RECT 130.080 48.560 130.240 53.685 ;
        RECT 134.460 48.740 134.620 57.280 ;
        RECT 135.080 56.025 135.240 56.240 ;
        RECT 135.055 53.685 135.265 56.025 ;
        RECT 135.080 48.560 135.240 53.685 ;
        RECT 130.080 48.400 134.010 48.560 ;
        RECT 135.080 48.400 139.010 48.560 ;
        RECT 129.460 48.040 129.620 48.400 ;
        RECT 135.080 48.040 135.240 48.400 ;
        RECT 129.460 47.880 135.240 48.040 ;
        RECT 129.460 46.990 129.620 47.700 ;
        RECT 130.080 46.990 130.240 47.700 ;
        RECT 134.460 46.990 134.620 47.700 ;
        RECT 135.080 46.990 135.240 47.700 ;
        RECT 139.460 46.990 142.480 57.280 ;
        RECT 151.225 53.640 155.385 53.940 ;
        RECT 155.625 53.640 159.785 53.940 ;
        RECT 160.025 53.640 164.185 53.940 ;
        RECT 164.425 53.640 168.585 53.940 ;
        RECT 168.825 53.640 172.985 53.940 ;
        RECT 173.225 53.640 177.385 53.940 ;
        RECT 177.625 53.640 181.785 53.940 ;
        RECT 182.025 53.640 186.185 53.940 ;
        RECT 186.425 53.640 190.585 53.940 ;
        RECT 190.825 53.640 194.985 53.940 ;
        RECT 195.225 53.640 199.385 53.940 ;
        RECT 199.625 53.640 203.785 53.940 ;
        RECT 204.025 53.640 208.185 53.940 ;
        RECT 208.425 53.640 212.585 53.940 ;
        RECT 212.825 53.640 216.985 53.940 ;
        RECT 217.225 53.640 221.385 53.940 ;
        RECT 221.625 53.640 232.385 53.940 ;
        RECT 183.105 49.525 185.065 49.825 ;
        RECT 164.820 48.215 166.340 48.245 ;
        RECT 164.440 48.055 166.740 48.215 ;
        RECT 122.220 39.180 142.480 46.990 ;
        RECT 164.745 48.035 166.340 48.055 ;
        RECT 153.095 46.020 156.665 46.040 ;
        RECT 153.065 45.860 156.705 46.020 ;
        RECT 153.095 45.830 156.665 45.860 ;
        RECT 164.745 42.605 164.905 48.035 ;
        RECT 177.780 47.910 177.940 48.185 ;
        RECT 165.740 43.005 165.950 47.805 ;
        RECT 166.275 47.400 166.435 47.805 ;
        RECT 165.765 42.605 165.925 43.005 ;
        RECT 166.250 42.355 166.460 47.400 ;
        RECT 172.395 44.340 172.605 46.680 ;
        RECT 172.420 44.080 172.580 44.340 ;
        RECT 172.150 43.560 172.850 43.770 ;
        RECT 177.755 43.110 177.965 47.910 ;
        RECT 177.780 42.885 177.940 43.110 ;
        RECT 178.060 42.495 179.990 42.705 ;
        RECT 165.545 42.195 166.460 42.355 ;
        RECT 166.250 42.190 166.460 42.195 ;
        RECT 156.685 41.940 157.305 41.955 ;
        RECT 153.065 41.270 157.305 41.940 ;
        RECT 183.105 41.515 185.065 41.815 ;
        RECT 156.685 41.255 157.305 41.270 ;
        RECT 187.370 40.580 188.070 41.200 ;
        RECT 240.070 40.575 240.270 82.965 ;
        RECT 248.990 78.835 249.490 80.285 ;
        RECT 251.805 78.835 252.305 80.285 ;
        RECT 265.795 78.835 266.295 80.285 ;
        RECT 268.610 78.835 269.110 80.285 ;
        RECT 248.930 78.135 249.550 78.835 ;
        RECT 251.750 78.135 252.370 78.835 ;
        RECT 265.730 78.135 266.350 78.835 ;
        RECT 268.550 78.135 269.170 78.835 ;
        RECT 248.935 77.300 253.495 77.305 ;
        RECT 264.605 77.300 269.165 77.305 ;
        RECT 248.935 77.090 253.545 77.300 ;
        RECT 264.555 77.090 269.165 77.300 ;
        RECT 248.935 77.080 253.495 77.090 ;
        RECT 264.605 77.080 269.165 77.090 ;
        RECT 245.650 76.595 252.365 76.860 ;
        RECT 265.735 76.595 272.450 76.860 ;
        RECT 249.030 75.520 253.555 75.745 ;
        RECT 264.545 75.520 269.070 75.745 ;
        RECT 245.655 73.805 245.865 74.400 ;
        RECT 244.075 73.645 247.410 73.805 ;
        RECT 244.980 73.195 246.500 73.405 ;
        RECT 245.485 71.265 245.820 73.195 ;
        RECT 249.030 71.265 249.355 75.520 ;
        RECT 253.200 74.630 253.410 75.520 ;
        RECT 264.690 74.630 264.900 75.520 ;
        RECT 251.170 73.775 251.870 73.805 ;
        RECT 255.100 73.800 255.800 73.805 ;
        RECT 262.300 73.800 263.000 73.805 ;
        RECT 251.125 73.615 251.870 73.775 ;
        RECT 255.075 73.640 257.075 73.800 ;
        RECT 261.025 73.640 263.025 73.800 ;
        RECT 266.230 73.775 266.930 73.805 ;
        RECT 251.170 73.595 251.870 73.615 ;
        RECT 255.100 73.595 255.800 73.640 ;
        RECT 262.300 73.595 263.000 73.640 ;
        RECT 266.230 73.615 266.975 73.775 ;
        RECT 266.230 73.595 266.930 73.615 ;
        RECT 251.565 73.110 252.265 73.320 ;
        RECT 254.255 73.110 254.955 73.320 ;
        RECT 263.145 73.110 263.845 73.320 ;
        RECT 265.835 73.110 266.535 73.320 ;
        RECT 245.485 71.025 249.355 71.265 ;
        RECT 268.745 71.265 269.070 75.520 ;
        RECT 272.235 73.805 272.445 74.400 ;
        RECT 270.690 73.645 274.025 73.805 ;
        RECT 271.600 73.195 273.120 73.405 ;
        RECT 272.280 71.265 272.615 73.195 ;
        RECT 268.745 71.025 272.615 71.265 ;
        RECT 240.480 69.940 240.680 69.945 ;
        RECT 277.415 69.940 277.615 69.945 ;
        RECT 240.480 69.650 240.690 69.940 ;
        RECT 277.405 69.650 277.615 69.940 ;
        RECT 240.480 41.175 240.680 69.650 ;
        RECT 248.990 65.520 249.490 66.970 ;
        RECT 251.805 65.520 252.305 66.970 ;
        RECT 265.795 65.520 266.295 66.970 ;
        RECT 268.610 65.520 269.110 66.970 ;
        RECT 248.930 64.820 249.550 65.520 ;
        RECT 251.750 64.820 252.370 65.520 ;
        RECT 265.730 64.820 266.350 65.520 ;
        RECT 268.550 64.820 269.170 65.520 ;
        RECT 248.935 63.985 253.495 63.990 ;
        RECT 264.605 63.985 269.165 63.990 ;
        RECT 248.935 63.775 253.545 63.985 ;
        RECT 264.555 63.775 269.165 63.985 ;
        RECT 248.935 63.765 253.495 63.775 ;
        RECT 264.605 63.765 269.165 63.775 ;
        RECT 245.650 63.280 252.365 63.545 ;
        RECT 265.735 63.280 272.450 63.545 ;
        RECT 249.030 62.205 253.555 62.430 ;
        RECT 264.545 62.205 269.070 62.430 ;
        RECT 245.655 60.490 245.865 61.085 ;
        RECT 244.075 60.330 247.410 60.490 ;
        RECT 244.980 59.880 246.500 60.090 ;
        RECT 245.485 57.950 245.820 59.880 ;
        RECT 249.030 57.950 249.355 62.205 ;
        RECT 253.200 61.315 253.410 62.205 ;
        RECT 264.690 61.315 264.900 62.205 ;
        RECT 251.170 60.460 251.870 60.490 ;
        RECT 255.100 60.485 255.800 60.490 ;
        RECT 262.300 60.485 263.000 60.490 ;
        RECT 251.125 60.300 251.870 60.460 ;
        RECT 255.075 60.325 257.075 60.485 ;
        RECT 261.025 60.325 263.025 60.485 ;
        RECT 266.230 60.460 266.930 60.490 ;
        RECT 251.170 60.280 251.870 60.300 ;
        RECT 255.100 60.280 255.800 60.325 ;
        RECT 262.300 60.280 263.000 60.325 ;
        RECT 266.230 60.300 266.975 60.460 ;
        RECT 266.230 60.280 266.930 60.300 ;
        RECT 251.565 59.795 252.265 60.005 ;
        RECT 254.255 59.795 254.955 60.005 ;
        RECT 263.145 59.795 263.845 60.005 ;
        RECT 265.835 59.795 266.535 60.005 ;
        RECT 245.485 57.710 249.355 57.950 ;
        RECT 268.745 57.950 269.070 62.205 ;
        RECT 272.235 60.490 272.445 61.085 ;
        RECT 270.690 60.330 274.025 60.490 ;
        RECT 271.600 59.880 273.120 60.090 ;
        RECT 272.280 57.950 272.615 59.880 ;
        RECT 268.745 57.710 272.615 57.950 ;
        RECT 240.890 56.625 241.090 56.630 ;
        RECT 277.005 56.625 277.205 56.630 ;
        RECT 240.890 56.335 241.100 56.625 ;
        RECT 276.995 56.335 277.205 56.625 ;
        RECT 240.890 41.775 241.090 56.335 ;
        RECT 248.990 52.210 249.490 53.660 ;
        RECT 251.805 52.210 252.305 53.660 ;
        RECT 265.795 52.210 266.295 53.660 ;
        RECT 268.610 52.210 269.110 53.660 ;
        RECT 248.930 51.510 249.550 52.210 ;
        RECT 251.750 51.510 252.370 52.210 ;
        RECT 265.730 51.510 266.350 52.210 ;
        RECT 268.550 51.510 269.170 52.210 ;
        RECT 248.935 50.675 253.495 50.680 ;
        RECT 264.605 50.675 269.165 50.680 ;
        RECT 248.935 50.465 253.545 50.675 ;
        RECT 264.555 50.465 269.165 50.675 ;
        RECT 248.935 50.455 253.495 50.465 ;
        RECT 264.605 50.455 269.165 50.465 ;
        RECT 245.650 49.970 252.365 50.235 ;
        RECT 265.735 49.970 272.450 50.235 ;
        RECT 249.030 48.895 253.555 49.120 ;
        RECT 264.545 48.895 269.070 49.120 ;
        RECT 245.655 47.180 245.865 47.775 ;
        RECT 244.075 47.020 247.410 47.180 ;
        RECT 244.980 46.570 246.500 46.780 ;
        RECT 245.485 44.640 245.820 46.570 ;
        RECT 249.030 44.640 249.355 48.895 ;
        RECT 253.200 48.005 253.410 48.895 ;
        RECT 264.690 48.005 264.900 48.895 ;
        RECT 251.170 47.150 251.870 47.180 ;
        RECT 255.100 47.175 255.800 47.180 ;
        RECT 262.300 47.175 263.000 47.180 ;
        RECT 251.125 46.990 251.870 47.150 ;
        RECT 255.075 47.015 257.075 47.175 ;
        RECT 261.025 47.015 263.025 47.175 ;
        RECT 266.230 47.150 266.930 47.180 ;
        RECT 251.170 46.970 251.870 46.990 ;
        RECT 255.100 46.970 255.800 47.015 ;
        RECT 262.300 46.970 263.000 47.015 ;
        RECT 266.230 46.990 266.975 47.150 ;
        RECT 266.230 46.970 266.930 46.990 ;
        RECT 251.565 46.485 252.265 46.695 ;
        RECT 254.255 46.485 254.955 46.695 ;
        RECT 263.145 46.485 263.845 46.695 ;
        RECT 265.835 46.485 266.535 46.695 ;
        RECT 245.485 44.400 249.355 44.640 ;
        RECT 268.745 44.640 269.070 48.895 ;
        RECT 272.235 47.180 272.445 47.775 ;
        RECT 270.690 47.020 274.025 47.180 ;
        RECT 271.600 46.570 273.120 46.780 ;
        RECT 272.280 44.640 272.615 46.570 ;
        RECT 268.745 44.400 272.615 44.640 ;
        RECT 241.295 43.025 241.505 43.315 ;
        RECT 276.590 43.025 276.800 43.315 ;
        RECT 241.300 42.375 241.500 43.025 ;
        RECT 260.220 42.375 260.420 42.385 ;
        RECT 241.300 42.085 241.510 42.375 ;
        RECT 260.210 42.085 260.420 42.375 ;
        RECT 240.890 41.485 241.100 41.775 ;
        RECT 240.480 40.885 240.690 41.175 ;
        RECT 240.070 40.285 240.280 40.575 ;
        RECT 164.025 39.700 165.545 39.725 ;
        RECT 163.845 39.540 166.795 39.700 ;
        RECT 164.025 39.515 165.545 39.540 ;
        RECT 172.150 39.215 172.850 39.425 ;
        RECT 176.565 39.340 176.775 39.750 ;
        RECT 62.270 38.880 142.480 39.180 ;
        RECT 176.565 39.050 177.045 39.340 ;
        RECT 172.420 38.810 172.580 38.925 ;
        RECT 172.395 37.700 172.605 38.810 ;
        RECT 176.885 38.180 177.045 39.050 ;
        RECT 179.025 39.045 179.235 39.745 ;
        RECT 179.390 37.950 179.680 38.650 ;
        RECT 182.265 37.880 185.015 37.905 ;
        RECT 182.165 37.720 185.115 37.880 ;
        RECT 172.420 37.625 172.580 37.700 ;
        RECT 182.265 37.695 185.015 37.720 ;
        RECT 153.095 37.350 156.665 37.375 ;
        RECT 153.065 37.190 156.705 37.350 ;
        RECT 153.095 37.165 156.665 37.190 ;
        RECT 52.735 31.540 54.255 31.565 ;
        RECT 44.140 31.380 54.480 31.540 ;
        RECT 44.140 26.780 44.300 31.380 ;
        RECT 52.735 31.355 54.255 31.380 ;
        RECT 54.690 29.420 54.900 33.445 ;
        RECT 97.740 32.095 105.715 32.275 ;
        RECT 78.025 31.840 78.235 31.855 ;
        RECT 67.815 31.680 78.235 31.840 ;
        RECT 78.025 31.565 78.235 31.680 ;
        RECT 79.080 31.840 79.290 31.855 ;
        RECT 87.875 31.840 89.395 31.860 ;
        RECT 93.720 31.845 94.830 31.865 ;
        RECT 97.740 31.845 98.170 32.095 ;
        RECT 79.080 31.680 89.500 31.840 ;
        RECT 93.170 31.685 98.170 31.845 ;
        RECT 99.855 31.685 105.255 31.845 ;
        RECT 79.080 31.565 79.290 31.680 ;
        RECT 87.875 31.650 89.395 31.680 ;
        RECT 93.720 31.655 94.830 31.685 ;
        RECT 55.680 31.540 57.200 31.565 ;
        RECT 55.450 31.380 65.790 31.540 ;
        RECT 55.680 31.355 57.200 31.380 ;
        RECT 52.735 26.780 54.255 26.800 ;
        RECT 44.140 26.620 54.480 26.780 ;
        RECT 52.735 26.590 54.255 26.620 ;
        RECT 54.690 24.715 54.900 28.720 ;
        RECT 55.680 26.780 57.200 26.800 ;
        RECT 63.925 26.780 65.445 26.800 ;
        RECT 65.630 26.780 65.790 31.380 ;
        RECT 78.600 30.275 79.220 30.975 ;
        RECT 93.170 28.515 104.855 29.465 ;
        RECT 78.600 27.455 79.220 28.155 ;
        RECT 78.030 27.100 78.335 27.325 ;
        RECT 78.030 26.930 78.830 27.100 ;
        RECT 55.450 26.620 65.790 26.780 ;
        RECT 55.680 26.590 57.200 26.620 ;
        RECT 63.925 26.590 65.445 26.620 ;
        RECT 78.030 26.290 78.335 26.525 ;
        RECT 67.815 26.130 78.335 26.290 ;
        RECT 78.660 26.290 78.830 26.930 ;
        RECT 87.875 26.290 89.395 26.305 ;
        RECT 93.340 26.295 94.860 26.320 ;
        RECT 103.510 26.295 104.210 26.305 ;
        RECT 78.660 26.130 89.500 26.290 ;
        RECT 93.170 26.135 98.170 26.295 ;
        RECT 99.855 26.135 104.855 26.295 ;
        RECT 87.875 26.095 89.395 26.130 ;
        RECT 93.340 26.110 94.860 26.135 ;
        RECT 97.740 25.885 98.170 26.135 ;
        RECT 103.510 26.095 104.210 26.135 ;
        RECT 105.035 25.885 105.255 31.685 ;
        RECT 105.495 26.135 105.715 32.095 ;
        RECT 116.115 31.450 117.635 31.470 ;
        RECT 130.765 31.450 132.285 31.470 ;
        RECT 107.850 31.290 118.190 31.450 ;
        RECT 116.115 31.260 117.635 31.290 ;
        RECT 118.030 26.690 118.190 31.290 ;
        RECT 107.850 26.530 118.190 26.690 ;
        RECT 118.750 31.290 129.090 31.450 ;
        RECT 130.330 31.290 140.670 31.450 ;
        RECT 118.750 26.690 118.910 31.290 ;
        RECT 130.765 31.260 132.285 31.290 ;
        RECT 119.350 26.690 120.870 26.715 ;
        RECT 130.410 26.690 131.930 26.715 ;
        RECT 140.510 26.690 140.670 31.290 ;
        RECT 260.220 30.340 260.420 42.085 ;
        RECT 260.630 41.775 260.830 41.785 ;
        RECT 260.620 41.485 260.830 41.775 ;
        RECT 260.630 30.940 260.830 41.485 ;
        RECT 261.040 41.175 261.240 41.185 ;
        RECT 261.030 40.885 261.240 41.175 ;
        RECT 261.040 31.540 261.240 40.885 ;
        RECT 261.450 40.575 261.650 40.585 ;
        RECT 261.440 40.285 261.650 40.575 ;
        RECT 261.450 32.140 261.650 40.285 ;
        RECT 261.860 39.695 262.070 39.985 ;
        RECT 276.595 39.975 276.795 43.025 ;
        RECT 261.860 32.740 262.060 39.695 ;
        RECT 276.585 39.685 276.795 39.975 ;
        RECT 262.270 39.095 262.480 39.385 ;
        RECT 277.005 39.375 277.205 56.335 ;
        RECT 262.270 33.340 262.470 39.095 ;
        RECT 276.995 39.085 277.205 39.375 ;
        RECT 262.680 38.495 262.890 38.785 ;
        RECT 277.415 38.775 277.615 69.650 ;
        RECT 262.680 33.940 262.880 38.495 ;
        RECT 277.405 38.485 277.615 38.775 ;
        RECT 263.090 37.895 263.300 38.185 ;
        RECT 277.825 38.175 278.025 82.965 ;
        RECT 263.090 34.540 263.290 37.895 ;
        RECT 277.815 37.885 278.025 38.175 ;
        RECT 263.090 34.250 263.300 34.540 ;
        RECT 278.870 34.260 279.080 34.550 ;
        RECT 262.680 33.650 262.890 33.940 ;
        RECT 278.460 33.660 278.670 33.950 ;
        RECT 262.270 33.050 262.480 33.340 ;
        RECT 278.050 33.060 278.260 33.350 ;
        RECT 261.860 32.450 262.070 32.740 ;
        RECT 277.640 32.460 277.850 32.750 ;
        RECT 261.450 31.850 261.660 32.140 ;
        RECT 277.230 31.860 277.440 32.150 ;
        RECT 261.040 31.250 261.250 31.540 ;
        RECT 276.820 31.260 277.030 31.550 ;
        RECT 260.630 30.650 260.840 30.940 ;
        RECT 276.410 30.660 276.620 30.950 ;
        RECT 260.220 30.050 260.430 30.340 ;
        RECT 276.000 30.060 276.210 30.350 ;
        RECT 250.805 27.960 251.015 28.020 ;
        RECT 257.080 27.960 257.290 28.020 ;
        RECT 263.355 27.960 263.565 28.025 ;
        RECT 269.630 27.960 269.840 28.025 ;
        RECT 247.545 27.800 269.840 27.960 ;
        RECT 247.545 27.670 247.755 27.800 ;
        RECT 250.805 27.730 251.015 27.800 ;
        RECT 257.080 27.730 257.290 27.800 ;
        RECT 263.355 27.735 263.565 27.800 ;
        RECT 269.630 27.735 269.840 27.800 ;
        RECT 251.215 27.080 251.425 27.145 ;
        RECT 257.490 27.080 257.700 27.145 ;
        RECT 248.365 26.920 257.700 27.080 ;
        RECT 248.365 26.790 248.575 26.920 ;
        RECT 251.215 26.855 251.425 26.920 ;
        RECT 257.490 26.855 257.700 26.920 ;
        RECT 118.750 26.530 129.090 26.690 ;
        RECT 130.330 26.530 140.670 26.690 ;
        RECT 119.350 26.505 120.870 26.530 ;
        RECT 130.410 26.505 131.930 26.530 ;
        RECT 105.500 26.070 105.710 26.135 ;
        RECT 97.740 25.705 105.255 25.885 ;
        RECT 244.720 25.335 244.950 26.780 ;
        RECT 251.625 26.200 251.835 26.265 ;
        RECT 264.245 26.200 264.535 26.250 ;
        RECT 249.185 26.040 270.655 26.200 ;
        RECT 276.010 26.130 276.210 30.060 ;
        RECT 249.185 25.910 249.395 26.040 ;
        RECT 251.625 25.975 251.835 26.040 ;
        RECT 275.040 25.860 275.330 25.910 ;
        RECT 256.145 25.850 275.330 25.860 ;
        RECT 256.095 25.700 275.330 25.850 ;
        RECT 276.005 25.840 276.215 26.130 ;
        RECT 256.095 25.640 256.385 25.700 ;
        RECT 276.420 25.630 276.620 30.660 ;
        RECT 275.510 25.520 275.800 25.545 ;
        RECT 247.545 25.335 247.755 25.400 ;
        RECT 244.720 25.175 247.755 25.335 ;
        RECT 262.375 25.360 275.800 25.520 ;
        RECT 262.375 25.310 262.665 25.360 ;
        RECT 275.510 25.335 275.800 25.360 ;
        RECT 276.415 25.340 276.625 25.630 ;
        RECT 244.720 24.215 244.950 25.175 ;
        RECT 247.545 25.110 247.755 25.175 ;
        RECT 268.650 25.020 275.345 25.180 ;
        RECT 276.830 25.130 277.030 31.260 ;
        RECT 268.650 24.970 268.940 25.020 ;
        RECT 275.055 24.970 275.345 25.020 ;
        RECT 276.825 24.840 277.035 25.130 ;
        RECT 277.240 24.630 277.440 31.860 ;
        RECT 277.235 24.340 277.445 24.630 ;
        RECT 253.000 23.010 253.260 23.755 ;
        RECT 254.050 23.010 254.310 23.750 ;
        RECT 252.420 22.850 255.075 23.010 ;
        RECT 252.420 21.840 252.590 22.850 ;
        RECT 252.790 22.085 253.145 22.615 ;
        RECT 253.350 22.085 253.625 22.615 ;
        RECT 253.865 22.085 254.110 22.615 ;
        RECT 254.915 22.500 255.075 22.850 ;
        RECT 255.270 22.700 255.750 23.810 ;
        RECT 259.275 23.010 259.535 23.755 ;
        RECT 260.325 23.010 260.585 23.750 ;
        RECT 254.915 22.170 255.270 22.500 ;
        RECT 255.590 21.840 255.750 22.700 ;
        RECT 54.695 20.540 56.215 20.565 ;
        RECT 89.870 20.540 91.390 20.560 ;
        RECT 54.695 20.380 91.390 20.540 ;
        RECT 54.695 20.355 56.215 20.380 ;
        RECT 89.870 20.350 91.390 20.380 ;
        RECT 65.970 20.010 67.490 20.035 ;
        RECT 95.615 20.010 96.315 20.015 ;
        RECT 103.960 20.010 104.580 20.455 ;
        RECT 244.720 20.265 244.950 21.695 ;
        RECT 252.420 21.240 252.750 21.840 ;
        RECT 255.270 21.705 255.750 21.840 ;
        RECT 258.695 22.850 261.350 23.010 ;
        RECT 258.695 21.840 258.865 22.850 ;
        RECT 259.065 22.085 259.420 22.615 ;
        RECT 260.140 22.085 260.385 22.615 ;
        RECT 261.190 22.500 261.350 22.850 ;
        RECT 261.545 22.700 262.025 23.810 ;
        RECT 265.550 23.010 265.810 23.755 ;
        RECT 266.600 23.010 266.860 23.750 ;
        RECT 261.190 22.170 261.545 22.500 ;
        RECT 261.865 21.840 262.025 22.700 ;
        RECT 255.270 21.495 256.300 21.705 ;
        RECT 255.270 21.240 255.750 21.495 ;
        RECT 258.695 21.240 259.025 21.840 ;
        RECT 261.545 21.705 262.025 21.840 ;
        RECT 264.970 22.850 267.625 23.010 ;
        RECT 264.970 21.840 265.140 22.850 ;
        RECT 265.900 22.085 266.175 22.615 ;
        RECT 266.415 22.085 266.660 22.615 ;
        RECT 267.465 22.500 267.625 22.850 ;
        RECT 267.820 22.700 268.300 23.810 ;
        RECT 271.825 23.010 272.085 23.755 ;
        RECT 272.875 23.010 273.135 23.750 ;
        RECT 267.465 22.170 267.820 22.500 ;
        RECT 268.140 21.840 268.300 22.700 ;
        RECT 261.545 21.495 262.575 21.705 ;
        RECT 261.545 21.240 262.025 21.495 ;
        RECT 264.970 21.240 265.300 21.840 ;
        RECT 267.820 21.705 268.300 21.840 ;
        RECT 271.245 22.850 273.900 23.010 ;
        RECT 271.245 21.840 271.415 22.850 ;
        RECT 272.690 22.085 272.935 22.615 ;
        RECT 273.740 22.500 273.900 22.850 ;
        RECT 274.095 22.700 274.575 23.810 ;
        RECT 273.740 22.170 274.095 22.500 ;
        RECT 274.415 21.840 274.575 22.700 ;
        RECT 267.820 21.495 268.850 21.705 ;
        RECT 267.820 21.240 268.300 21.495 ;
        RECT 271.245 21.240 271.575 21.840 ;
        RECT 274.095 21.705 274.575 21.840 ;
        RECT 274.095 21.495 275.125 21.705 ;
        RECT 274.095 21.240 274.575 21.495 ;
        RECT 248.365 20.265 248.575 20.330 ;
        RECT 244.720 20.105 248.575 20.265 ;
        RECT 47.695 19.850 130.225 20.010 ;
        RECT 47.705 19.800 48.405 19.850 ;
        RECT 65.970 19.825 67.490 19.850 ;
        RECT 95.615 19.805 96.315 19.850 ;
        RECT 103.960 19.755 104.580 19.850 ;
        RECT 128.295 19.800 130.225 19.850 ;
        RECT 244.720 19.130 244.950 20.105 ;
        RECT 248.365 20.040 248.575 20.105 ;
        RECT 252.420 19.060 252.750 19.660 ;
        RECT 255.270 19.405 255.750 19.660 ;
        RECT 255.270 19.195 256.300 19.405 ;
        RECT 255.270 19.060 255.750 19.195 ;
        RECT 252.420 18.050 252.590 19.060 ;
        RECT 254.915 18.400 255.270 18.730 ;
        RECT 254.915 18.050 255.075 18.400 ;
        RECT 255.590 18.200 255.750 19.060 ;
        RECT 252.420 17.890 255.075 18.050 ;
        RECT 44.215 17.350 45.665 17.810 ;
        RECT 54.965 17.350 56.415 17.810 ;
        RECT 44.215 16.815 44.675 17.350 ;
        RECT 55.955 16.815 56.415 17.350 ;
        RECT 73.185 17.285 73.885 17.495 ;
        RECT 84.435 17.285 85.135 17.495 ;
        RECT 95.665 17.285 96.365 17.495 ;
        RECT 106.895 17.285 107.595 17.495 ;
        RECT 118.145 17.285 118.845 17.495 ;
        RECT 129.415 17.285 130.115 17.495 ;
        RECT 253.000 17.145 253.260 17.890 ;
        RECT 254.050 17.150 254.310 17.890 ;
        RECT 255.270 17.090 255.750 18.200 ;
        RECT 258.695 19.060 259.025 19.660 ;
        RECT 261.545 19.405 262.025 19.660 ;
        RECT 261.545 19.195 262.575 19.405 ;
        RECT 261.545 19.060 262.025 19.195 ;
        RECT 258.695 18.050 258.865 19.060 ;
        RECT 259.625 18.285 259.900 18.815 ;
        RECT 261.190 18.400 261.545 18.730 ;
        RECT 261.190 18.050 261.350 18.400 ;
        RECT 261.865 18.200 262.025 19.060 ;
        RECT 258.695 17.890 261.350 18.050 ;
        RECT 259.275 17.145 259.535 17.890 ;
        RECT 260.325 17.150 260.585 17.890 ;
        RECT 261.545 17.090 262.025 18.200 ;
        RECT 264.970 19.060 265.300 19.660 ;
        RECT 267.820 19.405 268.300 19.660 ;
        RECT 267.820 19.195 268.850 19.405 ;
        RECT 267.820 19.060 268.300 19.195 ;
        RECT 264.970 18.050 265.140 19.060 ;
        RECT 265.340 18.285 265.695 18.815 ;
        RECT 267.465 18.400 267.820 18.730 ;
        RECT 267.465 18.050 267.625 18.400 ;
        RECT 268.140 18.200 268.300 19.060 ;
        RECT 264.970 17.890 267.625 18.050 ;
        RECT 265.550 17.145 265.810 17.890 ;
        RECT 266.600 17.150 266.860 17.890 ;
        RECT 267.820 17.090 268.300 18.200 ;
        RECT 271.245 19.060 271.575 19.660 ;
        RECT 274.095 19.405 274.575 19.660 ;
        RECT 274.095 19.195 275.125 19.405 ;
        RECT 274.095 19.060 274.575 19.195 ;
        RECT 271.245 18.050 271.415 19.060 ;
        RECT 271.615 18.285 271.970 18.815 ;
        RECT 272.175 18.285 272.450 18.815 ;
        RECT 273.740 18.400 274.095 18.730 ;
        RECT 273.740 18.050 273.900 18.400 ;
        RECT 274.415 18.200 274.575 19.060 ;
        RECT 271.245 17.890 273.900 18.050 ;
        RECT 271.825 17.145 272.085 17.890 ;
        RECT 272.875 17.150 273.135 17.890 ;
        RECT 274.095 17.090 274.575 18.200 ;
        RECT 44.055 12.940 44.755 13.560 ;
        RECT 45.405 13.390 45.665 15.170 ;
        RECT 54.965 14.710 55.225 16.490 ;
        RECT 73.185 16.455 73.885 16.665 ;
        RECT 84.435 16.455 85.135 16.665 ;
        RECT 95.665 16.455 96.365 16.665 ;
        RECT 106.895 16.455 107.595 16.665 ;
        RECT 118.145 16.455 118.845 16.665 ;
        RECT 129.415 16.455 130.115 16.665 ;
        RECT 73.185 15.615 73.885 15.825 ;
        RECT 84.435 15.615 85.135 15.825 ;
        RECT 95.665 15.615 96.365 15.825 ;
        RECT 106.895 15.615 107.595 15.825 ;
        RECT 118.145 15.615 118.845 15.825 ;
        RECT 129.415 15.615 130.115 15.825 ;
        RECT 244.720 15.165 244.950 16.565 ;
        RECT 277.650 16.430 277.850 32.460 ;
        RECT 277.645 16.140 277.855 16.430 ;
        RECT 278.060 15.930 278.260 33.060 ;
        RECT 268.650 15.660 268.940 15.710 ;
        RECT 275.055 15.660 275.345 15.710 ;
        RECT 268.650 15.500 275.345 15.660 ;
        RECT 278.055 15.640 278.265 15.930 ;
        RECT 278.470 15.430 278.670 33.660 ;
        RECT 262.375 15.320 262.665 15.370 ;
        RECT 275.510 15.320 275.800 15.345 ;
        RECT 249.185 15.165 249.395 15.295 ;
        RECT 244.720 15.005 249.395 15.165 ;
        RECT 262.375 15.160 275.800 15.320 ;
        RECT 275.510 15.135 275.800 15.160 ;
        RECT 278.465 15.140 278.675 15.430 ;
        RECT 73.185 14.775 73.885 14.985 ;
        RECT 84.435 14.775 85.135 14.985 ;
        RECT 95.665 14.775 96.365 14.985 ;
        RECT 106.895 14.775 107.595 14.985 ;
        RECT 118.145 14.775 118.845 14.985 ;
        RECT 129.415 14.775 130.115 14.985 ;
        RECT 73.185 13.965 73.885 14.175 ;
        RECT 84.435 13.965 85.135 14.175 ;
        RECT 95.665 13.965 96.365 14.175 ;
        RECT 106.895 13.965 107.595 14.175 ;
        RECT 118.145 13.965 118.845 14.175 ;
        RECT 129.415 13.965 130.115 14.175 ;
        RECT 244.720 14.000 244.950 15.005 ;
        RECT 256.095 14.980 256.385 15.030 ;
        RECT 256.095 14.820 275.330 14.980 ;
        RECT 278.880 14.930 279.080 34.260 ;
        RECT 275.040 14.770 275.330 14.820 ;
        RECT 249.185 14.640 249.395 14.770 ;
        RECT 278.875 14.640 279.085 14.930 ;
        RECT 249.185 14.480 270.745 14.640 ;
        RECT 257.905 14.430 258.195 14.480 ;
        RECT 270.455 14.430 270.745 14.480 ;
        RECT 248.365 13.760 248.575 13.890 ;
        RECT 263.765 13.760 263.975 13.825 ;
        RECT 270.040 13.760 270.250 13.825 ;
        RECT 248.365 13.600 270.250 13.760 ;
        RECT 263.765 13.535 263.975 13.600 ;
        RECT 270.040 13.535 270.250 13.600 ;
        RECT 55.860 11.990 56.415 13.515 ;
        RECT 73.185 13.125 73.885 13.335 ;
        RECT 84.435 13.125 85.135 13.335 ;
        RECT 95.665 13.125 96.365 13.335 ;
        RECT 106.895 13.125 107.595 13.335 ;
        RECT 118.145 13.125 118.845 13.335 ;
        RECT 129.415 13.125 130.115 13.335 ;
        RECT 73.185 12.285 73.885 12.495 ;
        RECT 84.435 12.285 85.135 12.495 ;
        RECT 95.665 12.285 96.365 12.495 ;
        RECT 106.895 12.285 107.595 12.495 ;
        RECT 118.145 12.285 118.845 12.495 ;
        RECT 129.415 12.285 130.115 12.495 ;
        RECT 55.860 11.780 56.560 11.990 ;
      LAYER Metal2 ;
        RECT 151.235 92.510 177.385 92.810 ;
        RECT 248.935 90.605 249.545 92.150 ;
        RECT 136.800 90.460 137.000 90.495 ;
        RECT 128.880 90.100 135.780 90.300 ;
        RECT 119.480 88.825 120.180 89.025 ;
        RECT 119.480 88.625 135.780 88.825 ;
        RECT 119.480 88.415 120.180 88.625 ;
        RECT 136.190 88.370 136.390 89.820 ;
        RECT 136.790 88.525 137.005 90.460 ;
        RECT 248.935 90.405 249.635 90.605 ;
        RECT 245.650 90.130 245.870 90.175 ;
        RECT 251.755 90.130 252.365 92.150 ;
        RECT 253.045 90.610 253.555 90.620 ;
        RECT 252.845 90.410 253.555 90.610 ;
        RECT 245.650 89.930 246.370 90.130 ;
        RECT 251.665 89.930 252.365 90.130 ;
        RECT 128.315 88.170 136.390 88.370 ;
        RECT 13.185 85.855 13.475 87.750 ;
        RECT 21.345 84.665 21.635 87.710 ;
        RECT 40.630 85.190 40.830 86.750 ;
        RECT 52.720 85.865 52.920 87.665 ;
        RECT 128.315 87.390 128.515 88.170 ;
        RECT 118.885 86.875 134.035 87.075 ;
        RECT 118.885 86.870 119.175 86.875 ;
        RECT 136.190 86.595 136.390 88.170 ;
        RECT 245.650 86.960 245.870 89.930 ;
        RECT 253.045 87.115 253.555 90.410 ;
        RECT 264.545 90.610 265.055 90.620 ;
        RECT 264.545 90.410 265.255 90.610 ;
        RECT 264.545 87.115 265.055 90.410 ;
        RECT 265.735 90.130 266.345 92.150 ;
        RECT 268.555 90.605 269.165 92.150 ;
        RECT 268.465 90.405 269.165 90.605 ;
        RECT 272.230 90.130 272.450 90.175 ;
        RECT 265.735 89.930 266.435 90.130 ;
        RECT 271.730 89.930 272.450 90.130 ;
        RECT 251.170 86.915 255.800 87.115 ;
        RECT 262.300 86.915 266.930 87.115 ;
        RECT 272.230 86.960 272.450 89.930 ;
        RECT 120.190 86.395 136.390 86.595 ;
        RECT 244.980 86.515 246.500 86.715 ;
        RECT 251.565 86.430 254.955 86.630 ;
        RECT 263.145 86.430 266.535 86.630 ;
        RECT 271.600 86.515 273.120 86.715 ;
        RECT 120.190 86.390 120.480 86.395 ;
        RECT 52.720 85.665 57.685 85.865 ;
        RECT 40.015 84.970 40.830 85.190 ;
        RECT 40.015 83.325 40.215 84.970 ;
        RECT 57.485 83.900 57.685 85.665 ;
        RECT 253.045 83.260 253.555 86.430 ;
        RECT 240.070 82.960 253.555 83.260 ;
        RECT 264.545 83.260 265.055 86.430 ;
        RECT 264.545 82.960 278.030 83.260 ;
        RECT 134.190 82.050 134.390 82.055 ;
        RECT 130.555 81.850 134.390 82.050 ;
        RECT 130.560 81.835 131.260 81.850 ;
        RECT 19.750 78.545 22.790 78.745 ;
        RECT 22.590 71.125 22.790 78.545 ;
        RECT 40.010 77.960 40.210 80.615 ;
        RECT 38.915 77.720 40.210 77.960 ;
        RECT 40.625 78.415 40.825 80.615 ;
        RECT 57.485 78.425 57.685 81.675 ;
        RECT 130.310 81.600 130.510 81.605 ;
        RECT 133.060 81.600 133.260 81.630 ;
        RECT 130.310 81.340 133.260 81.600 ;
        RECT 91.040 81.110 92.560 81.310 ;
        RECT 91.505 79.555 92.120 81.110 ;
        RECT 40.625 77.805 41.390 78.415 ;
        RECT 57.395 78.225 57.685 78.425 ;
        RECT 57.485 78.220 57.685 78.225 ;
        RECT 85.540 79.270 86.240 79.470 ;
        RECT 51.755 77.810 52.045 78.010 ;
        RECT 40.625 77.720 40.825 77.805 ;
        RECT 18.845 70.925 22.790 71.125 ;
        RECT 27.960 73.095 28.160 73.120 ;
        RECT 31.325 73.095 31.525 77.465 ;
        RECT 38.915 76.605 39.135 77.720 ;
        RECT 38.675 76.405 39.375 76.605 ;
        RECT 38.915 76.395 39.135 76.405 ;
        RECT 27.960 72.890 31.525 73.095 ;
        RECT 10.530 70.000 13.430 70.290 ;
        RECT 20.385 64.915 20.675 70.690 ;
        RECT 17.055 64.715 20.675 64.915 ;
        RECT 21.470 63.905 21.760 70.925 ;
        RECT 27.960 70.780 28.160 72.890 ;
        RECT 14.120 63.705 21.760 63.905 ;
        RECT 23.440 63.755 23.640 70.290 ;
        RECT 51.800 65.710 52.000 77.810 ;
        RECT 85.540 76.610 85.740 79.270 ;
        RECT 91.505 75.295 92.115 79.555 ;
        RECT 130.310 74.180 130.510 81.340 ;
        RECT 134.190 77.345 134.390 81.850 ;
        RECT 129.560 73.950 130.510 74.180 ;
        RECT 129.560 72.460 129.760 73.950 ;
        RECT 132.030 73.715 132.640 76.885 ;
        RECT 134.185 75.825 134.390 77.345 ;
        RECT 248.935 77.290 249.545 78.835 ;
        RECT 248.935 77.090 249.635 77.290 ;
        RECT 134.190 74.645 134.390 75.825 ;
        RECT 245.650 76.815 245.870 76.860 ;
        RECT 251.755 76.815 252.365 78.835 ;
        RECT 253.045 77.295 253.555 77.305 ;
        RECT 252.845 77.095 253.555 77.295 ;
        RECT 245.650 76.615 246.370 76.815 ;
        RECT 251.665 76.615 252.365 76.815 ;
        RECT 133.960 74.035 134.660 74.645 ;
        RECT 134.190 73.950 134.390 74.035 ;
        RECT 131.990 73.105 132.690 73.715 ;
        RECT 245.650 73.645 245.870 76.615 ;
        RECT 253.045 73.800 253.555 77.095 ;
        RECT 264.545 77.295 265.055 77.305 ;
        RECT 264.545 77.095 265.255 77.295 ;
        RECT 264.545 73.800 265.055 77.095 ;
        RECT 265.735 76.815 266.345 78.835 ;
        RECT 268.555 77.290 269.165 78.835 ;
        RECT 268.465 77.090 269.165 77.290 ;
        RECT 272.230 76.815 272.450 76.860 ;
        RECT 265.735 76.615 266.435 76.815 ;
        RECT 271.730 76.615 272.450 76.815 ;
        RECT 251.170 73.600 255.800 73.800 ;
        RECT 262.300 73.600 266.930 73.800 ;
        RECT 272.230 73.645 272.450 76.615 ;
        RECT 244.980 73.200 246.500 73.400 ;
        RECT 251.565 73.115 254.955 73.315 ;
        RECT 263.145 73.115 266.535 73.315 ;
        RECT 271.600 73.200 273.120 73.400 ;
        RECT 129.560 72.260 134.590 72.460 ;
        RECT 129.560 70.515 129.760 72.260 ;
        RECT 132.050 68.910 132.660 71.250 ;
        RECT 253.045 69.945 253.555 73.115 ;
        RECT 86.665 68.205 93.980 68.405 ;
        RECT 94.610 68.205 120.465 68.405 ;
        RECT 90.190 67.715 93.380 67.915 ;
        RECT 93.775 67.695 93.980 68.205 ;
        RECT 120.235 67.705 120.435 68.205 ;
        RECT 120.880 67.740 131.590 67.940 ;
        RECT 120.880 67.735 121.170 67.740 ;
        RECT 86.655 67.495 88.995 67.695 ;
        RECT 93.775 67.495 119.160 67.695 ;
        RECT 118.930 66.990 119.130 67.495 ;
        RECT 134.940 67.410 135.140 69.660 ;
        RECT 240.480 69.645 253.555 69.945 ;
        RECT 264.545 69.945 265.055 73.115 ;
        RECT 264.545 69.645 277.620 69.945 ;
        RECT 119.480 67.210 135.140 67.410 ;
        RECT 121.745 66.645 135.260 66.650 ;
        RECT 121.540 66.450 135.260 66.645 ;
        RECT 121.540 66.445 122.240 66.450 ;
        RECT 118.920 65.725 119.120 66.225 ;
        RECT 120.860 65.725 121.150 65.730 ;
        RECT 130.060 65.725 130.260 66.130 ;
        RECT 50.335 65.510 52.000 65.710 ;
        RECT 118.885 65.525 130.260 65.725 ;
        RECT 15.480 56.015 15.680 56.275 ;
        RECT 16.790 56.015 16.990 63.705 ;
        RECT 15.480 55.815 16.990 56.015 ;
        RECT 18.815 56.275 20.035 56.565 ;
        RECT 15.480 55.575 15.680 55.815 ;
        RECT 18.815 55.325 19.115 56.275 ;
        RECT 15.510 55.035 19.115 55.325 ;
        RECT 7.425 49.295 15.130 49.495 ;
        RECT 18.815 46.950 19.115 55.035 ;
        RECT 35.950 54.610 36.150 54.655 ;
        RECT 38.175 54.610 39.460 54.805 ;
        RECT 44.690 54.610 44.890 54.655 ;
        RECT 35.950 54.605 39.460 54.610 ;
        RECT 35.950 54.410 38.465 54.605 ;
        RECT 42.375 54.410 44.890 54.610 ;
        RECT 35.950 54.365 36.150 54.410 ;
        RECT 44.690 54.365 44.890 54.410 ;
        RECT 13.605 46.750 22.560 46.950 ;
        RECT 15.020 45.245 21.015 45.535 ;
        RECT 19.530 41.680 19.735 45.245 ;
        RECT 51.260 43.910 51.490 65.510 ;
        RECT 85.535 55.795 85.735 59.705 ;
        RECT 80.910 55.570 85.735 55.795 ;
        RECT 97.890 55.815 98.090 59.705 ;
        RECT 119.515 55.900 119.715 56.015 ;
        RECT 97.890 55.570 102.710 55.815 ;
        RECT 113.530 55.645 119.755 55.900 ;
        RECT 113.530 55.570 114.195 55.645 ;
        RECT 63.350 52.560 63.550 54.745 ;
        RECT 80.910 52.775 81.110 55.570 ;
        RECT 102.510 55.315 114.195 55.570 ;
        RECT 119.515 55.315 119.715 55.645 ;
        RECT 120.230 55.315 120.895 56.015 ;
        RECT 102.510 52.540 102.710 55.315 ;
        RECT 89.775 52.335 102.710 52.540 ;
        RECT 89.775 52.030 89.975 52.335 ;
        RECT 80.915 51.830 89.975 52.030 ;
        RECT 90.300 51.830 93.375 52.030 ;
        RECT 80.915 50.890 81.115 51.830 ;
        RECT 73.850 47.905 75.135 48.195 ;
        RECT 85.495 47.905 98.420 48.195 ;
        RECT 108.780 47.905 110.065 48.195 ;
        RECT 50.335 43.710 51.490 43.910 ;
        RECT 62.610 46.585 63.495 46.875 ;
        RECT 73.850 46.585 74.050 47.905 ;
        RECT 109.865 46.585 110.065 47.905 ;
        RECT 19.530 41.480 22.585 41.680 ;
        RECT 62.610 41.590 62.810 46.585 ;
        RECT 120.495 46.435 120.895 55.315 ;
        RECT 120.210 45.940 120.895 46.435 ;
        RECT 120.210 45.735 120.820 45.940 ;
        RECT 121.680 41.600 122.080 56.015 ;
        RECT 130.060 53.685 130.260 65.525 ;
        RECT 135.060 53.685 135.260 66.450 ;
        RECT 248.935 63.975 249.545 65.520 ;
        RECT 248.935 63.775 249.635 63.975 ;
        RECT 245.650 63.500 245.870 63.545 ;
        RECT 251.755 63.500 252.365 65.520 ;
        RECT 253.045 63.980 253.555 63.990 ;
        RECT 252.845 63.780 253.555 63.980 ;
        RECT 245.650 63.300 246.370 63.500 ;
        RECT 251.665 63.300 252.365 63.500 ;
        RECT 245.650 60.330 245.870 63.300 ;
        RECT 253.045 60.485 253.555 63.780 ;
        RECT 264.545 63.980 265.055 63.990 ;
        RECT 264.545 63.780 265.255 63.980 ;
        RECT 264.545 60.485 265.055 63.780 ;
        RECT 265.735 63.500 266.345 65.520 ;
        RECT 268.555 63.975 269.165 65.520 ;
        RECT 268.465 63.775 269.165 63.975 ;
        RECT 272.230 63.500 272.450 63.545 ;
        RECT 265.735 63.300 266.435 63.500 ;
        RECT 271.730 63.300 272.450 63.500 ;
        RECT 251.170 60.285 255.800 60.485 ;
        RECT 262.300 60.285 266.930 60.485 ;
        RECT 272.230 60.330 272.450 63.300 ;
        RECT 244.980 59.885 246.500 60.085 ;
        RECT 251.565 59.800 254.955 60.000 ;
        RECT 263.145 59.800 266.535 60.000 ;
        RECT 271.600 59.885 273.120 60.085 ;
        RECT 253.045 56.630 253.555 59.800 ;
        RECT 240.890 56.330 253.555 56.630 ;
        RECT 264.545 56.630 265.055 59.800 ;
        RECT 264.545 56.330 277.210 56.630 ;
        RECT 248.935 50.665 249.545 52.210 ;
        RECT 248.935 50.465 249.635 50.665 ;
        RECT 245.650 50.190 245.870 50.235 ;
        RECT 251.755 50.190 252.365 52.210 ;
        RECT 253.045 50.670 253.555 50.680 ;
        RECT 252.845 50.470 253.555 50.670 ;
        RECT 245.650 49.990 246.370 50.190 ;
        RECT 251.665 49.990 252.365 50.190 ;
        RECT 165.745 49.565 185.055 49.780 ;
        RECT 164.605 49.020 172.605 49.050 ;
        RECT 164.605 48.820 172.630 49.020 ;
        RECT 164.605 48.800 172.605 48.820 ;
        RECT 153.100 48.240 166.340 48.245 ;
        RECT 153.095 48.040 166.340 48.240 ;
        RECT 153.100 48.035 166.340 48.040 ;
        RECT 153.095 45.835 156.665 46.035 ;
        RECT 165.745 43.005 165.945 47.805 ;
        RECT 166.255 42.190 166.455 47.400 ;
        RECT 172.400 44.340 172.600 46.680 ;
        RECT 172.150 43.515 172.850 43.765 ;
        RECT 177.760 43.110 177.960 47.910 ;
        RECT 245.650 47.020 245.870 49.990 ;
        RECT 253.045 47.175 253.555 50.470 ;
        RECT 264.545 50.670 265.055 50.680 ;
        RECT 264.545 50.470 265.255 50.670 ;
        RECT 264.545 47.175 265.055 50.470 ;
        RECT 265.735 50.190 266.345 52.210 ;
        RECT 268.555 50.665 269.165 52.210 ;
        RECT 268.465 50.465 269.165 50.665 ;
        RECT 272.230 50.190 272.450 50.235 ;
        RECT 265.735 49.990 266.435 50.190 ;
        RECT 271.730 49.990 272.450 50.190 ;
        RECT 251.170 46.975 255.800 47.175 ;
        RECT 262.300 46.975 266.930 47.175 ;
        RECT 272.230 47.020 272.450 49.990 ;
        RECT 244.980 46.575 246.500 46.775 ;
        RECT 251.565 46.490 254.955 46.690 ;
        RECT 263.145 46.490 266.535 46.690 ;
        RECT 271.600 46.575 273.120 46.775 ;
        RECT 253.045 43.320 253.555 46.490 ;
        RECT 241.300 43.020 253.555 43.320 ;
        RECT 264.545 43.320 265.055 46.490 ;
        RECT 264.545 43.020 276.800 43.320 ;
        RECT 176.565 42.700 179.990 42.705 ;
        RECT 176.525 42.500 179.990 42.700 ;
        RECT 176.565 42.495 179.990 42.500 ;
        RECT 241.300 42.085 260.420 42.385 ;
        RECT 19.530 41.295 19.735 41.480 ;
        RECT 62.610 41.300 63.495 41.590 ;
        RECT 13.125 41.095 19.735 41.295 ;
        RECT 73.850 40.275 74.050 41.595 ;
        RECT 109.865 40.275 110.065 41.595 ;
        RECT 73.850 39.985 75.135 40.275 ;
        RECT 85.495 39.985 98.420 40.275 ;
        RECT 108.780 39.985 110.065 40.275 ;
        RECT 120.850 41.310 122.080 41.600 ;
        RECT 62.820 39.700 63.020 39.705 ;
        RECT 120.850 39.700 121.120 41.310 ;
        RECT 156.685 41.250 177.960 41.955 ;
        RECT 183.130 41.565 185.060 41.765 ;
        RECT 240.890 41.485 260.830 41.785 ;
        RECT 187.370 41.000 188.070 41.195 ;
        RECT 172.150 40.800 188.435 41.000 ;
        RECT 240.480 40.885 261.240 41.185 ;
        RECT 187.370 40.585 188.070 40.800 ;
        RECT 240.070 40.285 261.650 40.585 ;
        RECT 62.810 39.415 121.120 39.700 ;
        RECT 164.025 39.520 165.545 39.720 ;
        RECT 172.150 39.220 172.850 39.905 ;
        RECT 176.520 39.050 176.820 39.750 ;
        RECT 178.980 39.045 179.280 39.745 ;
        RECT 261.860 39.685 276.795 39.985 ;
        RECT 262.270 39.085 277.205 39.385 ;
        RECT 172.400 37.700 172.600 38.810 ;
        RECT 179.470 37.950 179.680 38.650 ;
        RECT 262.680 38.485 277.615 38.785 ;
        RECT 182.265 37.700 185.015 37.900 ;
        RECT 263.090 37.885 278.025 38.185 ;
        RECT 153.095 37.370 166.460 37.375 ;
        RECT 153.095 37.170 166.500 37.370 ;
        RECT 172.405 35.765 182.485 35.965 ;
        RECT 263.090 34.250 279.080 34.550 ;
        RECT 262.680 33.650 278.670 33.950 ;
        RECT 54.695 31.925 54.895 33.445 ;
        RECT 262.270 33.050 278.260 33.350 ;
        RECT 261.860 32.450 277.850 32.750 ;
        RECT 90.710 31.855 94.830 31.860 ;
        RECT 52.735 31.360 57.200 31.560 ;
        RECT 54.695 27.200 54.895 30.940 ;
        RECT 78.030 27.325 78.230 31.855 ;
        RECT 79.085 30.975 79.285 31.855 ;
        RECT 87.875 31.660 94.830 31.855 ;
        RECT 261.450 31.850 277.440 32.150 ;
        RECT 87.875 31.655 91.650 31.660 ;
        RECT 117.350 31.465 132.140 31.485 ;
        RECT 116.115 31.265 132.285 31.465 ;
        RECT 117.350 31.255 132.140 31.265 ;
        RECT 261.040 31.250 277.030 31.550 ;
        RECT 78.605 30.275 79.285 30.975 ;
        RECT 260.630 30.650 276.620 30.950 ;
        RECT 79.085 28.155 79.285 30.275 ;
        RECT 260.220 30.050 276.210 30.350 ;
        RECT 102.680 28.685 106.590 29.295 ;
        RECT 78.605 27.455 79.285 28.155 ;
        RECT 78.030 26.930 78.335 27.325 ;
        RECT 53.390 26.795 56.130 26.800 ;
        RECT 52.735 26.595 57.200 26.795 ;
        RECT 63.925 26.595 66.180 26.795 ;
        RECT 54.695 20.560 54.895 26.235 ;
        RECT 54.695 20.360 56.215 20.560 ;
        RECT 65.970 20.030 66.180 26.595 ;
        RECT 79.085 26.525 79.285 27.455 ;
        RECT 78.030 26.290 79.285 26.525 ;
        RECT 90.255 26.300 94.860 26.315 ;
        RECT 78.030 26.130 78.335 26.290 ;
        RECT 87.875 26.115 94.860 26.300 ;
        RECT 103.510 26.295 104.210 26.300 ;
        RECT 105.505 26.295 105.705 26.770 ;
        RECT 106.240 26.710 106.590 28.685 ;
        RECT 106.240 26.510 120.870 26.710 ;
        RECT 130.025 26.510 131.930 26.710 ;
        RECT 87.875 26.100 91.675 26.115 ;
        RECT 90.255 20.555 90.865 21.210 ;
        RECT 91.175 20.555 91.390 26.100 ;
        RECT 103.510 26.070 105.705 26.295 ;
        RECT 89.870 20.355 91.390 20.555 ;
        RECT 43.745 19.805 48.405 20.005 ;
        RECT 65.970 19.830 67.490 20.030 ;
        RECT 95.615 19.810 96.365 20.010 ;
        RECT 43.745 13.555 44.145 19.805 ;
        RECT 43.745 12.945 44.755 13.555 ;
        RECT 43.745 12.925 44.145 12.945 ;
        RECT 58.750 11.985 61.000 18.820 ;
        RECT 73.185 17.135 73.885 17.490 ;
        RECT 84.435 17.135 85.135 17.490 ;
        RECT 95.665 17.135 96.365 19.810 ;
        RECT 103.965 19.755 104.575 20.455 ;
        RECT 130.025 20.005 130.225 26.510 ;
        RECT 247.550 25.110 247.750 27.960 ;
        RECT 128.295 19.805 130.225 20.005 ;
        RECT 106.895 17.135 107.595 17.490 ;
        RECT 118.145 17.135 118.845 17.490 ;
        RECT 129.415 17.135 130.115 17.490 ;
        RECT 73.185 16.795 130.115 17.135 ;
        RECT 73.185 15.475 73.885 16.795 ;
        RECT 84.435 15.475 85.135 16.795 ;
        RECT 95.665 15.475 96.365 16.795 ;
        RECT 106.895 15.475 107.595 16.795 ;
        RECT 118.145 15.475 118.845 16.795 ;
        RECT 129.415 15.475 130.115 16.795 ;
        RECT 73.185 15.135 130.115 15.475 ;
        RECT 73.185 13.805 73.885 15.135 ;
        RECT 84.435 13.805 85.135 15.135 ;
        RECT 95.665 13.805 96.365 15.135 ;
        RECT 106.895 13.805 107.595 15.135 ;
        RECT 118.145 13.805 118.845 15.135 ;
        RECT 129.415 13.805 130.115 15.135 ;
        RECT 73.185 13.465 130.115 13.805 ;
        RECT 248.370 13.600 248.570 27.080 ;
        RECT 249.190 14.480 249.390 26.200 ;
        RECT 250.810 21.960 251.010 28.020 ;
        RECT 251.220 23.010 251.420 27.145 ;
        RECT 251.630 23.435 251.830 26.265 ;
        RECT 256.095 25.645 256.385 25.845 ;
        RECT 251.630 23.235 253.580 23.435 ;
        RECT 251.220 22.810 253.020 23.010 ;
        RECT 252.820 22.215 253.020 22.810 ;
        RECT 253.375 22.465 253.580 23.235 ;
        RECT 253.375 22.215 253.575 22.465 ;
        RECT 253.890 21.960 254.090 22.515 ;
        RECT 250.810 21.760 254.090 21.960 ;
        RECT 256.145 21.840 256.345 25.645 ;
        RECT 255.590 21.350 256.345 21.840 ;
        RECT 257.085 21.960 257.285 28.020 ;
        RECT 257.495 23.010 257.695 27.145 ;
        RECT 262.420 25.515 262.620 25.520 ;
        RECT 262.375 25.315 262.665 25.515 ;
        RECT 257.495 22.810 259.295 23.010 ;
        RECT 259.095 22.215 259.295 22.810 ;
        RECT 260.165 21.960 260.365 22.515 ;
        RECT 257.085 21.760 260.365 21.960 ;
        RECT 262.420 21.840 262.620 25.315 ;
        RECT 261.865 21.350 262.620 21.840 ;
        RECT 263.360 21.960 263.560 28.025 ;
        RECT 264.180 26.045 264.535 26.245 ;
        RECT 264.180 23.435 264.380 26.045 ;
        RECT 268.695 25.175 268.895 25.180 ;
        RECT 268.650 24.975 268.940 25.175 ;
        RECT 264.180 23.235 266.130 23.435 ;
        RECT 265.925 22.465 266.130 23.235 ;
        RECT 265.925 22.215 266.125 22.465 ;
        RECT 266.440 21.960 266.640 22.515 ;
        RECT 263.360 21.760 266.640 21.960 ;
        RECT 268.695 21.840 268.895 24.975 ;
        RECT 268.140 21.350 268.895 21.840 ;
        RECT 269.635 21.960 269.835 28.025 ;
        RECT 276.010 26.040 276.210 26.130 ;
        RECT 275.040 25.840 276.210 26.040 ;
        RECT 275.040 25.705 275.330 25.840 ;
        RECT 276.420 25.540 276.620 25.630 ;
        RECT 275.510 25.340 276.620 25.540 ;
        RECT 275.055 25.040 275.345 25.175 ;
        RECT 276.830 25.040 277.030 25.130 ;
        RECT 275.055 24.840 277.030 25.040 ;
        RECT 274.970 24.540 275.170 24.570 ;
        RECT 277.240 24.540 277.440 24.630 ;
        RECT 274.970 24.340 277.440 24.540 ;
        RECT 272.715 21.960 272.915 22.515 ;
        RECT 269.635 21.760 272.915 21.960 ;
        RECT 274.970 21.840 275.170 24.340 ;
        RECT 274.415 21.350 275.170 21.840 ;
        RECT 255.590 19.060 256.345 19.550 ;
        RECT 261.865 19.060 262.620 19.550 ;
        RECT 268.140 19.060 268.895 19.550 ;
        RECT 274.415 19.060 275.170 19.550 ;
        RECT 256.145 15.025 256.345 19.060 ;
        RECT 259.650 18.435 259.850 18.685 ;
        RECT 259.650 17.665 259.855 18.435 ;
        RECT 257.905 17.465 259.855 17.665 ;
        RECT 256.095 14.825 256.385 15.025 ;
        RECT 256.145 14.820 256.345 14.825 ;
        RECT 257.905 14.635 258.105 17.465 ;
        RECT 262.420 15.365 262.620 19.060 ;
        RECT 265.370 18.090 265.570 18.685 ;
        RECT 263.770 17.890 265.570 18.090 ;
        RECT 262.375 15.165 262.665 15.365 ;
        RECT 257.905 14.435 258.195 14.635 ;
        RECT 257.905 14.430 258.105 14.435 ;
        RECT 263.770 13.535 263.970 17.890 ;
        RECT 268.695 15.705 268.895 19.060 ;
        RECT 271.645 18.090 271.845 18.685 ;
        RECT 270.045 17.890 271.845 18.090 ;
        RECT 272.200 18.435 272.400 18.685 ;
        RECT 268.650 15.505 268.940 15.705 ;
        RECT 268.695 15.500 268.895 15.505 ;
        RECT 270.045 13.535 270.245 17.890 ;
        RECT 272.200 17.665 272.405 18.435 ;
        RECT 270.455 17.465 272.405 17.665 ;
        RECT 270.455 14.635 270.655 17.465 ;
        RECT 274.970 16.340 275.170 19.060 ;
        RECT 277.650 16.340 277.850 16.430 ;
        RECT 274.970 16.140 277.850 16.340 ;
        RECT 278.060 15.840 278.260 15.930 ;
        RECT 275.055 15.640 278.260 15.840 ;
        RECT 275.055 15.505 275.345 15.640 ;
        RECT 278.470 15.340 278.670 15.430 ;
        RECT 275.510 15.140 278.670 15.340 ;
        RECT 275.040 14.840 275.330 14.975 ;
        RECT 278.880 14.840 279.080 14.930 ;
        RECT 275.040 14.640 279.080 14.840 ;
        RECT 270.455 14.435 270.745 14.635 ;
        RECT 270.455 14.430 270.655 14.435 ;
        RECT 73.185 12.285 73.885 13.465 ;
        RECT 84.435 12.285 85.135 13.465 ;
        RECT 95.665 12.285 96.365 13.465 ;
        RECT 106.895 12.285 107.595 13.465 ;
        RECT 118.145 12.285 118.845 13.465 ;
        RECT 129.415 12.285 130.115 13.465 ;
        RECT 55.860 11.785 61.000 11.985 ;
        RECT 58.750 11.330 61.000 11.785 ;
      LAYER Metal3 ;
        RECT 176.565 92.760 176.775 92.810 ;
        RECT 175.440 92.560 177.370 92.760 ;
        RECT 119.480 88.415 120.180 89.025 ;
        RECT 13.230 70.290 13.430 86.555 ;
        RECT 40.690 77.805 41.390 78.415 ;
        RECT 133.960 74.035 134.660 74.645 ;
        RECT 13.230 70.000 23.640 70.290 ;
        RECT 132.050 68.910 132.660 71.250 ;
        RECT 165.745 49.775 165.950 49.780 ;
        RECT 165.745 49.575 166.035 49.775 ;
        RECT 153.100 48.240 156.665 48.245 ;
        RECT 153.095 48.040 156.665 48.240 ;
        RECT 153.100 46.035 156.665 48.040 ;
        RECT 153.095 45.835 156.665 46.035 ;
        RECT 153.100 45.830 156.665 45.835 ;
        RECT 164.615 39.720 165.005 49.055 ;
        RECT 165.745 43.005 165.950 49.575 ;
        RECT 172.405 49.020 172.605 49.065 ;
        RECT 172.340 48.820 172.630 49.020 ;
        RECT 164.025 39.520 165.545 39.720 ;
        RECT 166.250 37.370 166.460 47.610 ;
        RECT 172.405 46.680 172.605 48.820 ;
        RECT 172.400 45.890 172.605 46.680 ;
        RECT 172.400 44.340 172.600 45.890 ;
        RECT 172.150 39.220 172.850 43.765 ;
        RECT 176.565 42.700 176.775 92.560 ;
        RECT 179.350 49.745 179.640 49.775 ;
        RECT 179.350 49.575 179.675 49.745 ;
        RECT 176.525 42.500 176.815 42.700 ;
        RECT 176.565 39.695 176.775 42.500 ;
        RECT 177.760 41.250 177.960 48.115 ;
        RECT 179.030 39.695 179.230 39.745 ;
        RECT 176.565 39.290 179.255 39.695 ;
        RECT 176.565 39.050 176.775 39.290 ;
        RECT 179.030 39.045 179.230 39.290 ;
        RECT 166.210 37.170 166.500 37.370 ;
        RECT 172.395 35.965 172.605 38.810 ;
        RECT 179.475 37.950 179.675 49.575 ;
        RECT 183.130 40.800 185.060 41.765 ;
        RECT 187.370 40.585 188.070 41.195 ;
        RECT 182.265 37.700 185.015 37.900 ;
        RECT 182.265 35.965 182.485 37.700 ;
        RECT 172.395 35.765 172.695 35.965 ;
        RECT 182.195 35.765 182.485 35.965 ;
        RECT 90.255 20.510 90.865 21.210 ;
        RECT 103.965 19.755 104.575 20.455 ;
        RECT 58.750 11.330 61.000 18.820 ;
      LAYER Metal4 ;
        RECT 119.480 88.415 120.180 89.025 ;
        RECT 40.690 77.805 41.390 78.415 ;
        RECT 133.960 74.035 134.660 74.645 ;
        RECT 132.050 68.910 132.660 71.250 ;
        RECT 187.370 40.585 188.070 41.195 ;
        RECT 90.255 20.510 90.865 21.210 ;
        RECT 103.965 19.755 104.575 20.455 ;
        RECT 58.750 11.330 61.000 18.820 ;
      LAYER Metal5 ;
        RECT 62.780 92.635 120.840 93.235 ;
        RECT 40.690 77.800 41.390 78.420 ;
        RECT 62.780 68.635 79.180 92.635 ;
        RECT 104.440 68.635 120.840 92.635 ;
        RECT 133.960 74.030 134.660 74.650 ;
        RECT 62.780 60.435 70.980 68.635 ;
        RECT 112.640 60.435 120.840 68.635 ;
        RECT 129.235 66.990 135.435 73.190 ;
        RECT 187.370 40.580 188.070 41.200 ;
        RECT 4.475 9.690 89.480 37.890 ;
        RECT 90.250 20.510 90.870 21.210 ;
        RECT 94.585 9.690 140.785 37.890 ;
        RECT 4.475 8.690 43.840 9.690 ;
      LAYER TopMetal1 ;
        RECT 40.220 76.445 41.860 78.930 ;
        RECT 35.420 70.145 45.500 76.445 ;
        RECT 133.490 72.610 135.130 75.160 ;
        RECT 129.815 71.580 135.130 72.610 ;
        RECT 129.815 67.570 134.855 71.580 ;
        RECT 186.770 39.940 188.670 41.840 ;
        RECT 5.215 37.020 43.150 37.150 ;
        RECT 5.215 21.680 88.430 37.020 ;
        RECT 5.215 20.040 91.380 21.680 ;
        RECT 5.215 10.560 88.430 20.040 ;
        RECT 5.215 9.430 48.335 10.560 ;
        RECT 190.490 7.570 232.070 49.150 ;
      LAYER TopMetal2 ;
        RECT 186.720 39.890 193.330 41.890 ;
  END
END TOP_ANALOG
END LIBRARY

